VERSION 5.8 ;
BUSBITCHARS "[]" ;
DIVIDERCHAR "/" ;
UNITS
    DATABASE MICRONS 1000 ;
END UNITS

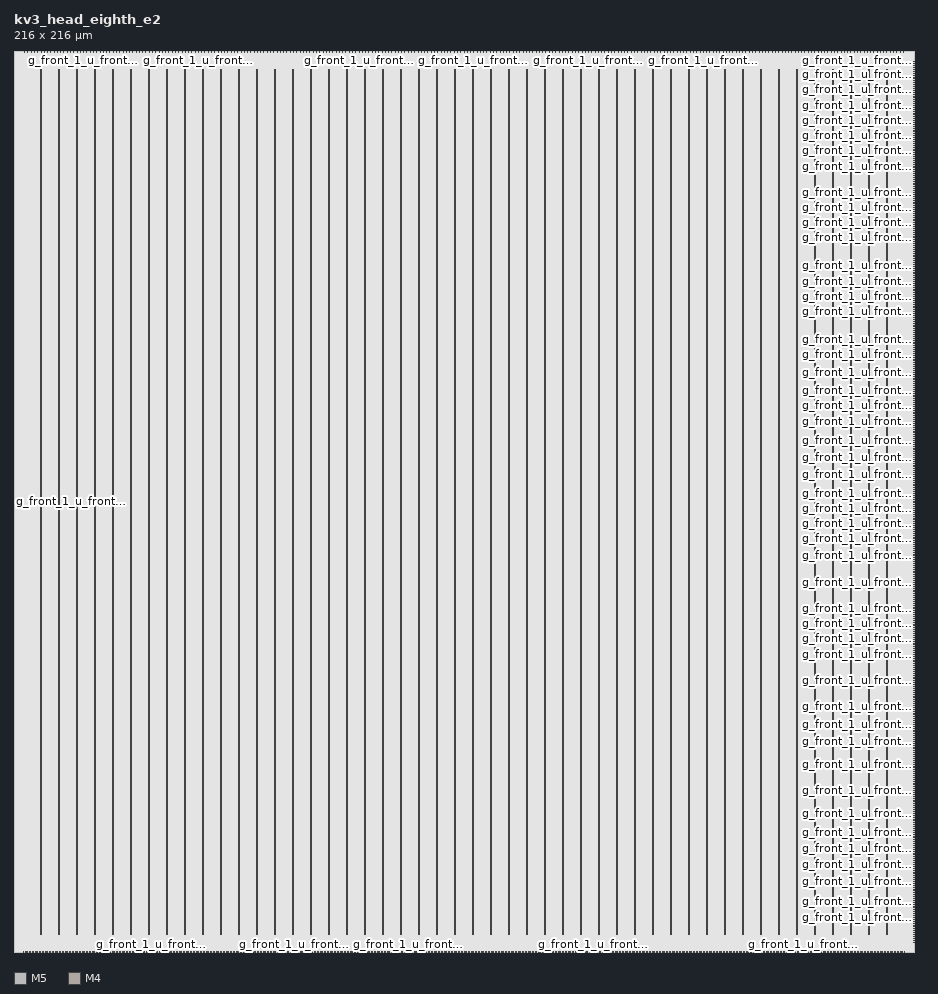
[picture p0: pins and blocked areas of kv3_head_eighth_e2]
MACRO kv3_head_eighth_e2
  FOREIGN kv3_head_eighth_e2 0 0 ;
  CLASS BLOCK ;
  SIZE 216 BY 216 ;
  PIN g_front_1_u_front__c_in[0]
    DIRECTION INPUT ;
    USE SIGNAL ;
    PORT
      LAYER M5 ;
        RECT  2.316 0 2.34 0.192 ;
    END
  END g_front_1_u_front__c_in[0]
  PIN g_front_1_u_front__c_in[1]
    DIRECTION INPUT ;
    USE SIGNAL ;
    PORT
      LAYER M5 ;
        RECT  2.652 0 2.676 0.192 ;
    END
  END g_front_1_u_front__c_in[1]
  PIN g_front_1_u_front__c_in[2]
    DIRECTION INPUT ;
    USE SIGNAL ;
    PORT
      LAYER M5 ;
        RECT  2.988 0 3.012 0.192 ;
    END
  END g_front_1_u_front__c_in[2]
  PIN g_front_1_u_front__c_in[3]
    DIRECTION INPUT ;
    USE SIGNAL ;
    PORT
      LAYER M5 ;
        RECT  3.324 0 3.348 0.192 ;
    END
  END g_front_1_u_front__c_in[3]
  PIN g_front_1_u_front__clk[0]
    DIRECTION INPUT ;
    USE SIGNAL ;
    PORT
      LAYER M5 ;
        RECT  2.556 215.808 2.58 216 ;
    END
  END g_front_1_u_front__clk[0]
  PIN g_front_1_u_front__e_in[0]
    DIRECTION INPUT ;
    USE SIGNAL ;
    PORT
      LAYER M5 ;
        RECT  3.708 0 3.732 0.192 ;
    END
  END g_front_1_u_front__e_in[0]
  PIN g_front_1_u_front__e_in[10]
    DIRECTION INPUT ;
    USE SIGNAL ;
    PORT
      LAYER M5 ;
        RECT  7.116 0 7.14 0.192 ;
    END
  END g_front_1_u_front__e_in[10]
  PIN g_front_1_u_front__e_in[11]
    DIRECTION INPUT ;
    USE SIGNAL ;
    PORT
      LAYER M5 ;
        RECT  7.452 0 7.476 0.192 ;
    END
  END g_front_1_u_front__e_in[11]
  PIN g_front_1_u_front__e_in[12]
    DIRECTION INPUT ;
    USE SIGNAL ;
    PORT
      LAYER M5 ;
        RECT  7.788 0 7.812 0.192 ;
    END
  END g_front_1_u_front__e_in[12]
  PIN g_front_1_u_front__e_in[13]
    DIRECTION INPUT ;
    USE SIGNAL ;
    PORT
      LAYER M5 ;
        RECT  8.124 0 8.148 0.192 ;
    END
  END g_front_1_u_front__e_in[13]
  PIN g_front_1_u_front__e_in[14]
    DIRECTION INPUT ;
    USE SIGNAL ;
    PORT
      LAYER M5 ;
        RECT  8.46 0 8.484 0.192 ;
    END
  END g_front_1_u_front__e_in[14]
  PIN g_front_1_u_front__e_in[15]
    DIRECTION INPUT ;
    USE SIGNAL ;
    PORT
      LAYER M5 ;
        RECT  8.796 0 8.82 0.192 ;
    END
  END g_front_1_u_front__e_in[15]
  PIN g_front_1_u_front__e_in[1]
    DIRECTION INPUT ;
    USE SIGNAL ;
    PORT
      LAYER M5 ;
        RECT  4.044 0 4.068 0.192 ;
    END
  END g_front_1_u_front__e_in[1]
  PIN g_front_1_u_front__e_in[2]
    DIRECTION INPUT ;
    USE SIGNAL ;
    PORT
      LAYER M5 ;
        RECT  4.38 0 4.404 0.192 ;
    END
  END g_front_1_u_front__e_in[2]
  PIN g_front_1_u_front__e_in[3]
    DIRECTION INPUT ;
    USE SIGNAL ;
    PORT
      LAYER M5 ;
        RECT  4.716 0 4.74 0.192 ;
    END
  END g_front_1_u_front__e_in[3]
  PIN g_front_1_u_front__e_in[4]
    DIRECTION INPUT ;
    USE SIGNAL ;
    PORT
      LAYER M5 ;
        RECT  5.052 0 5.076 0.192 ;
    END
  END g_front_1_u_front__e_in[4]
  PIN g_front_1_u_front__e_in[5]
    DIRECTION INPUT ;
    USE SIGNAL ;
    PORT
      LAYER M5 ;
        RECT  5.388 0 5.412 0.192 ;
    END
  END g_front_1_u_front__e_in[5]
  PIN g_front_1_u_front__e_in[6]
    DIRECTION INPUT ;
    USE SIGNAL ;
    PORT
      LAYER M5 ;
        RECT  5.724 0 5.748 0.192 ;
    END
  END g_front_1_u_front__e_in[6]
  PIN g_front_1_u_front__e_in[7]
    DIRECTION INPUT ;
    USE SIGNAL ;
    PORT
      LAYER M5 ;
        RECT  6.06 0 6.084 0.192 ;
    END
  END g_front_1_u_front__e_in[7]
  PIN g_front_1_u_front__e_in[8]
    DIRECTION INPUT ;
    USE SIGNAL ;
    PORT
      LAYER M5 ;
        RECT  6.444 0 6.468 0.192 ;
    END
  END g_front_1_u_front__e_in[8]
  PIN g_front_1_u_front__e_in[9]
    DIRECTION INPUT ;
    USE SIGNAL ;
    PORT
      LAYER M5 ;
        RECT  6.78 0 6.804 0.192 ;
    END
  END g_front_1_u_front__e_in[9]
  PIN g_front_1_u_front__f_t2[0]
    DIRECTION OUTPUT ;
    USE SIGNAL ;
    PORT
      LAYER M4 ;
        RECT  215.808 2.364 216 2.388 ;
    END
  END g_front_1_u_front__f_t2[0]
  PIN g_front_1_u_front__f_t2[100]
    DIRECTION OUTPUT ;
    USE SIGNAL ;
    PORT
      LAYER M4 ;
        RECT  215.808 47.82 216 47.844 ;
    END
  END g_front_1_u_front__f_t2[100]
  PIN g_front_1_u_front__f_t2[101]
    DIRECTION OUTPUT ;
    USE SIGNAL ;
    PORT
      LAYER M4 ;
        RECT  215.808 48.252 216 48.276 ;
    END
  END g_front_1_u_front__f_t2[101]
  PIN g_front_1_u_front__f_t2[102]
    DIRECTION OUTPUT ;
    USE SIGNAL ;
    PORT
      LAYER M4 ;
        RECT  215.808 48.732 216 48.756 ;
    END
  END g_front_1_u_front__f_t2[102]
  PIN g_front_1_u_front__f_t2[103]
    DIRECTION OUTPUT ;
    USE SIGNAL ;
    PORT
      LAYER M4 ;
        RECT  215.808 49.164 216 49.188 ;
    END
  END g_front_1_u_front__f_t2[103]
  PIN g_front_1_u_front__f_t2[104]
    DIRECTION OUTPUT ;
    USE SIGNAL ;
    PORT
      LAYER M4 ;
        RECT  215.808 49.596 216 49.62 ;
    END
  END g_front_1_u_front__f_t2[104]
  PIN g_front_1_u_front__f_t2[105]
    DIRECTION OUTPUT ;
    USE SIGNAL ;
    PORT
      LAYER M4 ;
        RECT  215.808 50.076 216 50.1 ;
    END
  END g_front_1_u_front__f_t2[105]
  PIN g_front_1_u_front__f_t2[106]
    DIRECTION OUTPUT ;
    USE SIGNAL ;
    PORT
      LAYER M4 ;
        RECT  215.808 50.508 216 50.532 ;
    END
  END g_front_1_u_front__f_t2[106]
  PIN g_front_1_u_front__f_t2[107]
    DIRECTION OUTPUT ;
    USE SIGNAL ;
    PORT
      LAYER M4 ;
        RECT  215.808 50.988 216 51.012 ;
    END
  END g_front_1_u_front__f_t2[107]
  PIN g_front_1_u_front__f_t2[108]
    DIRECTION OUTPUT ;
    USE SIGNAL ;
    PORT
      LAYER M4 ;
        RECT  215.808 51.42 216 51.444 ;
    END
  END g_front_1_u_front__f_t2[108]
  PIN g_front_1_u_front__f_t2[109]
    DIRECTION OUTPUT ;
    USE SIGNAL ;
    PORT
      LAYER M4 ;
        RECT  215.808 51.9 216 51.924 ;
    END
  END g_front_1_u_front__f_t2[109]
  PIN g_front_1_u_front__f_t2[10]
    DIRECTION OUTPUT ;
    USE SIGNAL ;
    PORT
      LAYER M4 ;
        RECT  215.808 6.924 216 6.948 ;
    END
  END g_front_1_u_front__f_t2[10]
  PIN g_front_1_u_front__f_t2[110]
    DIRECTION OUTPUT ;
    USE SIGNAL ;
    PORT
      LAYER M4 ;
        RECT  215.808 52.332 216 52.356 ;
    END
  END g_front_1_u_front__f_t2[110]
  PIN g_front_1_u_front__f_t2[111]
    DIRECTION OUTPUT ;
    USE SIGNAL ;
    PORT
      LAYER M4 ;
        RECT  215.808 52.812 216 52.836 ;
    END
  END g_front_1_u_front__f_t2[111]
  PIN g_front_1_u_front__f_t2[112]
    DIRECTION OUTPUT ;
    USE SIGNAL ;
    PORT
      LAYER M4 ;
        RECT  215.808 53.244 216 53.268 ;
    END
  END g_front_1_u_front__f_t2[112]
  PIN g_front_1_u_front__f_t2[113]
    DIRECTION OUTPUT ;
    USE SIGNAL ;
    PORT
      LAYER M4 ;
        RECT  215.808 53.724 216 53.748 ;
    END
  END g_front_1_u_front__f_t2[113]
  PIN g_front_1_u_front__f_t2[114]
    DIRECTION OUTPUT ;
    USE SIGNAL ;
    PORT
      LAYER M4 ;
        RECT  215.808 54.156 216 54.18 ;
    END
  END g_front_1_u_front__f_t2[114]
  PIN g_front_1_u_front__f_t2[115]
    DIRECTION OUTPUT ;
    USE SIGNAL ;
    PORT
      LAYER M4 ;
        RECT  215.808 54.636 216 54.66 ;
    END
  END g_front_1_u_front__f_t2[115]
  PIN g_front_1_u_front__f_t2[116]
    DIRECTION OUTPUT ;
    USE SIGNAL ;
    PORT
      LAYER M4 ;
        RECT  215.808 55.068 216 55.092 ;
    END
  END g_front_1_u_front__f_t2[116]
  PIN g_front_1_u_front__f_t2[117]
    DIRECTION OUTPUT ;
    USE SIGNAL ;
    PORT
      LAYER M4 ;
        RECT  215.808 55.5 216 55.524 ;
    END
  END g_front_1_u_front__f_t2[117]
  PIN g_front_1_u_front__f_t2[118]
    DIRECTION OUTPUT ;
    USE SIGNAL ;
    PORT
      LAYER M4 ;
        RECT  215.808 55.98 216 56.004 ;
    END
  END g_front_1_u_front__f_t2[118]
  PIN g_front_1_u_front__f_t2[119]
    DIRECTION OUTPUT ;
    USE SIGNAL ;
    PORT
      LAYER M4 ;
        RECT  215.808 56.412 216 56.436 ;
    END
  END g_front_1_u_front__f_t2[119]
  PIN g_front_1_u_front__f_t2[11]
    DIRECTION OUTPUT ;
    USE SIGNAL ;
    PORT
      LAYER M4 ;
        RECT  215.808 7.356 216 7.38 ;
    END
  END g_front_1_u_front__f_t2[11]
  PIN g_front_1_u_front__f_t2[120]
    DIRECTION OUTPUT ;
    USE SIGNAL ;
    PORT
      LAYER M4 ;
        RECT  215.808 56.892 216 56.916 ;
    END
  END g_front_1_u_front__f_t2[120]
  PIN g_front_1_u_front__f_t2[121]
    DIRECTION OUTPUT ;
    USE SIGNAL ;
    PORT
      LAYER M4 ;
        RECT  215.808 57.324 216 57.348 ;
    END
  END g_front_1_u_front__f_t2[121]
  PIN g_front_1_u_front__f_t2[122]
    DIRECTION OUTPUT ;
    USE SIGNAL ;
    PORT
      LAYER M4 ;
        RECT  215.808 57.804 216 57.828 ;
    END
  END g_front_1_u_front__f_t2[122]
  PIN g_front_1_u_front__f_t2[123]
    DIRECTION OUTPUT ;
    USE SIGNAL ;
    PORT
      LAYER M4 ;
        RECT  215.808 58.236 216 58.26 ;
    END
  END g_front_1_u_front__f_t2[123]
  PIN g_front_1_u_front__f_t2[124]
    DIRECTION OUTPUT ;
    USE SIGNAL ;
    PORT
      LAYER M4 ;
        RECT  215.808 58.716 216 58.74 ;
    END
  END g_front_1_u_front__f_t2[124]
  PIN g_front_1_u_front__f_t2[125]
    DIRECTION OUTPUT ;
    USE SIGNAL ;
    PORT
      LAYER M4 ;
        RECT  215.808 59.148 216 59.172 ;
    END
  END g_front_1_u_front__f_t2[125]
  PIN g_front_1_u_front__f_t2[126]
    DIRECTION OUTPUT ;
    USE SIGNAL ;
    PORT
      LAYER M4 ;
        RECT  215.808 59.628 216 59.652 ;
    END
  END g_front_1_u_front__f_t2[126]
  PIN g_front_1_u_front__f_t2[127]
    DIRECTION OUTPUT ;
    USE SIGNAL ;
    PORT
      LAYER M4 ;
        RECT  215.808 60.06 216 60.084 ;
    END
  END g_front_1_u_front__f_t2[127]
  PIN g_front_1_u_front__f_t2[128]
    DIRECTION OUTPUT ;
    USE SIGNAL ;
    PORT
      LAYER M4 ;
        RECT  215.808 60.54 216 60.564 ;
    END
  END g_front_1_u_front__f_t2[128]
  PIN g_front_1_u_front__f_t2[129]
    DIRECTION OUTPUT ;
    USE SIGNAL ;
    PORT
      LAYER M4 ;
        RECT  215.808 60.972 216 60.996 ;
    END
  END g_front_1_u_front__f_t2[129]
  PIN g_front_1_u_front__f_t2[12]
    DIRECTION OUTPUT ;
    USE SIGNAL ;
    PORT
      LAYER M4 ;
        RECT  215.808 7.836 216 7.86 ;
    END
  END g_front_1_u_front__f_t2[12]
  PIN g_front_1_u_front__f_t2[130]
    DIRECTION OUTPUT ;
    USE SIGNAL ;
    PORT
      LAYER M4 ;
        RECT  215.808 61.404 216 61.428 ;
    END
  END g_front_1_u_front__f_t2[130]
  PIN g_front_1_u_front__f_t2[131]
    DIRECTION OUTPUT ;
    USE SIGNAL ;
    PORT
      LAYER M4 ;
        RECT  215.808 61.884 216 61.908 ;
    END
  END g_front_1_u_front__f_t2[131]
  PIN g_front_1_u_front__f_t2[132]
    DIRECTION OUTPUT ;
    USE SIGNAL ;
    PORT
      LAYER M4 ;
        RECT  215.808 62.316 216 62.34 ;
    END
  END g_front_1_u_front__f_t2[132]
  PIN g_front_1_u_front__f_t2[133]
    DIRECTION OUTPUT ;
    USE SIGNAL ;
    PORT
      LAYER M4 ;
        RECT  215.808 62.796 216 62.82 ;
    END
  END g_front_1_u_front__f_t2[133]
  PIN g_front_1_u_front__f_t2[134]
    DIRECTION OUTPUT ;
    USE SIGNAL ;
    PORT
      LAYER M4 ;
        RECT  215.808 63.228 216 63.252 ;
    END
  END g_front_1_u_front__f_t2[134]
  PIN g_front_1_u_front__f_t2[135]
    DIRECTION OUTPUT ;
    USE SIGNAL ;
    PORT
      LAYER M4 ;
        RECT  215.808 63.708 216 63.732 ;
    END
  END g_front_1_u_front__f_t2[135]
  PIN g_front_1_u_front__f_t2[136]
    DIRECTION OUTPUT ;
    USE SIGNAL ;
    PORT
      LAYER M4 ;
        RECT  215.808 64.14 216 64.164 ;
    END
  END g_front_1_u_front__f_t2[136]
  PIN g_front_1_u_front__f_t2[137]
    DIRECTION OUTPUT ;
    USE SIGNAL ;
    PORT
      LAYER M4 ;
        RECT  215.808 64.62 216 64.644 ;
    END
  END g_front_1_u_front__f_t2[137]
  PIN g_front_1_u_front__f_t2[138]
    DIRECTION OUTPUT ;
    USE SIGNAL ;
    PORT
      LAYER M4 ;
        RECT  215.808 65.052 216 65.076 ;
    END
  END g_front_1_u_front__f_t2[138]
  PIN g_front_1_u_front__f_t2[139]
    DIRECTION OUTPUT ;
    USE SIGNAL ;
    PORT
      LAYER M4 ;
        RECT  215.808 65.532 216 65.556 ;
    END
  END g_front_1_u_front__f_t2[139]
  PIN g_front_1_u_front__f_t2[13]
    DIRECTION OUTPUT ;
    USE SIGNAL ;
    PORT
      LAYER M4 ;
        RECT  215.808 8.268 216 8.292 ;
    END
  END g_front_1_u_front__f_t2[13]
  PIN g_front_1_u_front__f_t2[140]
    DIRECTION OUTPUT ;
    USE SIGNAL ;
    PORT
      LAYER M4 ;
        RECT  215.808 65.964 216 65.988 ;
    END
  END g_front_1_u_front__f_t2[140]
  PIN g_front_1_u_front__f_t2[141]
    DIRECTION OUTPUT ;
    USE SIGNAL ;
    PORT
      LAYER M4 ;
        RECT  215.808 66.444 216 66.468 ;
    END
  END g_front_1_u_front__f_t2[141]
  PIN g_front_1_u_front__f_t2[142]
    DIRECTION OUTPUT ;
    USE SIGNAL ;
    PORT
      LAYER M4 ;
        RECT  215.808 66.876 216 66.9 ;
    END
  END g_front_1_u_front__f_t2[142]
  PIN g_front_1_u_front__f_t2[143]
    DIRECTION OUTPUT ;
    USE SIGNAL ;
    PORT
      LAYER M4 ;
        RECT  215.808 67.356 216 67.38 ;
    END
  END g_front_1_u_front__f_t2[143]
  PIN g_front_1_u_front__f_t2[144]
    DIRECTION OUTPUT ;
    USE SIGNAL ;
    PORT
      LAYER M4 ;
        RECT  215.808 67.788 216 67.812 ;
    END
  END g_front_1_u_front__f_t2[144]
  PIN g_front_1_u_front__f_t2[145]
    DIRECTION OUTPUT ;
    USE SIGNAL ;
    PORT
      LAYER M4 ;
        RECT  215.808 68.22 216 68.244 ;
    END
  END g_front_1_u_front__f_t2[145]
  PIN g_front_1_u_front__f_t2[146]
    DIRECTION OUTPUT ;
    USE SIGNAL ;
    PORT
      LAYER M4 ;
        RECT  215.808 68.7 216 68.724 ;
    END
  END g_front_1_u_front__f_t2[146]
  PIN g_front_1_u_front__f_t2[147]
    DIRECTION OUTPUT ;
    USE SIGNAL ;
    PORT
      LAYER M4 ;
        RECT  215.808 69.132 216 69.156 ;
    END
  END g_front_1_u_front__f_t2[147]
  PIN g_front_1_u_front__f_t2[148]
    DIRECTION OUTPUT ;
    USE SIGNAL ;
    PORT
      LAYER M4 ;
        RECT  215.808 69.612 216 69.636 ;
    END
  END g_front_1_u_front__f_t2[148]
  PIN g_front_1_u_front__f_t2[149]
    DIRECTION OUTPUT ;
    USE SIGNAL ;
    PORT
      LAYER M4 ;
        RECT  215.808 70.044 216 70.068 ;
    END
  END g_front_1_u_front__f_t2[149]
  PIN g_front_1_u_front__f_t2[14]
    DIRECTION OUTPUT ;
    USE SIGNAL ;
    PORT
      LAYER M4 ;
        RECT  215.808 8.748 216 8.772 ;
    END
  END g_front_1_u_front__f_t2[14]
  PIN g_front_1_u_front__f_t2[150]
    DIRECTION OUTPUT ;
    USE SIGNAL ;
    PORT
      LAYER M4 ;
        RECT  215.808 70.524 216 70.548 ;
    END
  END g_front_1_u_front__f_t2[150]
  PIN g_front_1_u_front__f_t2[151]
    DIRECTION OUTPUT ;
    USE SIGNAL ;
    PORT
      LAYER M4 ;
        RECT  215.808 70.956 216 70.98 ;
    END
  END g_front_1_u_front__f_t2[151]
  PIN g_front_1_u_front__f_t2[152]
    DIRECTION OUTPUT ;
    USE SIGNAL ;
    PORT
      LAYER M4 ;
        RECT  215.808 71.436 216 71.46 ;
    END
  END g_front_1_u_front__f_t2[152]
  PIN g_front_1_u_front__f_t2[153]
    DIRECTION OUTPUT ;
    USE SIGNAL ;
    PORT
      LAYER M4 ;
        RECT  215.808 71.868 216 71.892 ;
    END
  END g_front_1_u_front__f_t2[153]
  PIN g_front_1_u_front__f_t2[154]
    DIRECTION OUTPUT ;
    USE SIGNAL ;
    PORT
      LAYER M4 ;
        RECT  215.808 72.348 216 72.372 ;
    END
  END g_front_1_u_front__f_t2[154]
  PIN g_front_1_u_front__f_t2[155]
    DIRECTION OUTPUT ;
    USE SIGNAL ;
    PORT
      LAYER M4 ;
        RECT  215.808 72.78 216 72.804 ;
    END
  END g_front_1_u_front__f_t2[155]
  PIN g_front_1_u_front__f_t2[156]
    DIRECTION OUTPUT ;
    USE SIGNAL ;
    PORT
      LAYER M4 ;
        RECT  215.808 73.26 216 73.284 ;
    END
  END g_front_1_u_front__f_t2[156]
  PIN g_front_1_u_front__f_t2[157]
    DIRECTION OUTPUT ;
    USE SIGNAL ;
    PORT
      LAYER M4 ;
        RECT  215.808 73.692 216 73.716 ;
    END
  END g_front_1_u_front__f_t2[157]
  PIN g_front_1_u_front__f_t2[158]
    DIRECTION OUTPUT ;
    USE SIGNAL ;
    PORT
      LAYER M4 ;
        RECT  215.808 74.124 216 74.148 ;
    END
  END g_front_1_u_front__f_t2[158]
  PIN g_front_1_u_front__f_t2[159]
    DIRECTION OUTPUT ;
    USE SIGNAL ;
    PORT
      LAYER M4 ;
        RECT  215.808 74.604 216 74.628 ;
    END
  END g_front_1_u_front__f_t2[159]
  PIN g_front_1_u_front__f_t2[15]
    DIRECTION OUTPUT ;
    USE SIGNAL ;
    PORT
      LAYER M4 ;
        RECT  215.808 9.18 216 9.204 ;
    END
  END g_front_1_u_front__f_t2[15]
  PIN g_front_1_u_front__f_t2[160]
    DIRECTION OUTPUT ;
    USE SIGNAL ;
    PORT
      LAYER M4 ;
        RECT  215.808 75.036 216 75.06 ;
    END
  END g_front_1_u_front__f_t2[160]
  PIN g_front_1_u_front__f_t2[161]
    DIRECTION OUTPUT ;
    USE SIGNAL ;
    PORT
      LAYER M4 ;
        RECT  215.808 75.516 216 75.54 ;
    END
  END g_front_1_u_front__f_t2[161]
  PIN g_front_1_u_front__f_t2[162]
    DIRECTION OUTPUT ;
    USE SIGNAL ;
    PORT
      LAYER M4 ;
        RECT  215.808 75.948 216 75.972 ;
    END
  END g_front_1_u_front__f_t2[162]
  PIN g_front_1_u_front__f_t2[163]
    DIRECTION OUTPUT ;
    USE SIGNAL ;
    PORT
      LAYER M4 ;
        RECT  215.808 76.428 216 76.452 ;
    END
  END g_front_1_u_front__f_t2[163]
  PIN g_front_1_u_front__f_t2[164]
    DIRECTION OUTPUT ;
    USE SIGNAL ;
    PORT
      LAYER M4 ;
        RECT  215.808 76.86 216 76.884 ;
    END
  END g_front_1_u_front__f_t2[164]
  PIN g_front_1_u_front__f_t2[165]
    DIRECTION OUTPUT ;
    USE SIGNAL ;
    PORT
      LAYER M4 ;
        RECT  215.808 77.34 216 77.364 ;
    END
  END g_front_1_u_front__f_t2[165]
  PIN g_front_1_u_front__f_t2[166]
    DIRECTION OUTPUT ;
    USE SIGNAL ;
    PORT
      LAYER M4 ;
        RECT  215.808 77.772 216 77.796 ;
    END
  END g_front_1_u_front__f_t2[166]
  PIN g_front_1_u_front__f_t2[167]
    DIRECTION OUTPUT ;
    USE SIGNAL ;
    PORT
      LAYER M4 ;
        RECT  215.808 78.252 216 78.276 ;
    END
  END g_front_1_u_front__f_t2[167]
  PIN g_front_1_u_front__f_t2[168]
    DIRECTION OUTPUT ;
    USE SIGNAL ;
    PORT
      LAYER M4 ;
        RECT  215.808 78.684 216 78.708 ;
    END
  END g_front_1_u_front__f_t2[168]
  PIN g_front_1_u_front__f_t2[169]
    DIRECTION OUTPUT ;
    USE SIGNAL ;
    PORT
      LAYER M4 ;
        RECT  215.808 79.164 216 79.188 ;
    END
  END g_front_1_u_front__f_t2[169]
  PIN g_front_1_u_front__f_t2[16]
    DIRECTION OUTPUT ;
    USE SIGNAL ;
    PORT
      LAYER M4 ;
        RECT  215.808 9.66 216 9.684 ;
    END
  END g_front_1_u_front__f_t2[16]
  PIN g_front_1_u_front__f_t2[170]
    DIRECTION OUTPUT ;
    USE SIGNAL ;
    PORT
      LAYER M4 ;
        RECT  215.808 79.596 216 79.62 ;
    END
  END g_front_1_u_front__f_t2[170]
  PIN g_front_1_u_front__f_t2[171]
    DIRECTION OUTPUT ;
    USE SIGNAL ;
    PORT
      LAYER M4 ;
        RECT  215.808 80.028 216 80.052 ;
    END
  END g_front_1_u_front__f_t2[171]
  PIN g_front_1_u_front__f_t2[172]
    DIRECTION OUTPUT ;
    USE SIGNAL ;
    PORT
      LAYER M4 ;
        RECT  215.808 80.508 216 80.532 ;
    END
  END g_front_1_u_front__f_t2[172]
  PIN g_front_1_u_front__f_t2[173]
    DIRECTION OUTPUT ;
    USE SIGNAL ;
    PORT
      LAYER M4 ;
        RECT  215.808 80.94 216 80.964 ;
    END
  END g_front_1_u_front__f_t2[173]
  PIN g_front_1_u_front__f_t2[174]
    DIRECTION OUTPUT ;
    USE SIGNAL ;
    PORT
      LAYER M4 ;
        RECT  215.808 81.42 216 81.444 ;
    END
  END g_front_1_u_front__f_t2[174]
  PIN g_front_1_u_front__f_t2[175]
    DIRECTION OUTPUT ;
    USE SIGNAL ;
    PORT
      LAYER M4 ;
        RECT  215.808 81.852 216 81.876 ;
    END
  END g_front_1_u_front__f_t2[175]
  PIN g_front_1_u_front__f_t2[176]
    DIRECTION OUTPUT ;
    USE SIGNAL ;
    PORT
      LAYER M4 ;
        RECT  215.808 82.332 216 82.356 ;
    END
  END g_front_1_u_front__f_t2[176]
  PIN g_front_1_u_front__f_t2[177]
    DIRECTION OUTPUT ;
    USE SIGNAL ;
    PORT
      LAYER M4 ;
        RECT  215.808 82.764 216 82.788 ;
    END
  END g_front_1_u_front__f_t2[177]
  PIN g_front_1_u_front__f_t2[178]
    DIRECTION OUTPUT ;
    USE SIGNAL ;
    PORT
      LAYER M4 ;
        RECT  215.808 83.244 216 83.268 ;
    END
  END g_front_1_u_front__f_t2[178]
  PIN g_front_1_u_front__f_t2[179]
    DIRECTION OUTPUT ;
    USE SIGNAL ;
    PORT
      LAYER M4 ;
        RECT  215.808 83.676 216 83.7 ;
    END
  END g_front_1_u_front__f_t2[179]
  PIN g_front_1_u_front__f_t2[17]
    DIRECTION OUTPUT ;
    USE SIGNAL ;
    PORT
      LAYER M4 ;
        RECT  215.808 10.092 216 10.116 ;
    END
  END g_front_1_u_front__f_t2[17]
  PIN g_front_1_u_front__f_t2[180]
    DIRECTION OUTPUT ;
    USE SIGNAL ;
    PORT
      LAYER M4 ;
        RECT  215.808 84.156 216 84.18 ;
    END
  END g_front_1_u_front__f_t2[180]
  PIN g_front_1_u_front__f_t2[181]
    DIRECTION OUTPUT ;
    USE SIGNAL ;
    PORT
      LAYER M4 ;
        RECT  215.808 84.588 216 84.612 ;
    END
  END g_front_1_u_front__f_t2[181]
  PIN g_front_1_u_front__f_t2[182]
    DIRECTION OUTPUT ;
    USE SIGNAL ;
    PORT
      LAYER M4 ;
        RECT  215.808 85.068 216 85.092 ;
    END
  END g_front_1_u_front__f_t2[182]
  PIN g_front_1_u_front__f_t2[183]
    DIRECTION OUTPUT ;
    USE SIGNAL ;
    PORT
      LAYER M4 ;
        RECT  215.808 85.5 216 85.524 ;
    END
  END g_front_1_u_front__f_t2[183]
  PIN g_front_1_u_front__f_t2[184]
    DIRECTION OUTPUT ;
    USE SIGNAL ;
    PORT
      LAYER M4 ;
        RECT  215.808 85.98 216 86.004 ;
    END
  END g_front_1_u_front__f_t2[184]
  PIN g_front_1_u_front__f_t2[185]
    DIRECTION OUTPUT ;
    USE SIGNAL ;
    PORT
      LAYER M4 ;
        RECT  215.808 86.412 216 86.436 ;
    END
  END g_front_1_u_front__f_t2[185]
  PIN g_front_1_u_front__f_t2[186]
    DIRECTION OUTPUT ;
    USE SIGNAL ;
    PORT
      LAYER M4 ;
        RECT  215.808 86.844 216 86.868 ;
    END
  END g_front_1_u_front__f_t2[186]
  PIN g_front_1_u_front__f_t2[187]
    DIRECTION OUTPUT ;
    USE SIGNAL ;
    PORT
      LAYER M4 ;
        RECT  215.808 87.324 216 87.348 ;
    END
  END g_front_1_u_front__f_t2[187]
  PIN g_front_1_u_front__f_t2[188]
    DIRECTION OUTPUT ;
    USE SIGNAL ;
    PORT
      LAYER M4 ;
        RECT  215.808 87.756 216 87.78 ;
    END
  END g_front_1_u_front__f_t2[188]
  PIN g_front_1_u_front__f_t2[189]
    DIRECTION OUTPUT ;
    USE SIGNAL ;
    PORT
      LAYER M4 ;
        RECT  215.808 88.236 216 88.26 ;
    END
  END g_front_1_u_front__f_t2[189]
  PIN g_front_1_u_front__f_t2[18]
    DIRECTION OUTPUT ;
    USE SIGNAL ;
    PORT
      LAYER M4 ;
        RECT  215.808 10.572 216 10.596 ;
    END
  END g_front_1_u_front__f_t2[18]
  PIN g_front_1_u_front__f_t2[190]
    DIRECTION OUTPUT ;
    USE SIGNAL ;
    PORT
      LAYER M4 ;
        RECT  215.808 88.668 216 88.692 ;
    END
  END g_front_1_u_front__f_t2[190]
  PIN g_front_1_u_front__f_t2[191]
    DIRECTION OUTPUT ;
    USE SIGNAL ;
    PORT
      LAYER M4 ;
        RECT  215.808 89.148 216 89.172 ;
    END
  END g_front_1_u_front__f_t2[191]
  PIN g_front_1_u_front__f_t2[192]
    DIRECTION OUTPUT ;
    USE SIGNAL ;
    PORT
      LAYER M4 ;
        RECT  215.808 89.58 216 89.604 ;
    END
  END g_front_1_u_front__f_t2[192]
  PIN g_front_1_u_front__f_t2[193]
    DIRECTION OUTPUT ;
    USE SIGNAL ;
    PORT
      LAYER M4 ;
        RECT  215.808 90.06 216 90.084 ;
    END
  END g_front_1_u_front__f_t2[193]
  PIN g_front_1_u_front__f_t2[194]
    DIRECTION OUTPUT ;
    USE SIGNAL ;
    PORT
      LAYER M4 ;
        RECT  215.808 90.492 216 90.516 ;
    END
  END g_front_1_u_front__f_t2[194]
  PIN g_front_1_u_front__f_t2[195]
    DIRECTION OUTPUT ;
    USE SIGNAL ;
    PORT
      LAYER M4 ;
        RECT  215.808 90.972 216 90.996 ;
    END
  END g_front_1_u_front__f_t2[195]
  PIN g_front_1_u_front__f_t2[196]
    DIRECTION OUTPUT ;
    USE SIGNAL ;
    PORT
      LAYER M4 ;
        RECT  215.808 91.404 216 91.428 ;
    END
  END g_front_1_u_front__f_t2[196]
  PIN g_front_1_u_front__f_t2[197]
    DIRECTION OUTPUT ;
    USE SIGNAL ;
    PORT
      LAYER M4 ;
        RECT  215.808 91.884 216 91.908 ;
    END
  END g_front_1_u_front__f_t2[197]
  PIN g_front_1_u_front__f_t2[198]
    DIRECTION OUTPUT ;
    USE SIGNAL ;
    PORT
      LAYER M4 ;
        RECT  215.808 92.316 216 92.34 ;
    END
  END g_front_1_u_front__f_t2[198]
  PIN g_front_1_u_front__f_t2[199]
    DIRECTION OUTPUT ;
    USE SIGNAL ;
    PORT
      LAYER M4 ;
        RECT  215.808 92.748 216 92.772 ;
    END
  END g_front_1_u_front__f_t2[199]
  PIN g_front_1_u_front__f_t2[19]
    DIRECTION OUTPUT ;
    USE SIGNAL ;
    PORT
      LAYER M4 ;
        RECT  215.808 11.004 216 11.028 ;
    END
  END g_front_1_u_front__f_t2[19]
  PIN g_front_1_u_front__f_t2[1]
    DIRECTION OUTPUT ;
    USE SIGNAL ;
    PORT
      LAYER M4 ;
        RECT  215.808 2.844 216 2.868 ;
    END
  END g_front_1_u_front__f_t2[1]
  PIN g_front_1_u_front__f_t2[200]
    DIRECTION OUTPUT ;
    USE SIGNAL ;
    PORT
      LAYER M4 ;
        RECT  215.808 93.228 216 93.252 ;
    END
  END g_front_1_u_front__f_t2[200]
  PIN g_front_1_u_front__f_t2[201]
    DIRECTION OUTPUT ;
    USE SIGNAL ;
    PORT
      LAYER M4 ;
        RECT  215.808 93.66 216 93.684 ;
    END
  END g_front_1_u_front__f_t2[201]
  PIN g_front_1_u_front__f_t2[202]
    DIRECTION OUTPUT ;
    USE SIGNAL ;
    PORT
      LAYER M4 ;
        RECT  215.808 94.14 216 94.164 ;
    END
  END g_front_1_u_front__f_t2[202]
  PIN g_front_1_u_front__f_t2[203]
    DIRECTION OUTPUT ;
    USE SIGNAL ;
    PORT
      LAYER M4 ;
        RECT  215.808 94.572 216 94.596 ;
    END
  END g_front_1_u_front__f_t2[203]
  PIN g_front_1_u_front__f_t2[204]
    DIRECTION OUTPUT ;
    USE SIGNAL ;
    PORT
      LAYER M4 ;
        RECT  215.808 95.052 216 95.076 ;
    END
  END g_front_1_u_front__f_t2[204]
  PIN g_front_1_u_front__f_t2[205]
    DIRECTION OUTPUT ;
    USE SIGNAL ;
    PORT
      LAYER M4 ;
        RECT  215.808 95.484 216 95.508 ;
    END
  END g_front_1_u_front__f_t2[205]
  PIN g_front_1_u_front__f_t2[206]
    DIRECTION OUTPUT ;
    USE SIGNAL ;
    PORT
      LAYER M4 ;
        RECT  215.808 95.964 216 95.988 ;
    END
  END g_front_1_u_front__f_t2[206]
  PIN g_front_1_u_front__f_t2[207]
    DIRECTION OUTPUT ;
    USE SIGNAL ;
    PORT
      LAYER M4 ;
        RECT  215.808 96.396 216 96.42 ;
    END
  END g_front_1_u_front__f_t2[207]
  PIN g_front_1_u_front__f_t2[208]
    DIRECTION OUTPUT ;
    USE SIGNAL ;
    PORT
      LAYER M4 ;
        RECT  215.808 96.876 216 96.9 ;
    END
  END g_front_1_u_front__f_t2[208]
  PIN g_front_1_u_front__f_t2[209]
    DIRECTION OUTPUT ;
    USE SIGNAL ;
    PORT
      LAYER M4 ;
        RECT  215.808 97.308 216 97.332 ;
    END
  END g_front_1_u_front__f_t2[209]
  PIN g_front_1_u_front__f_t2[20]
    DIRECTION OUTPUT ;
    USE SIGNAL ;
    PORT
      LAYER M4 ;
        RECT  215.808 11.484 216 11.508 ;
    END
  END g_front_1_u_front__f_t2[20]
  PIN g_front_1_u_front__f_t2[210]
    DIRECTION OUTPUT ;
    USE SIGNAL ;
    PORT
      LAYER M4 ;
        RECT  215.808 97.788 216 97.812 ;
    END
  END g_front_1_u_front__f_t2[210]
  PIN g_front_1_u_front__f_t2[211]
    DIRECTION OUTPUT ;
    USE SIGNAL ;
    PORT
      LAYER M4 ;
        RECT  215.808 98.22 216 98.244 ;
    END
  END g_front_1_u_front__f_t2[211]
  PIN g_front_1_u_front__f_t2[212]
    DIRECTION OUTPUT ;
    USE SIGNAL ;
    PORT
      LAYER M4 ;
        RECT  215.808 98.652 216 98.676 ;
    END
  END g_front_1_u_front__f_t2[212]
  PIN g_front_1_u_front__f_t2[213]
    DIRECTION OUTPUT ;
    USE SIGNAL ;
    PORT
      LAYER M4 ;
        RECT  215.808 99.132 216 99.156 ;
    END
  END g_front_1_u_front__f_t2[213]
  PIN g_front_1_u_front__f_t2[214]
    DIRECTION OUTPUT ;
    USE SIGNAL ;
    PORT
      LAYER M4 ;
        RECT  215.808 99.564 216 99.588 ;
    END
  END g_front_1_u_front__f_t2[214]
  PIN g_front_1_u_front__f_t2[215]
    DIRECTION OUTPUT ;
    USE SIGNAL ;
    PORT
      LAYER M4 ;
        RECT  215.808 100.044 216 100.068 ;
    END
  END g_front_1_u_front__f_t2[215]
  PIN g_front_1_u_front__f_t2[216]
    DIRECTION OUTPUT ;
    USE SIGNAL ;
    PORT
      LAYER M4 ;
        RECT  215.808 100.476 216 100.5 ;
    END
  END g_front_1_u_front__f_t2[216]
  PIN g_front_1_u_front__f_t2[217]
    DIRECTION OUTPUT ;
    USE SIGNAL ;
    PORT
      LAYER M4 ;
        RECT  215.808 100.956 216 100.98 ;
    END
  END g_front_1_u_front__f_t2[217]
  PIN g_front_1_u_front__f_t2[218]
    DIRECTION OUTPUT ;
    USE SIGNAL ;
    PORT
      LAYER M4 ;
        RECT  215.808 101.388 216 101.412 ;
    END
  END g_front_1_u_front__f_t2[218]
  PIN g_front_1_u_front__f_t2[219]
    DIRECTION OUTPUT ;
    USE SIGNAL ;
    PORT
      LAYER M4 ;
        RECT  215.808 101.868 216 101.892 ;
    END
  END g_front_1_u_front__f_t2[219]
  PIN g_front_1_u_front__f_t2[21]
    DIRECTION OUTPUT ;
    USE SIGNAL ;
    PORT
      LAYER M4 ;
        RECT  215.808 11.916 216 11.94 ;
    END
  END g_front_1_u_front__f_t2[21]
  PIN g_front_1_u_front__f_t2[220]
    DIRECTION OUTPUT ;
    USE SIGNAL ;
    PORT
      LAYER M4 ;
        RECT  215.808 102.3 216 102.324 ;
    END
  END g_front_1_u_front__f_t2[220]
  PIN g_front_1_u_front__f_t2[221]
    DIRECTION OUTPUT ;
    USE SIGNAL ;
    PORT
      LAYER M4 ;
        RECT  215.808 102.78 216 102.804 ;
    END
  END g_front_1_u_front__f_t2[221]
  PIN g_front_1_u_front__f_t2[222]
    DIRECTION OUTPUT ;
    USE SIGNAL ;
    PORT
      LAYER M4 ;
        RECT  215.808 103.212 216 103.236 ;
    END
  END g_front_1_u_front__f_t2[222]
  PIN g_front_1_u_front__f_t2[223]
    DIRECTION OUTPUT ;
    USE SIGNAL ;
    PORT
      LAYER M4 ;
        RECT  215.808 103.692 216 103.716 ;
    END
  END g_front_1_u_front__f_t2[223]
  PIN g_front_1_u_front__f_t2[224]
    DIRECTION OUTPUT ;
    USE SIGNAL ;
    PORT
      LAYER M4 ;
        RECT  215.808 104.124 216 104.148 ;
    END
  END g_front_1_u_front__f_t2[224]
  PIN g_front_1_u_front__f_t2[225]
    DIRECTION OUTPUT ;
    USE SIGNAL ;
    PORT
      LAYER M4 ;
        RECT  215.808 104.604 216 104.628 ;
    END
  END g_front_1_u_front__f_t2[225]
  PIN g_front_1_u_front__f_t2[226]
    DIRECTION OUTPUT ;
    USE SIGNAL ;
    PORT
      LAYER M4 ;
        RECT  215.808 105.036 216 105.06 ;
    END
  END g_front_1_u_front__f_t2[226]
  PIN g_front_1_u_front__f_t2[227]
    DIRECTION OUTPUT ;
    USE SIGNAL ;
    PORT
      LAYER M4 ;
        RECT  215.808 105.468 216 105.492 ;
    END
  END g_front_1_u_front__f_t2[227]
  PIN g_front_1_u_front__f_t2[228]
    DIRECTION OUTPUT ;
    USE SIGNAL ;
    PORT
      LAYER M4 ;
        RECT  215.808 105.948 216 105.972 ;
    END
  END g_front_1_u_front__f_t2[228]
  PIN g_front_1_u_front__f_t2[229]
    DIRECTION OUTPUT ;
    USE SIGNAL ;
    PORT
      LAYER M4 ;
        RECT  215.808 106.38 216 106.404 ;
    END
  END g_front_1_u_front__f_t2[229]
  PIN g_front_1_u_front__f_t2[22]
    DIRECTION OUTPUT ;
    USE SIGNAL ;
    PORT
      LAYER M4 ;
        RECT  215.808 12.348 216 12.372 ;
    END
  END g_front_1_u_front__f_t2[22]
  PIN g_front_1_u_front__f_t2[230]
    DIRECTION OUTPUT ;
    USE SIGNAL ;
    PORT
      LAYER M4 ;
        RECT  215.808 106.86 216 106.884 ;
    END
  END g_front_1_u_front__f_t2[230]
  PIN g_front_1_u_front__f_t2[231]
    DIRECTION OUTPUT ;
    USE SIGNAL ;
    PORT
      LAYER M4 ;
        RECT  215.808 107.292 216 107.316 ;
    END
  END g_front_1_u_front__f_t2[231]
  PIN g_front_1_u_front__f_t2[232]
    DIRECTION OUTPUT ;
    USE SIGNAL ;
    PORT
      LAYER M4 ;
        RECT  215.808 107.772 216 107.796 ;
    END
  END g_front_1_u_front__f_t2[232]
  PIN g_front_1_u_front__f_t2[23]
    DIRECTION OUTPUT ;
    USE SIGNAL ;
    PORT
      LAYER M4 ;
        RECT  215.808 12.828 216 12.852 ;
    END
  END g_front_1_u_front__f_t2[23]
  PIN g_front_1_u_front__f_t2[24]
    DIRECTION OUTPUT ;
    USE SIGNAL ;
    PORT
      LAYER M4 ;
        RECT  215.808 13.26 216 13.284 ;
    END
  END g_front_1_u_front__f_t2[24]
  PIN g_front_1_u_front__f_t2[25]
    DIRECTION OUTPUT ;
    USE SIGNAL ;
    PORT
      LAYER M4 ;
        RECT  215.808 13.74 216 13.764 ;
    END
  END g_front_1_u_front__f_t2[25]
  PIN g_front_1_u_front__f_t2[26]
    DIRECTION OUTPUT ;
    USE SIGNAL ;
    PORT
      LAYER M4 ;
        RECT  215.808 14.172 216 14.196 ;
    END
  END g_front_1_u_front__f_t2[26]
  PIN g_front_1_u_front__f_t2[27]
    DIRECTION OUTPUT ;
    USE SIGNAL ;
    PORT
      LAYER M4 ;
        RECT  215.808 14.652 216 14.676 ;
    END
  END g_front_1_u_front__f_t2[27]
  PIN g_front_1_u_front__f_t2[28]
    DIRECTION OUTPUT ;
    USE SIGNAL ;
    PORT
      LAYER M4 ;
        RECT  215.808 15.084 216 15.108 ;
    END
  END g_front_1_u_front__f_t2[28]
  PIN g_front_1_u_front__f_t2[29]
    DIRECTION OUTPUT ;
    USE SIGNAL ;
    PORT
      LAYER M4 ;
        RECT  215.808 15.564 216 15.588 ;
    END
  END g_front_1_u_front__f_t2[29]
  PIN g_front_1_u_front__f_t2[2]
    DIRECTION OUTPUT ;
    USE SIGNAL ;
    PORT
      LAYER M4 ;
        RECT  215.808 3.276 216 3.3 ;
    END
  END g_front_1_u_front__f_t2[2]
  PIN g_front_1_u_front__f_t2[30]
    DIRECTION OUTPUT ;
    USE SIGNAL ;
    PORT
      LAYER M4 ;
        RECT  215.808 15.996 216 16.02 ;
    END
  END g_front_1_u_front__f_t2[30]
  PIN g_front_1_u_front__f_t2[31]
    DIRECTION OUTPUT ;
    USE SIGNAL ;
    PORT
      LAYER M4 ;
        RECT  215.808 16.476 216 16.5 ;
    END
  END g_front_1_u_front__f_t2[31]
  PIN g_front_1_u_front__f_t2[32]
    DIRECTION OUTPUT ;
    USE SIGNAL ;
    PORT
      LAYER M4 ;
        RECT  215.808 16.908 216 16.932 ;
    END
  END g_front_1_u_front__f_t2[32]
  PIN g_front_1_u_front__f_t2[33]
    DIRECTION OUTPUT ;
    USE SIGNAL ;
    PORT
      LAYER M4 ;
        RECT  215.808 17.388 216 17.412 ;
    END
  END g_front_1_u_front__f_t2[33]
  PIN g_front_1_u_front__f_t2[34]
    DIRECTION OUTPUT ;
    USE SIGNAL ;
    PORT
      LAYER M4 ;
        RECT  215.808 17.82 216 17.844 ;
    END
  END g_front_1_u_front__f_t2[34]
  PIN g_front_1_u_front__f_t2[35]
    DIRECTION OUTPUT ;
    USE SIGNAL ;
    PORT
      LAYER M4 ;
        RECT  215.808 18.252 216 18.276 ;
    END
  END g_front_1_u_front__f_t2[35]
  PIN g_front_1_u_front__f_t2[36]
    DIRECTION OUTPUT ;
    USE SIGNAL ;
    PORT
      LAYER M4 ;
        RECT  215.808 18.732 216 18.756 ;
    END
  END g_front_1_u_front__f_t2[36]
  PIN g_front_1_u_front__f_t2[37]
    DIRECTION OUTPUT ;
    USE SIGNAL ;
    PORT
      LAYER M4 ;
        RECT  215.808 19.164 216 19.188 ;
    END
  END g_front_1_u_front__f_t2[37]
  PIN g_front_1_u_front__f_t2[38]
    DIRECTION OUTPUT ;
    USE SIGNAL ;
    PORT
      LAYER M4 ;
        RECT  215.808 19.644 216 19.668 ;
    END
  END g_front_1_u_front__f_t2[38]
  PIN g_front_1_u_front__f_t2[39]
    DIRECTION OUTPUT ;
    USE SIGNAL ;
    PORT
      LAYER M4 ;
        RECT  215.808 20.076 216 20.1 ;
    END
  END g_front_1_u_front__f_t2[39]
  PIN g_front_1_u_front__f_t2[3]
    DIRECTION OUTPUT ;
    USE SIGNAL ;
    PORT
      LAYER M4 ;
        RECT  215.808 3.756 216 3.78 ;
    END
  END g_front_1_u_front__f_t2[3]
  PIN g_front_1_u_front__f_t2[40]
    DIRECTION OUTPUT ;
    USE SIGNAL ;
    PORT
      LAYER M4 ;
        RECT  215.808 20.556 216 20.58 ;
    END
  END g_front_1_u_front__f_t2[40]
  PIN g_front_1_u_front__f_t2[41]
    DIRECTION OUTPUT ;
    USE SIGNAL ;
    PORT
      LAYER M4 ;
        RECT  215.808 20.988 216 21.012 ;
    END
  END g_front_1_u_front__f_t2[41]
  PIN g_front_1_u_front__f_t2[42]
    DIRECTION OUTPUT ;
    USE SIGNAL ;
    PORT
      LAYER M4 ;
        RECT  215.808 21.468 216 21.492 ;
    END
  END g_front_1_u_front__f_t2[42]
  PIN g_front_1_u_front__f_t2[43]
    DIRECTION OUTPUT ;
    USE SIGNAL ;
    PORT
      LAYER M4 ;
        RECT  215.808 21.9 216 21.924 ;
    END
  END g_front_1_u_front__f_t2[43]
  PIN g_front_1_u_front__f_t2[44]
    DIRECTION OUTPUT ;
    USE SIGNAL ;
    PORT
      LAYER M4 ;
        RECT  215.808 22.38 216 22.404 ;
    END
  END g_front_1_u_front__f_t2[44]
  PIN g_front_1_u_front__f_t2[45]
    DIRECTION OUTPUT ;
    USE SIGNAL ;
    PORT
      LAYER M4 ;
        RECT  215.808 22.812 216 22.836 ;
    END
  END g_front_1_u_front__f_t2[45]
  PIN g_front_1_u_front__f_t2[46]
    DIRECTION OUTPUT ;
    USE SIGNAL ;
    PORT
      LAYER M4 ;
        RECT  215.808 23.292 216 23.316 ;
    END
  END g_front_1_u_front__f_t2[46]
  PIN g_front_1_u_front__f_t2[47]
    DIRECTION OUTPUT ;
    USE SIGNAL ;
    PORT
      LAYER M4 ;
        RECT  215.808 23.724 216 23.748 ;
    END
  END g_front_1_u_front__f_t2[47]
  PIN g_front_1_u_front__f_t2[48]
    DIRECTION OUTPUT ;
    USE SIGNAL ;
    PORT
      LAYER M4 ;
        RECT  215.808 24.156 216 24.18 ;
    END
  END g_front_1_u_front__f_t2[48]
  PIN g_front_1_u_front__f_t2[49]
    DIRECTION OUTPUT ;
    USE SIGNAL ;
    PORT
      LAYER M4 ;
        RECT  215.808 24.636 216 24.66 ;
    END
  END g_front_1_u_front__f_t2[49]
  PIN g_front_1_u_front__f_t2[4]
    DIRECTION OUTPUT ;
    USE SIGNAL ;
    PORT
      LAYER M4 ;
        RECT  215.808 4.188 216 4.212 ;
    END
  END g_front_1_u_front__f_t2[4]
  PIN g_front_1_u_front__f_t2[50]
    DIRECTION OUTPUT ;
    USE SIGNAL ;
    PORT
      LAYER M4 ;
        RECT  215.808 25.068 216 25.092 ;
    END
  END g_front_1_u_front__f_t2[50]
  PIN g_front_1_u_front__f_t2[51]
    DIRECTION OUTPUT ;
    USE SIGNAL ;
    PORT
      LAYER M4 ;
        RECT  215.808 25.548 216 25.572 ;
    END
  END g_front_1_u_front__f_t2[51]
  PIN g_front_1_u_front__f_t2[52]
    DIRECTION OUTPUT ;
    USE SIGNAL ;
    PORT
      LAYER M4 ;
        RECT  215.808 25.98 216 26.004 ;
    END
  END g_front_1_u_front__f_t2[52]
  PIN g_front_1_u_front__f_t2[53]
    DIRECTION OUTPUT ;
    USE SIGNAL ;
    PORT
      LAYER M4 ;
        RECT  215.808 26.46 216 26.484 ;
    END
  END g_front_1_u_front__f_t2[53]
  PIN g_front_1_u_front__f_t2[54]
    DIRECTION OUTPUT ;
    USE SIGNAL ;
    PORT
      LAYER M4 ;
        RECT  215.808 26.892 216 26.916 ;
    END
  END g_front_1_u_front__f_t2[54]
  PIN g_front_1_u_front__f_t2[55]
    DIRECTION OUTPUT ;
    USE SIGNAL ;
    PORT
      LAYER M4 ;
        RECT  215.808 27.372 216 27.396 ;
    END
  END g_front_1_u_front__f_t2[55]
  PIN g_front_1_u_front__f_t2[56]
    DIRECTION OUTPUT ;
    USE SIGNAL ;
    PORT
      LAYER M4 ;
        RECT  215.808 27.804 216 27.828 ;
    END
  END g_front_1_u_front__f_t2[56]
  PIN g_front_1_u_front__f_t2[57]
    DIRECTION OUTPUT ;
    USE SIGNAL ;
    PORT
      LAYER M4 ;
        RECT  215.808 28.284 216 28.308 ;
    END
  END g_front_1_u_front__f_t2[57]
  PIN g_front_1_u_front__f_t2[58]
    DIRECTION OUTPUT ;
    USE SIGNAL ;
    PORT
      LAYER M4 ;
        RECT  215.808 28.716 216 28.74 ;
    END
  END g_front_1_u_front__f_t2[58]
  PIN g_front_1_u_front__f_t2[59]
    DIRECTION OUTPUT ;
    USE SIGNAL ;
    PORT
      LAYER M4 ;
        RECT  215.808 29.196 216 29.22 ;
    END
  END g_front_1_u_front__f_t2[59]
  PIN g_front_1_u_front__f_t2[5]
    DIRECTION OUTPUT ;
    USE SIGNAL ;
    PORT
      LAYER M4 ;
        RECT  215.808 4.668 216 4.692 ;
    END
  END g_front_1_u_front__f_t2[5]
  PIN g_front_1_u_front__f_t2[60]
    DIRECTION OUTPUT ;
    USE SIGNAL ;
    PORT
      LAYER M4 ;
        RECT  215.808 29.628 216 29.652 ;
    END
  END g_front_1_u_front__f_t2[60]
  PIN g_front_1_u_front__f_t2[61]
    DIRECTION OUTPUT ;
    USE SIGNAL ;
    PORT
      LAYER M4 ;
        RECT  215.808 30.108 216 30.132 ;
    END
  END g_front_1_u_front__f_t2[61]
  PIN g_front_1_u_front__f_t2[62]
    DIRECTION OUTPUT ;
    USE SIGNAL ;
    PORT
      LAYER M4 ;
        RECT  215.808 30.54 216 30.564 ;
    END
  END g_front_1_u_front__f_t2[62]
  PIN g_front_1_u_front__f_t2[63]
    DIRECTION OUTPUT ;
    USE SIGNAL ;
    PORT
      LAYER M4 ;
        RECT  215.808 30.972 216 30.996 ;
    END
  END g_front_1_u_front__f_t2[63]
  PIN g_front_1_u_front__f_t2[64]
    DIRECTION OUTPUT ;
    USE SIGNAL ;
    PORT
      LAYER M4 ;
        RECT  215.808 31.452 216 31.476 ;
    END
  END g_front_1_u_front__f_t2[64]
  PIN g_front_1_u_front__f_t2[65]
    DIRECTION OUTPUT ;
    USE SIGNAL ;
    PORT
      LAYER M4 ;
        RECT  215.808 31.884 216 31.908 ;
    END
  END g_front_1_u_front__f_t2[65]
  PIN g_front_1_u_front__f_t2[66]
    DIRECTION OUTPUT ;
    USE SIGNAL ;
    PORT
      LAYER M4 ;
        RECT  215.808 32.364 216 32.388 ;
    END
  END g_front_1_u_front__f_t2[66]
  PIN g_front_1_u_front__f_t2[67]
    DIRECTION OUTPUT ;
    USE SIGNAL ;
    PORT
      LAYER M4 ;
        RECT  215.808 32.796 216 32.82 ;
    END
  END g_front_1_u_front__f_t2[67]
  PIN g_front_1_u_front__f_t2[68]
    DIRECTION OUTPUT ;
    USE SIGNAL ;
    PORT
      LAYER M4 ;
        RECT  215.808 33.276 216 33.3 ;
    END
  END g_front_1_u_front__f_t2[68]
  PIN g_front_1_u_front__f_t2[69]
    DIRECTION OUTPUT ;
    USE SIGNAL ;
    PORT
      LAYER M4 ;
        RECT  215.808 33.708 216 33.732 ;
    END
  END g_front_1_u_front__f_t2[69]
  PIN g_front_1_u_front__f_t2[6]
    DIRECTION OUTPUT ;
    USE SIGNAL ;
    PORT
      LAYER M4 ;
        RECT  215.808 5.1 216 5.124 ;
    END
  END g_front_1_u_front__f_t2[6]
  PIN g_front_1_u_front__f_t2[70]
    DIRECTION OUTPUT ;
    USE SIGNAL ;
    PORT
      LAYER M4 ;
        RECT  215.808 34.188 216 34.212 ;
    END
  END g_front_1_u_front__f_t2[70]
  PIN g_front_1_u_front__f_t2[71]
    DIRECTION OUTPUT ;
    USE SIGNAL ;
    PORT
      LAYER M4 ;
        RECT  215.808 34.62 216 34.644 ;
    END
  END g_front_1_u_front__f_t2[71]
  PIN g_front_1_u_front__f_t2[72]
    DIRECTION OUTPUT ;
    USE SIGNAL ;
    PORT
      LAYER M4 ;
        RECT  215.808 35.1 216 35.124 ;
    END
  END g_front_1_u_front__f_t2[72]
  PIN g_front_1_u_front__f_t2[73]
    DIRECTION OUTPUT ;
    USE SIGNAL ;
    PORT
      LAYER M4 ;
        RECT  215.808 35.532 216 35.556 ;
    END
  END g_front_1_u_front__f_t2[73]
  PIN g_front_1_u_front__f_t2[74]
    DIRECTION OUTPUT ;
    USE SIGNAL ;
    PORT
      LAYER M4 ;
        RECT  215.808 36.012 216 36.036 ;
    END
  END g_front_1_u_front__f_t2[74]
  PIN g_front_1_u_front__f_t2[75]
    DIRECTION OUTPUT ;
    USE SIGNAL ;
    PORT
      LAYER M4 ;
        RECT  215.808 36.444 216 36.468 ;
    END
  END g_front_1_u_front__f_t2[75]
  PIN g_front_1_u_front__f_t2[76]
    DIRECTION OUTPUT ;
    USE SIGNAL ;
    PORT
      LAYER M4 ;
        RECT  215.808 36.876 216 36.9 ;
    END
  END g_front_1_u_front__f_t2[76]
  PIN g_front_1_u_front__f_t2[77]
    DIRECTION OUTPUT ;
    USE SIGNAL ;
    PORT
      LAYER M4 ;
        RECT  215.808 37.356 216 37.38 ;
    END
  END g_front_1_u_front__f_t2[77]
  PIN g_front_1_u_front__f_t2[78]
    DIRECTION OUTPUT ;
    USE SIGNAL ;
    PORT
      LAYER M4 ;
        RECT  215.808 37.788 216 37.812 ;
    END
  END g_front_1_u_front__f_t2[78]
  PIN g_front_1_u_front__f_t2[79]
    DIRECTION OUTPUT ;
    USE SIGNAL ;
    PORT
      LAYER M4 ;
        RECT  215.808 38.268 216 38.292 ;
    END
  END g_front_1_u_front__f_t2[79]
  PIN g_front_1_u_front__f_t2[7]
    DIRECTION OUTPUT ;
    USE SIGNAL ;
    PORT
      LAYER M4 ;
        RECT  215.808 5.532 216 5.556 ;
    END
  END g_front_1_u_front__f_t2[7]
  PIN g_front_1_u_front__f_t2[80]
    DIRECTION OUTPUT ;
    USE SIGNAL ;
    PORT
      LAYER M4 ;
        RECT  215.808 38.7 216 38.724 ;
    END
  END g_front_1_u_front__f_t2[80]
  PIN g_front_1_u_front__f_t2[81]
    DIRECTION OUTPUT ;
    USE SIGNAL ;
    PORT
      LAYER M4 ;
        RECT  215.808 39.18 216 39.204 ;
    END
  END g_front_1_u_front__f_t2[81]
  PIN g_front_1_u_front__f_t2[82]
    DIRECTION OUTPUT ;
    USE SIGNAL ;
    PORT
      LAYER M4 ;
        RECT  215.808 39.612 216 39.636 ;
    END
  END g_front_1_u_front__f_t2[82]
  PIN g_front_1_u_front__f_t2[83]
    DIRECTION OUTPUT ;
    USE SIGNAL ;
    PORT
      LAYER M4 ;
        RECT  215.808 40.092 216 40.116 ;
    END
  END g_front_1_u_front__f_t2[83]
  PIN g_front_1_u_front__f_t2[84]
    DIRECTION OUTPUT ;
    USE SIGNAL ;
    PORT
      LAYER M4 ;
        RECT  215.808 40.524 216 40.548 ;
    END
  END g_front_1_u_front__f_t2[84]
  PIN g_front_1_u_front__f_t2[85]
    DIRECTION OUTPUT ;
    USE SIGNAL ;
    PORT
      LAYER M4 ;
        RECT  215.808 41.004 216 41.028 ;
    END
  END g_front_1_u_front__f_t2[85]
  PIN g_front_1_u_front__f_t2[86]
    DIRECTION OUTPUT ;
    USE SIGNAL ;
    PORT
      LAYER M4 ;
        RECT  215.808 41.436 216 41.46 ;
    END
  END g_front_1_u_front__f_t2[86]
  PIN g_front_1_u_front__f_t2[87]
    DIRECTION OUTPUT ;
    USE SIGNAL ;
    PORT
      LAYER M4 ;
        RECT  215.808 41.916 216 41.94 ;
    END
  END g_front_1_u_front__f_t2[87]
  PIN g_front_1_u_front__f_t2[88]
    DIRECTION OUTPUT ;
    USE SIGNAL ;
    PORT
      LAYER M4 ;
        RECT  215.808 42.348 216 42.372 ;
    END
  END g_front_1_u_front__f_t2[88]
  PIN g_front_1_u_front__f_t2[89]
    DIRECTION OUTPUT ;
    USE SIGNAL ;
    PORT
      LAYER M4 ;
        RECT  215.808 42.78 216 42.804 ;
    END
  END g_front_1_u_front__f_t2[89]
  PIN g_front_1_u_front__f_t2[8]
    DIRECTION OUTPUT ;
    USE SIGNAL ;
    PORT
      LAYER M4 ;
        RECT  215.808 6.012 216 6.036 ;
    END
  END g_front_1_u_front__f_t2[8]
  PIN g_front_1_u_front__f_t2[90]
    DIRECTION OUTPUT ;
    USE SIGNAL ;
    PORT
      LAYER M4 ;
        RECT  215.808 43.26 216 43.284 ;
    END
  END g_front_1_u_front__f_t2[90]
  PIN g_front_1_u_front__f_t2[91]
    DIRECTION OUTPUT ;
    USE SIGNAL ;
    PORT
      LAYER M4 ;
        RECT  215.808 43.692 216 43.716 ;
    END
  END g_front_1_u_front__f_t2[91]
  PIN g_front_1_u_front__f_t2[92]
    DIRECTION OUTPUT ;
    USE SIGNAL ;
    PORT
      LAYER M4 ;
        RECT  215.808 44.172 216 44.196 ;
    END
  END g_front_1_u_front__f_t2[92]
  PIN g_front_1_u_front__f_t2[93]
    DIRECTION OUTPUT ;
    USE SIGNAL ;
    PORT
      LAYER M4 ;
        RECT  215.808 44.604 216 44.628 ;
    END
  END g_front_1_u_front__f_t2[93]
  PIN g_front_1_u_front__f_t2[94]
    DIRECTION OUTPUT ;
    USE SIGNAL ;
    PORT
      LAYER M4 ;
        RECT  215.808 45.084 216 45.108 ;
    END
  END g_front_1_u_front__f_t2[94]
  PIN g_front_1_u_front__f_t2[95]
    DIRECTION OUTPUT ;
    USE SIGNAL ;
    PORT
      LAYER M4 ;
        RECT  215.808 45.516 216 45.54 ;
    END
  END g_front_1_u_front__f_t2[95]
  PIN g_front_1_u_front__f_t2[96]
    DIRECTION OUTPUT ;
    USE SIGNAL ;
    PORT
      LAYER M4 ;
        RECT  215.808 45.996 216 46.02 ;
    END
  END g_front_1_u_front__f_t2[96]
  PIN g_front_1_u_front__f_t2[97]
    DIRECTION OUTPUT ;
    USE SIGNAL ;
    PORT
      LAYER M4 ;
        RECT  215.808 46.428 216 46.452 ;
    END
  END g_front_1_u_front__f_t2[97]
  PIN g_front_1_u_front__f_t2[98]
    DIRECTION OUTPUT ;
    USE SIGNAL ;
    PORT
      LAYER M4 ;
        RECT  215.808 46.908 216 46.932 ;
    END
  END g_front_1_u_front__f_t2[98]
  PIN g_front_1_u_front__f_t2[99]
    DIRECTION OUTPUT ;
    USE SIGNAL ;
    PORT
      LAYER M4 ;
        RECT  215.808 47.34 216 47.364 ;
    END
  END g_front_1_u_front__f_t2[99]
  PIN g_front_1_u_front__f_t2[9]
    DIRECTION OUTPUT ;
    USE SIGNAL ;
    PORT
      LAYER M4 ;
        RECT  215.808 6.444 216 6.468 ;
    END
  END g_front_1_u_front__f_t2[9]
  PIN g_front_1_u_front__f_t3[0]
    DIRECTION OUTPUT ;
    USE SIGNAL ;
    PORT
      LAYER M4 ;
        RECT  215.808 108.204 216 108.228 ;
    END
  END g_front_1_u_front__f_t3[0]
  PIN g_front_1_u_front__f_t3[100]
    DIRECTION OUTPUT ;
    USE SIGNAL ;
    PORT
      LAYER M4 ;
        RECT  215.808 153.66 216 153.684 ;
    END
  END g_front_1_u_front__f_t3[100]
  PIN g_front_1_u_front__f_t3[101]
    DIRECTION OUTPUT ;
    USE SIGNAL ;
    PORT
      LAYER M4 ;
        RECT  215.808 154.092 216 154.116 ;
    END
  END g_front_1_u_front__f_t3[101]
  PIN g_front_1_u_front__f_t3[102]
    DIRECTION OUTPUT ;
    USE SIGNAL ;
    PORT
      LAYER M4 ;
        RECT  215.808 154.572 216 154.596 ;
    END
  END g_front_1_u_front__f_t3[102]
  PIN g_front_1_u_front__f_t3[103]
    DIRECTION OUTPUT ;
    USE SIGNAL ;
    PORT
      LAYER M4 ;
        RECT  215.808 155.004 216 155.028 ;
    END
  END g_front_1_u_front__f_t3[103]
  PIN g_front_1_u_front__f_t3[104]
    DIRECTION OUTPUT ;
    USE SIGNAL ;
    PORT
      LAYER M4 ;
        RECT  215.808 155.436 216 155.46 ;
    END
  END g_front_1_u_front__f_t3[104]
  PIN g_front_1_u_front__f_t3[105]
    DIRECTION OUTPUT ;
    USE SIGNAL ;
    PORT
      LAYER M4 ;
        RECT  215.808 155.916 216 155.94 ;
    END
  END g_front_1_u_front__f_t3[105]
  PIN g_front_1_u_front__f_t3[106]
    DIRECTION OUTPUT ;
    USE SIGNAL ;
    PORT
      LAYER M4 ;
        RECT  215.808 156.348 216 156.372 ;
    END
  END g_front_1_u_front__f_t3[106]
  PIN g_front_1_u_front__f_t3[107]
    DIRECTION OUTPUT ;
    USE SIGNAL ;
    PORT
      LAYER M4 ;
        RECT  215.808 156.828 216 156.852 ;
    END
  END g_front_1_u_front__f_t3[107]
  PIN g_front_1_u_front__f_t3[108]
    DIRECTION OUTPUT ;
    USE SIGNAL ;
    PORT
      LAYER M4 ;
        RECT  215.808 157.26 216 157.284 ;
    END
  END g_front_1_u_front__f_t3[108]
  PIN g_front_1_u_front__f_t3[109]
    DIRECTION OUTPUT ;
    USE SIGNAL ;
    PORT
      LAYER M4 ;
        RECT  215.808 157.74 216 157.764 ;
    END
  END g_front_1_u_front__f_t3[109]
  PIN g_front_1_u_front__f_t3[10]
    DIRECTION OUTPUT ;
    USE SIGNAL ;
    PORT
      LAYER M4 ;
        RECT  215.808 112.764 216 112.788 ;
    END
  END g_front_1_u_front__f_t3[10]
  PIN g_front_1_u_front__f_t3[110]
    DIRECTION OUTPUT ;
    USE SIGNAL ;
    PORT
      LAYER M4 ;
        RECT  215.808 158.172 216 158.196 ;
    END
  END g_front_1_u_front__f_t3[110]
  PIN g_front_1_u_front__f_t3[111]
    DIRECTION OUTPUT ;
    USE SIGNAL ;
    PORT
      LAYER M4 ;
        RECT  215.808 158.652 216 158.676 ;
    END
  END g_front_1_u_front__f_t3[111]
  PIN g_front_1_u_front__f_t3[112]
    DIRECTION OUTPUT ;
    USE SIGNAL ;
    PORT
      LAYER M4 ;
        RECT  215.808 159.084 216 159.108 ;
    END
  END g_front_1_u_front__f_t3[112]
  PIN g_front_1_u_front__f_t3[113]
    DIRECTION OUTPUT ;
    USE SIGNAL ;
    PORT
      LAYER M4 ;
        RECT  215.808 159.564 216 159.588 ;
    END
  END g_front_1_u_front__f_t3[113]
  PIN g_front_1_u_front__f_t3[114]
    DIRECTION OUTPUT ;
    USE SIGNAL ;
    PORT
      LAYER M4 ;
        RECT  215.808 159.996 216 160.02 ;
    END
  END g_front_1_u_front__f_t3[114]
  PIN g_front_1_u_front__f_t3[115]
    DIRECTION OUTPUT ;
    USE SIGNAL ;
    PORT
      LAYER M4 ;
        RECT  215.808 160.476 216 160.5 ;
    END
  END g_front_1_u_front__f_t3[115]
  PIN g_front_1_u_front__f_t3[116]
    DIRECTION OUTPUT ;
    USE SIGNAL ;
    PORT
      LAYER M4 ;
        RECT  215.808 160.908 216 160.932 ;
    END
  END g_front_1_u_front__f_t3[116]
  PIN g_front_1_u_front__f_t3[117]
    DIRECTION OUTPUT ;
    USE SIGNAL ;
    PORT
      LAYER M4 ;
        RECT  215.808 161.34 216 161.364 ;
    END
  END g_front_1_u_front__f_t3[117]
  PIN g_front_1_u_front__f_t3[118]
    DIRECTION OUTPUT ;
    USE SIGNAL ;
    PORT
      LAYER M4 ;
        RECT  215.808 161.82 216 161.844 ;
    END
  END g_front_1_u_front__f_t3[118]
  PIN g_front_1_u_front__f_t3[119]
    DIRECTION OUTPUT ;
    USE SIGNAL ;
    PORT
      LAYER M4 ;
        RECT  215.808 162.252 216 162.276 ;
    END
  END g_front_1_u_front__f_t3[119]
  PIN g_front_1_u_front__f_t3[11]
    DIRECTION OUTPUT ;
    USE SIGNAL ;
    PORT
      LAYER M4 ;
        RECT  215.808 113.196 216 113.22 ;
    END
  END g_front_1_u_front__f_t3[11]
  PIN g_front_1_u_front__f_t3[120]
    DIRECTION OUTPUT ;
    USE SIGNAL ;
    PORT
      LAYER M4 ;
        RECT  215.808 162.732 216 162.756 ;
    END
  END g_front_1_u_front__f_t3[120]
  PIN g_front_1_u_front__f_t3[121]
    DIRECTION OUTPUT ;
    USE SIGNAL ;
    PORT
      LAYER M4 ;
        RECT  215.808 163.164 216 163.188 ;
    END
  END g_front_1_u_front__f_t3[121]
  PIN g_front_1_u_front__f_t3[122]
    DIRECTION OUTPUT ;
    USE SIGNAL ;
    PORT
      LAYER M4 ;
        RECT  215.808 163.644 216 163.668 ;
    END
  END g_front_1_u_front__f_t3[122]
  PIN g_front_1_u_front__f_t3[123]
    DIRECTION OUTPUT ;
    USE SIGNAL ;
    PORT
      LAYER M4 ;
        RECT  215.808 164.076 216 164.1 ;
    END
  END g_front_1_u_front__f_t3[123]
  PIN g_front_1_u_front__f_t3[124]
    DIRECTION OUTPUT ;
    USE SIGNAL ;
    PORT
      LAYER M4 ;
        RECT  215.808 164.556 216 164.58 ;
    END
  END g_front_1_u_front__f_t3[124]
  PIN g_front_1_u_front__f_t3[125]
    DIRECTION OUTPUT ;
    USE SIGNAL ;
    PORT
      LAYER M4 ;
        RECT  215.808 164.988 216 165.012 ;
    END
  END g_front_1_u_front__f_t3[125]
  PIN g_front_1_u_front__f_t3[126]
    DIRECTION OUTPUT ;
    USE SIGNAL ;
    PORT
      LAYER M4 ;
        RECT  215.808 165.468 216 165.492 ;
    END
  END g_front_1_u_front__f_t3[126]
  PIN g_front_1_u_front__f_t3[127]
    DIRECTION OUTPUT ;
    USE SIGNAL ;
    PORT
      LAYER M4 ;
        RECT  215.808 165.9 216 165.924 ;
    END
  END g_front_1_u_front__f_t3[127]
  PIN g_front_1_u_front__f_t3[128]
    DIRECTION OUTPUT ;
    USE SIGNAL ;
    PORT
      LAYER M4 ;
        RECT  215.808 166.38 216 166.404 ;
    END
  END g_front_1_u_front__f_t3[128]
  PIN g_front_1_u_front__f_t3[129]
    DIRECTION OUTPUT ;
    USE SIGNAL ;
    PORT
      LAYER M4 ;
        RECT  215.808 166.812 216 166.836 ;
    END
  END g_front_1_u_front__f_t3[129]
  PIN g_front_1_u_front__f_t3[12]
    DIRECTION OUTPUT ;
    USE SIGNAL ;
    PORT
      LAYER M4 ;
        RECT  215.808 113.676 216 113.7 ;
    END
  END g_front_1_u_front__f_t3[12]
  PIN g_front_1_u_front__f_t3[130]
    DIRECTION OUTPUT ;
    USE SIGNAL ;
    PORT
      LAYER M4 ;
        RECT  215.808 167.244 216 167.268 ;
    END
  END g_front_1_u_front__f_t3[130]
  PIN g_front_1_u_front__f_t3[131]
    DIRECTION OUTPUT ;
    USE SIGNAL ;
    PORT
      LAYER M4 ;
        RECT  215.808 167.724 216 167.748 ;
    END
  END g_front_1_u_front__f_t3[131]
  PIN g_front_1_u_front__f_t3[132]
    DIRECTION OUTPUT ;
    USE SIGNAL ;
    PORT
      LAYER M4 ;
        RECT  215.808 168.156 216 168.18 ;
    END
  END g_front_1_u_front__f_t3[132]
  PIN g_front_1_u_front__f_t3[133]
    DIRECTION OUTPUT ;
    USE SIGNAL ;
    PORT
      LAYER M4 ;
        RECT  215.808 168.636 216 168.66 ;
    END
  END g_front_1_u_front__f_t3[133]
  PIN g_front_1_u_front__f_t3[134]
    DIRECTION OUTPUT ;
    USE SIGNAL ;
    PORT
      LAYER M4 ;
        RECT  215.808 169.068 216 169.092 ;
    END
  END g_front_1_u_front__f_t3[134]
  PIN g_front_1_u_front__f_t3[135]
    DIRECTION OUTPUT ;
    USE SIGNAL ;
    PORT
      LAYER M4 ;
        RECT  215.808 169.548 216 169.572 ;
    END
  END g_front_1_u_front__f_t3[135]
  PIN g_front_1_u_front__f_t3[136]
    DIRECTION OUTPUT ;
    USE SIGNAL ;
    PORT
      LAYER M4 ;
        RECT  215.808 169.98 216 170.004 ;
    END
  END g_front_1_u_front__f_t3[136]
  PIN g_front_1_u_front__f_t3[137]
    DIRECTION OUTPUT ;
    USE SIGNAL ;
    PORT
      LAYER M4 ;
        RECT  215.808 170.46 216 170.484 ;
    END
  END g_front_1_u_front__f_t3[137]
  PIN g_front_1_u_front__f_t3[138]
    DIRECTION OUTPUT ;
    USE SIGNAL ;
    PORT
      LAYER M4 ;
        RECT  215.808 170.892 216 170.916 ;
    END
  END g_front_1_u_front__f_t3[138]
  PIN g_front_1_u_front__f_t3[139]
    DIRECTION OUTPUT ;
    USE SIGNAL ;
    PORT
      LAYER M4 ;
        RECT  215.808 171.372 216 171.396 ;
    END
  END g_front_1_u_front__f_t3[139]
  PIN g_front_1_u_front__f_t3[13]
    DIRECTION OUTPUT ;
    USE SIGNAL ;
    PORT
      LAYER M4 ;
        RECT  215.808 114.108 216 114.132 ;
    END
  END g_front_1_u_front__f_t3[13]
  PIN g_front_1_u_front__f_t3[140]
    DIRECTION OUTPUT ;
    USE SIGNAL ;
    PORT
      LAYER M4 ;
        RECT  215.808 171.804 216 171.828 ;
    END
  END g_front_1_u_front__f_t3[140]
  PIN g_front_1_u_front__f_t3[141]
    DIRECTION OUTPUT ;
    USE SIGNAL ;
    PORT
      LAYER M4 ;
        RECT  215.808 172.284 216 172.308 ;
    END
  END g_front_1_u_front__f_t3[141]
  PIN g_front_1_u_front__f_t3[142]
    DIRECTION OUTPUT ;
    USE SIGNAL ;
    PORT
      LAYER M4 ;
        RECT  215.808 172.716 216 172.74 ;
    END
  END g_front_1_u_front__f_t3[142]
  PIN g_front_1_u_front__f_t3[143]
    DIRECTION OUTPUT ;
    USE SIGNAL ;
    PORT
      LAYER M4 ;
        RECT  215.808 173.196 216 173.22 ;
    END
  END g_front_1_u_front__f_t3[143]
  PIN g_front_1_u_front__f_t3[144]
    DIRECTION OUTPUT ;
    USE SIGNAL ;
    PORT
      LAYER M4 ;
        RECT  215.808 173.628 216 173.652 ;
    END
  END g_front_1_u_front__f_t3[144]
  PIN g_front_1_u_front__f_t3[145]
    DIRECTION OUTPUT ;
    USE SIGNAL ;
    PORT
      LAYER M4 ;
        RECT  215.808 174.06 216 174.084 ;
    END
  END g_front_1_u_front__f_t3[145]
  PIN g_front_1_u_front__f_t3[146]
    DIRECTION OUTPUT ;
    USE SIGNAL ;
    PORT
      LAYER M4 ;
        RECT  215.808 174.54 216 174.564 ;
    END
  END g_front_1_u_front__f_t3[146]
  PIN g_front_1_u_front__f_t3[147]
    DIRECTION OUTPUT ;
    USE SIGNAL ;
    PORT
      LAYER M4 ;
        RECT  215.808 174.972 216 174.996 ;
    END
  END g_front_1_u_front__f_t3[147]
  PIN g_front_1_u_front__f_t3[148]
    DIRECTION OUTPUT ;
    USE SIGNAL ;
    PORT
      LAYER M4 ;
        RECT  215.808 175.452 216 175.476 ;
    END
  END g_front_1_u_front__f_t3[148]
  PIN g_front_1_u_front__f_t3[149]
    DIRECTION OUTPUT ;
    USE SIGNAL ;
    PORT
      LAYER M4 ;
        RECT  215.808 175.884 216 175.908 ;
    END
  END g_front_1_u_front__f_t3[149]
  PIN g_front_1_u_front__f_t3[14]
    DIRECTION OUTPUT ;
    USE SIGNAL ;
    PORT
      LAYER M4 ;
        RECT  215.808 114.588 216 114.612 ;
    END
  END g_front_1_u_front__f_t3[14]
  PIN g_front_1_u_front__f_t3[150]
    DIRECTION OUTPUT ;
    USE SIGNAL ;
    PORT
      LAYER M4 ;
        RECT  215.808 176.364 216 176.388 ;
    END
  END g_front_1_u_front__f_t3[150]
  PIN g_front_1_u_front__f_t3[151]
    DIRECTION OUTPUT ;
    USE SIGNAL ;
    PORT
      LAYER M4 ;
        RECT  215.808 176.796 216 176.82 ;
    END
  END g_front_1_u_front__f_t3[151]
  PIN g_front_1_u_front__f_t3[152]
    DIRECTION OUTPUT ;
    USE SIGNAL ;
    PORT
      LAYER M4 ;
        RECT  215.808 177.276 216 177.3 ;
    END
  END g_front_1_u_front__f_t3[152]
  PIN g_front_1_u_front__f_t3[153]
    DIRECTION OUTPUT ;
    USE SIGNAL ;
    PORT
      LAYER M4 ;
        RECT  215.808 177.708 216 177.732 ;
    END
  END g_front_1_u_front__f_t3[153]
  PIN g_front_1_u_front__f_t3[154]
    DIRECTION OUTPUT ;
    USE SIGNAL ;
    PORT
      LAYER M4 ;
        RECT  215.808 178.188 216 178.212 ;
    END
  END g_front_1_u_front__f_t3[154]
  PIN g_front_1_u_front__f_t3[155]
    DIRECTION OUTPUT ;
    USE SIGNAL ;
    PORT
      LAYER M4 ;
        RECT  215.808 178.62 216 178.644 ;
    END
  END g_front_1_u_front__f_t3[155]
  PIN g_front_1_u_front__f_t3[156]
    DIRECTION OUTPUT ;
    USE SIGNAL ;
    PORT
      LAYER M4 ;
        RECT  215.808 179.1 216 179.124 ;
    END
  END g_front_1_u_front__f_t3[156]
  PIN g_front_1_u_front__f_t3[157]
    DIRECTION OUTPUT ;
    USE SIGNAL ;
    PORT
      LAYER M4 ;
        RECT  215.808 179.532 216 179.556 ;
    END
  END g_front_1_u_front__f_t3[157]
  PIN g_front_1_u_front__f_t3[158]
    DIRECTION OUTPUT ;
    USE SIGNAL ;
    PORT
      LAYER M4 ;
        RECT  215.808 179.964 216 179.988 ;
    END
  END g_front_1_u_front__f_t3[158]
  PIN g_front_1_u_front__f_t3[159]
    DIRECTION OUTPUT ;
    USE SIGNAL ;
    PORT
      LAYER M4 ;
        RECT  215.808 180.444 216 180.468 ;
    END
  END g_front_1_u_front__f_t3[159]
  PIN g_front_1_u_front__f_t3[15]
    DIRECTION OUTPUT ;
    USE SIGNAL ;
    PORT
      LAYER M4 ;
        RECT  215.808 115.02 216 115.044 ;
    END
  END g_front_1_u_front__f_t3[15]
  PIN g_front_1_u_front__f_t3[160]
    DIRECTION OUTPUT ;
    USE SIGNAL ;
    PORT
      LAYER M4 ;
        RECT  215.808 180.876 216 180.9 ;
    END
  END g_front_1_u_front__f_t3[160]
  PIN g_front_1_u_front__f_t3[161]
    DIRECTION OUTPUT ;
    USE SIGNAL ;
    PORT
      LAYER M4 ;
        RECT  215.808 181.356 216 181.38 ;
    END
  END g_front_1_u_front__f_t3[161]
  PIN g_front_1_u_front__f_t3[162]
    DIRECTION OUTPUT ;
    USE SIGNAL ;
    PORT
      LAYER M4 ;
        RECT  215.808 181.788 216 181.812 ;
    END
  END g_front_1_u_front__f_t3[162]
  PIN g_front_1_u_front__f_t3[163]
    DIRECTION OUTPUT ;
    USE SIGNAL ;
    PORT
      LAYER M4 ;
        RECT  215.808 182.268 216 182.292 ;
    END
  END g_front_1_u_front__f_t3[163]
  PIN g_front_1_u_front__f_t3[164]
    DIRECTION OUTPUT ;
    USE SIGNAL ;
    PORT
      LAYER M4 ;
        RECT  215.808 182.7 216 182.724 ;
    END
  END g_front_1_u_front__f_t3[164]
  PIN g_front_1_u_front__f_t3[165]
    DIRECTION OUTPUT ;
    USE SIGNAL ;
    PORT
      LAYER M4 ;
        RECT  215.808 183.18 216 183.204 ;
    END
  END g_front_1_u_front__f_t3[165]
  PIN g_front_1_u_front__f_t3[166]
    DIRECTION OUTPUT ;
    USE SIGNAL ;
    PORT
      LAYER M4 ;
        RECT  215.808 183.612 216 183.636 ;
    END
  END g_front_1_u_front__f_t3[166]
  PIN g_front_1_u_front__f_t3[167]
    DIRECTION OUTPUT ;
    USE SIGNAL ;
    PORT
      LAYER M4 ;
        RECT  215.808 184.092 216 184.116 ;
    END
  END g_front_1_u_front__f_t3[167]
  PIN g_front_1_u_front__f_t3[168]
    DIRECTION OUTPUT ;
    USE SIGNAL ;
    PORT
      LAYER M4 ;
        RECT  215.808 184.524 216 184.548 ;
    END
  END g_front_1_u_front__f_t3[168]
  PIN g_front_1_u_front__f_t3[169]
    DIRECTION OUTPUT ;
    USE SIGNAL ;
    PORT
      LAYER M4 ;
        RECT  215.808 185.004 216 185.028 ;
    END
  END g_front_1_u_front__f_t3[169]
  PIN g_front_1_u_front__f_t3[16]
    DIRECTION OUTPUT ;
    USE SIGNAL ;
    PORT
      LAYER M4 ;
        RECT  215.808 115.5 216 115.524 ;
    END
  END g_front_1_u_front__f_t3[16]
  PIN g_front_1_u_front__f_t3[170]
    DIRECTION OUTPUT ;
    USE SIGNAL ;
    PORT
      LAYER M4 ;
        RECT  215.808 185.436 216 185.46 ;
    END
  END g_front_1_u_front__f_t3[170]
  PIN g_front_1_u_front__f_t3[171]
    DIRECTION OUTPUT ;
    USE SIGNAL ;
    PORT
      LAYER M4 ;
        RECT  215.808 185.868 216 185.892 ;
    END
  END g_front_1_u_front__f_t3[171]
  PIN g_front_1_u_front__f_t3[172]
    DIRECTION OUTPUT ;
    USE SIGNAL ;
    PORT
      LAYER M4 ;
        RECT  215.808 186.348 216 186.372 ;
    END
  END g_front_1_u_front__f_t3[172]
  PIN g_front_1_u_front__f_t3[173]
    DIRECTION OUTPUT ;
    USE SIGNAL ;
    PORT
      LAYER M4 ;
        RECT  215.808 186.78 216 186.804 ;
    END
  END g_front_1_u_front__f_t3[173]
  PIN g_front_1_u_front__f_t3[174]
    DIRECTION OUTPUT ;
    USE SIGNAL ;
    PORT
      LAYER M4 ;
        RECT  215.808 187.26 216 187.284 ;
    END
  END g_front_1_u_front__f_t3[174]
  PIN g_front_1_u_front__f_t3[175]
    DIRECTION OUTPUT ;
    USE SIGNAL ;
    PORT
      LAYER M4 ;
        RECT  215.808 187.692 216 187.716 ;
    END
  END g_front_1_u_front__f_t3[175]
  PIN g_front_1_u_front__f_t3[176]
    DIRECTION OUTPUT ;
    USE SIGNAL ;
    PORT
      LAYER M4 ;
        RECT  215.808 188.172 216 188.196 ;
    END
  END g_front_1_u_front__f_t3[176]
  PIN g_front_1_u_front__f_t3[177]
    DIRECTION OUTPUT ;
    USE SIGNAL ;
    PORT
      LAYER M4 ;
        RECT  215.808 188.604 216 188.628 ;
    END
  END g_front_1_u_front__f_t3[177]
  PIN g_front_1_u_front__f_t3[178]
    DIRECTION OUTPUT ;
    USE SIGNAL ;
    PORT
      LAYER M4 ;
        RECT  215.808 189.084 216 189.108 ;
    END
  END g_front_1_u_front__f_t3[178]
  PIN g_front_1_u_front__f_t3[179]
    DIRECTION OUTPUT ;
    USE SIGNAL ;
    PORT
      LAYER M4 ;
        RECT  215.808 189.516 216 189.54 ;
    END
  END g_front_1_u_front__f_t3[179]
  PIN g_front_1_u_front__f_t3[17]
    DIRECTION OUTPUT ;
    USE SIGNAL ;
    PORT
      LAYER M4 ;
        RECT  215.808 115.932 216 115.956 ;
    END
  END g_front_1_u_front__f_t3[17]
  PIN g_front_1_u_front__f_t3[180]
    DIRECTION OUTPUT ;
    USE SIGNAL ;
    PORT
      LAYER M4 ;
        RECT  215.808 189.996 216 190.02 ;
    END
  END g_front_1_u_front__f_t3[180]
  PIN g_front_1_u_front__f_t3[181]
    DIRECTION OUTPUT ;
    USE SIGNAL ;
    PORT
      LAYER M4 ;
        RECT  215.808 190.428 216 190.452 ;
    END
  END g_front_1_u_front__f_t3[181]
  PIN g_front_1_u_front__f_t3[182]
    DIRECTION OUTPUT ;
    USE SIGNAL ;
    PORT
      LAYER M4 ;
        RECT  215.808 190.908 216 190.932 ;
    END
  END g_front_1_u_front__f_t3[182]
  PIN g_front_1_u_front__f_t3[183]
    DIRECTION OUTPUT ;
    USE SIGNAL ;
    PORT
      LAYER M4 ;
        RECT  215.808 191.34 216 191.364 ;
    END
  END g_front_1_u_front__f_t3[183]
  PIN g_front_1_u_front__f_t3[184]
    DIRECTION OUTPUT ;
    USE SIGNAL ;
    PORT
      LAYER M4 ;
        RECT  215.808 191.82 216 191.844 ;
    END
  END g_front_1_u_front__f_t3[184]
  PIN g_front_1_u_front__f_t3[185]
    DIRECTION OUTPUT ;
    USE SIGNAL ;
    PORT
      LAYER M4 ;
        RECT  215.808 192.252 216 192.276 ;
    END
  END g_front_1_u_front__f_t3[185]
  PIN g_front_1_u_front__f_t3[186]
    DIRECTION OUTPUT ;
    USE SIGNAL ;
    PORT
      LAYER M4 ;
        RECT  215.808 192.684 216 192.708 ;
    END
  END g_front_1_u_front__f_t3[186]
  PIN g_front_1_u_front__f_t3[187]
    DIRECTION OUTPUT ;
    USE SIGNAL ;
    PORT
      LAYER M4 ;
        RECT  215.808 193.164 216 193.188 ;
    END
  END g_front_1_u_front__f_t3[187]
  PIN g_front_1_u_front__f_t3[188]
    DIRECTION OUTPUT ;
    USE SIGNAL ;
    PORT
      LAYER M4 ;
        RECT  215.808 193.596 216 193.62 ;
    END
  END g_front_1_u_front__f_t3[188]
  PIN g_front_1_u_front__f_t3[189]
    DIRECTION OUTPUT ;
    USE SIGNAL ;
    PORT
      LAYER M4 ;
        RECT  215.808 194.076 216 194.1 ;
    END
  END g_front_1_u_front__f_t3[189]
  PIN g_front_1_u_front__f_t3[18]
    DIRECTION OUTPUT ;
    USE SIGNAL ;
    PORT
      LAYER M4 ;
        RECT  215.808 116.412 216 116.436 ;
    END
  END g_front_1_u_front__f_t3[18]
  PIN g_front_1_u_front__f_t3[190]
    DIRECTION OUTPUT ;
    USE SIGNAL ;
    PORT
      LAYER M4 ;
        RECT  215.808 194.508 216 194.532 ;
    END
  END g_front_1_u_front__f_t3[190]
  PIN g_front_1_u_front__f_t3[191]
    DIRECTION OUTPUT ;
    USE SIGNAL ;
    PORT
      LAYER M4 ;
        RECT  215.808 194.988 216 195.012 ;
    END
  END g_front_1_u_front__f_t3[191]
  PIN g_front_1_u_front__f_t3[192]
    DIRECTION OUTPUT ;
    USE SIGNAL ;
    PORT
      LAYER M4 ;
        RECT  215.808 195.42 216 195.444 ;
    END
  END g_front_1_u_front__f_t3[192]
  PIN g_front_1_u_front__f_t3[193]
    DIRECTION OUTPUT ;
    USE SIGNAL ;
    PORT
      LAYER M4 ;
        RECT  215.808 195.9 216 195.924 ;
    END
  END g_front_1_u_front__f_t3[193]
  PIN g_front_1_u_front__f_t3[194]
    DIRECTION OUTPUT ;
    USE SIGNAL ;
    PORT
      LAYER M4 ;
        RECT  215.808 196.332 216 196.356 ;
    END
  END g_front_1_u_front__f_t3[194]
  PIN g_front_1_u_front__f_t3[195]
    DIRECTION OUTPUT ;
    USE SIGNAL ;
    PORT
      LAYER M4 ;
        RECT  215.808 196.812 216 196.836 ;
    END
  END g_front_1_u_front__f_t3[195]
  PIN g_front_1_u_front__f_t3[196]
    DIRECTION OUTPUT ;
    USE SIGNAL ;
    PORT
      LAYER M4 ;
        RECT  215.808 197.244 216 197.268 ;
    END
  END g_front_1_u_front__f_t3[196]
  PIN g_front_1_u_front__f_t3[197]
    DIRECTION OUTPUT ;
    USE SIGNAL ;
    PORT
      LAYER M4 ;
        RECT  215.808 197.724 216 197.748 ;
    END
  END g_front_1_u_front__f_t3[197]
  PIN g_front_1_u_front__f_t3[198]
    DIRECTION OUTPUT ;
    USE SIGNAL ;
    PORT
      LAYER M4 ;
        RECT  215.808 198.156 216 198.18 ;
    END
  END g_front_1_u_front__f_t3[198]
  PIN g_front_1_u_front__f_t3[199]
    DIRECTION OUTPUT ;
    USE SIGNAL ;
    PORT
      LAYER M4 ;
        RECT  215.808 198.588 216 198.612 ;
    END
  END g_front_1_u_front__f_t3[199]
  PIN g_front_1_u_front__f_t3[19]
    DIRECTION OUTPUT ;
    USE SIGNAL ;
    PORT
      LAYER M4 ;
        RECT  215.808 116.844 216 116.868 ;
    END
  END g_front_1_u_front__f_t3[19]
  PIN g_front_1_u_front__f_t3[1]
    DIRECTION OUTPUT ;
    USE SIGNAL ;
    PORT
      LAYER M4 ;
        RECT  215.808 108.684 216 108.708 ;
    END
  END g_front_1_u_front__f_t3[1]
  PIN g_front_1_u_front__f_t3[200]
    DIRECTION OUTPUT ;
    USE SIGNAL ;
    PORT
      LAYER M4 ;
        RECT  215.808 199.068 216 199.092 ;
    END
  END g_front_1_u_front__f_t3[200]
  PIN g_front_1_u_front__f_t3[201]
    DIRECTION OUTPUT ;
    USE SIGNAL ;
    PORT
      LAYER M4 ;
        RECT  215.808 199.5 216 199.524 ;
    END
  END g_front_1_u_front__f_t3[201]
  PIN g_front_1_u_front__f_t3[202]
    DIRECTION OUTPUT ;
    USE SIGNAL ;
    PORT
      LAYER M4 ;
        RECT  215.808 199.98 216 200.004 ;
    END
  END g_front_1_u_front__f_t3[202]
  PIN g_front_1_u_front__f_t3[203]
    DIRECTION OUTPUT ;
    USE SIGNAL ;
    PORT
      LAYER M4 ;
        RECT  215.808 200.412 216 200.436 ;
    END
  END g_front_1_u_front__f_t3[203]
  PIN g_front_1_u_front__f_t3[204]
    DIRECTION OUTPUT ;
    USE SIGNAL ;
    PORT
      LAYER M4 ;
        RECT  215.808 200.892 216 200.916 ;
    END
  END g_front_1_u_front__f_t3[204]
  PIN g_front_1_u_front__f_t3[205]
    DIRECTION OUTPUT ;
    USE SIGNAL ;
    PORT
      LAYER M4 ;
        RECT  215.808 201.324 216 201.348 ;
    END
  END g_front_1_u_front__f_t3[205]
  PIN g_front_1_u_front__f_t3[206]
    DIRECTION OUTPUT ;
    USE SIGNAL ;
    PORT
      LAYER M4 ;
        RECT  215.808 201.804 216 201.828 ;
    END
  END g_front_1_u_front__f_t3[206]
  PIN g_front_1_u_front__f_t3[207]
    DIRECTION OUTPUT ;
    USE SIGNAL ;
    PORT
      LAYER M4 ;
        RECT  215.808 202.236 216 202.26 ;
    END
  END g_front_1_u_front__f_t3[207]
  PIN g_front_1_u_front__f_t3[208]
    DIRECTION OUTPUT ;
    USE SIGNAL ;
    PORT
      LAYER M4 ;
        RECT  215.808 202.716 216 202.74 ;
    END
  END g_front_1_u_front__f_t3[208]
  PIN g_front_1_u_front__f_t3[209]
    DIRECTION OUTPUT ;
    USE SIGNAL ;
    PORT
      LAYER M4 ;
        RECT  215.808 203.148 216 203.172 ;
    END
  END g_front_1_u_front__f_t3[209]
  PIN g_front_1_u_front__f_t3[20]
    DIRECTION OUTPUT ;
    USE SIGNAL ;
    PORT
      LAYER M4 ;
        RECT  215.808 117.324 216 117.348 ;
    END
  END g_front_1_u_front__f_t3[20]
  PIN g_front_1_u_front__f_t3[210]
    DIRECTION OUTPUT ;
    USE SIGNAL ;
    PORT
      LAYER M4 ;
        RECT  215.808 203.628 216 203.652 ;
    END
  END g_front_1_u_front__f_t3[210]
  PIN g_front_1_u_front__f_t3[211]
    DIRECTION OUTPUT ;
    USE SIGNAL ;
    PORT
      LAYER M4 ;
        RECT  215.808 204.06 216 204.084 ;
    END
  END g_front_1_u_front__f_t3[211]
  PIN g_front_1_u_front__f_t3[212]
    DIRECTION OUTPUT ;
    USE SIGNAL ;
    PORT
      LAYER M4 ;
        RECT  215.808 204.492 216 204.516 ;
    END
  END g_front_1_u_front__f_t3[212]
  PIN g_front_1_u_front__f_t3[213]
    DIRECTION OUTPUT ;
    USE SIGNAL ;
    PORT
      LAYER M4 ;
        RECT  215.808 204.972 216 204.996 ;
    END
  END g_front_1_u_front__f_t3[213]
  PIN g_front_1_u_front__f_t3[214]
    DIRECTION OUTPUT ;
    USE SIGNAL ;
    PORT
      LAYER M4 ;
        RECT  215.808 205.404 216 205.428 ;
    END
  END g_front_1_u_front__f_t3[214]
  PIN g_front_1_u_front__f_t3[215]
    DIRECTION OUTPUT ;
    USE SIGNAL ;
    PORT
      LAYER M4 ;
        RECT  215.808 205.884 216 205.908 ;
    END
  END g_front_1_u_front__f_t3[215]
  PIN g_front_1_u_front__f_t3[216]
    DIRECTION OUTPUT ;
    USE SIGNAL ;
    PORT
      LAYER M4 ;
        RECT  215.808 206.316 216 206.34 ;
    END
  END g_front_1_u_front__f_t3[216]
  PIN g_front_1_u_front__f_t3[217]
    DIRECTION OUTPUT ;
    USE SIGNAL ;
    PORT
      LAYER M4 ;
        RECT  215.808 206.796 216 206.82 ;
    END
  END g_front_1_u_front__f_t3[217]
  PIN g_front_1_u_front__f_t3[218]
    DIRECTION OUTPUT ;
    USE SIGNAL ;
    PORT
      LAYER M4 ;
        RECT  215.808 207.228 216 207.252 ;
    END
  END g_front_1_u_front__f_t3[218]
  PIN g_front_1_u_front__f_t3[219]
    DIRECTION OUTPUT ;
    USE SIGNAL ;
    PORT
      LAYER M4 ;
        RECT  215.808 207.708 216 207.732 ;
    END
  END g_front_1_u_front__f_t3[219]
  PIN g_front_1_u_front__f_t3[21]
    DIRECTION OUTPUT ;
    USE SIGNAL ;
    PORT
      LAYER M4 ;
        RECT  215.808 117.756 216 117.78 ;
    END
  END g_front_1_u_front__f_t3[21]
  PIN g_front_1_u_front__f_t3[220]
    DIRECTION OUTPUT ;
    USE SIGNAL ;
    PORT
      LAYER M4 ;
        RECT  215.808 208.14 216 208.164 ;
    END
  END g_front_1_u_front__f_t3[220]
  PIN g_front_1_u_front__f_t3[221]
    DIRECTION OUTPUT ;
    USE SIGNAL ;
    PORT
      LAYER M4 ;
        RECT  215.808 208.62 216 208.644 ;
    END
  END g_front_1_u_front__f_t3[221]
  PIN g_front_1_u_front__f_t3[222]
    DIRECTION OUTPUT ;
    USE SIGNAL ;
    PORT
      LAYER M4 ;
        RECT  215.808 209.052 216 209.076 ;
    END
  END g_front_1_u_front__f_t3[222]
  PIN g_front_1_u_front__f_t3[223]
    DIRECTION OUTPUT ;
    USE SIGNAL ;
    PORT
      LAYER M4 ;
        RECT  215.808 209.532 216 209.556 ;
    END
  END g_front_1_u_front__f_t3[223]
  PIN g_front_1_u_front__f_t3[224]
    DIRECTION OUTPUT ;
    USE SIGNAL ;
    PORT
      LAYER M4 ;
        RECT  215.808 209.964 216 209.988 ;
    END
  END g_front_1_u_front__f_t3[224]
  PIN g_front_1_u_front__f_t3[225]
    DIRECTION OUTPUT ;
    USE SIGNAL ;
    PORT
      LAYER M4 ;
        RECT  215.808 210.444 216 210.468 ;
    END
  END g_front_1_u_front__f_t3[225]
  PIN g_front_1_u_front__f_t3[226]
    DIRECTION OUTPUT ;
    USE SIGNAL ;
    PORT
      LAYER M4 ;
        RECT  215.808 210.876 216 210.9 ;
    END
  END g_front_1_u_front__f_t3[226]
  PIN g_front_1_u_front__f_t3[227]
    DIRECTION OUTPUT ;
    USE SIGNAL ;
    PORT
      LAYER M4 ;
        RECT  215.808 211.308 216 211.332 ;
    END
  END g_front_1_u_front__f_t3[227]
  PIN g_front_1_u_front__f_t3[228]
    DIRECTION OUTPUT ;
    USE SIGNAL ;
    PORT
      LAYER M4 ;
        RECT  215.808 211.788 216 211.812 ;
    END
  END g_front_1_u_front__f_t3[228]
  PIN g_front_1_u_front__f_t3[229]
    DIRECTION OUTPUT ;
    USE SIGNAL ;
    PORT
      LAYER M4 ;
        RECT  215.808 212.22 216 212.244 ;
    END
  END g_front_1_u_front__f_t3[229]
  PIN g_front_1_u_front__f_t3[22]
    DIRECTION OUTPUT ;
    USE SIGNAL ;
    PORT
      LAYER M4 ;
        RECT  215.808 118.188 216 118.212 ;
    END
  END g_front_1_u_front__f_t3[22]
  PIN g_front_1_u_front__f_t3[230]
    DIRECTION OUTPUT ;
    USE SIGNAL ;
    PORT
      LAYER M4 ;
        RECT  215.808 212.7 216 212.724 ;
    END
  END g_front_1_u_front__f_t3[230]
  PIN g_front_1_u_front__f_t3[231]
    DIRECTION OUTPUT ;
    USE SIGNAL ;
    PORT
      LAYER M4 ;
        RECT  215.808 213.132 216 213.156 ;
    END
  END g_front_1_u_front__f_t3[231]
  PIN g_front_1_u_front__f_t3[232]
    DIRECTION OUTPUT ;
    USE SIGNAL ;
    PORT
      LAYER M4 ;
        RECT  215.808 213.612 216 213.636 ;
    END
  END g_front_1_u_front__f_t3[232]
  PIN g_front_1_u_front__f_t3[23]
    DIRECTION OUTPUT ;
    USE SIGNAL ;
    PORT
      LAYER M4 ;
        RECT  215.808 118.668 216 118.692 ;
    END
  END g_front_1_u_front__f_t3[23]
  PIN g_front_1_u_front__f_t3[24]
    DIRECTION OUTPUT ;
    USE SIGNAL ;
    PORT
      LAYER M4 ;
        RECT  215.808 119.1 216 119.124 ;
    END
  END g_front_1_u_front__f_t3[24]
  PIN g_front_1_u_front__f_t3[25]
    DIRECTION OUTPUT ;
    USE SIGNAL ;
    PORT
      LAYER M4 ;
        RECT  215.808 119.58 216 119.604 ;
    END
  END g_front_1_u_front__f_t3[25]
  PIN g_front_1_u_front__f_t3[26]
    DIRECTION OUTPUT ;
    USE SIGNAL ;
    PORT
      LAYER M4 ;
        RECT  215.808 120.012 216 120.036 ;
    END
  END g_front_1_u_front__f_t3[26]
  PIN g_front_1_u_front__f_t3[27]
    DIRECTION OUTPUT ;
    USE SIGNAL ;
    PORT
      LAYER M4 ;
        RECT  215.808 120.492 216 120.516 ;
    END
  END g_front_1_u_front__f_t3[27]
  PIN g_front_1_u_front__f_t3[28]
    DIRECTION OUTPUT ;
    USE SIGNAL ;
    PORT
      LAYER M4 ;
        RECT  215.808 120.924 216 120.948 ;
    END
  END g_front_1_u_front__f_t3[28]
  PIN g_front_1_u_front__f_t3[29]
    DIRECTION OUTPUT ;
    USE SIGNAL ;
    PORT
      LAYER M4 ;
        RECT  215.808 121.404 216 121.428 ;
    END
  END g_front_1_u_front__f_t3[29]
  PIN g_front_1_u_front__f_t3[2]
    DIRECTION OUTPUT ;
    USE SIGNAL ;
    PORT
      LAYER M4 ;
        RECT  215.808 109.116 216 109.14 ;
    END
  END g_front_1_u_front__f_t3[2]
  PIN g_front_1_u_front__f_t3[30]
    DIRECTION OUTPUT ;
    USE SIGNAL ;
    PORT
      LAYER M4 ;
        RECT  215.808 121.836 216 121.86 ;
    END
  END g_front_1_u_front__f_t3[30]
  PIN g_front_1_u_front__f_t3[31]
    DIRECTION OUTPUT ;
    USE SIGNAL ;
    PORT
      LAYER M4 ;
        RECT  215.808 122.316 216 122.34 ;
    END
  END g_front_1_u_front__f_t3[31]
  PIN g_front_1_u_front__f_t3[32]
    DIRECTION OUTPUT ;
    USE SIGNAL ;
    PORT
      LAYER M4 ;
        RECT  215.808 122.748 216 122.772 ;
    END
  END g_front_1_u_front__f_t3[32]
  PIN g_front_1_u_front__f_t3[33]
    DIRECTION OUTPUT ;
    USE SIGNAL ;
    PORT
      LAYER M4 ;
        RECT  215.808 123.228 216 123.252 ;
    END
  END g_front_1_u_front__f_t3[33]
  PIN g_front_1_u_front__f_t3[34]
    DIRECTION OUTPUT ;
    USE SIGNAL ;
    PORT
      LAYER M4 ;
        RECT  215.808 123.66 216 123.684 ;
    END
  END g_front_1_u_front__f_t3[34]
  PIN g_front_1_u_front__f_t3[35]
    DIRECTION OUTPUT ;
    USE SIGNAL ;
    PORT
      LAYER M4 ;
        RECT  215.808 124.092 216 124.116 ;
    END
  END g_front_1_u_front__f_t3[35]
  PIN g_front_1_u_front__f_t3[36]
    DIRECTION OUTPUT ;
    USE SIGNAL ;
    PORT
      LAYER M4 ;
        RECT  215.808 124.572 216 124.596 ;
    END
  END g_front_1_u_front__f_t3[36]
  PIN g_front_1_u_front__f_t3[37]
    DIRECTION OUTPUT ;
    USE SIGNAL ;
    PORT
      LAYER M4 ;
        RECT  215.808 125.004 216 125.028 ;
    END
  END g_front_1_u_front__f_t3[37]
  PIN g_front_1_u_front__f_t3[38]
    DIRECTION OUTPUT ;
    USE SIGNAL ;
    PORT
      LAYER M4 ;
        RECT  215.808 125.484 216 125.508 ;
    END
  END g_front_1_u_front__f_t3[38]
  PIN g_front_1_u_front__f_t3[39]
    DIRECTION OUTPUT ;
    USE SIGNAL ;
    PORT
      LAYER M4 ;
        RECT  215.808 125.916 216 125.94 ;
    END
  END g_front_1_u_front__f_t3[39]
  PIN g_front_1_u_front__f_t3[3]
    DIRECTION OUTPUT ;
    USE SIGNAL ;
    PORT
      LAYER M4 ;
        RECT  215.808 109.596 216 109.62 ;
    END
  END g_front_1_u_front__f_t3[3]
  PIN g_front_1_u_front__f_t3[40]
    DIRECTION OUTPUT ;
    USE SIGNAL ;
    PORT
      LAYER M4 ;
        RECT  215.808 126.396 216 126.42 ;
    END
  END g_front_1_u_front__f_t3[40]
  PIN g_front_1_u_front__f_t3[41]
    DIRECTION OUTPUT ;
    USE SIGNAL ;
    PORT
      LAYER M4 ;
        RECT  215.808 126.828 216 126.852 ;
    END
  END g_front_1_u_front__f_t3[41]
  PIN g_front_1_u_front__f_t3[42]
    DIRECTION OUTPUT ;
    USE SIGNAL ;
    PORT
      LAYER M4 ;
        RECT  215.808 127.308 216 127.332 ;
    END
  END g_front_1_u_front__f_t3[42]
  PIN g_front_1_u_front__f_t3[43]
    DIRECTION OUTPUT ;
    USE SIGNAL ;
    PORT
      LAYER M4 ;
        RECT  215.808 127.74 216 127.764 ;
    END
  END g_front_1_u_front__f_t3[43]
  PIN g_front_1_u_front__f_t3[44]
    DIRECTION OUTPUT ;
    USE SIGNAL ;
    PORT
      LAYER M4 ;
        RECT  215.808 128.22 216 128.244 ;
    END
  END g_front_1_u_front__f_t3[44]
  PIN g_front_1_u_front__f_t3[45]
    DIRECTION OUTPUT ;
    USE SIGNAL ;
    PORT
      LAYER M4 ;
        RECT  215.808 128.652 216 128.676 ;
    END
  END g_front_1_u_front__f_t3[45]
  PIN g_front_1_u_front__f_t3[46]
    DIRECTION OUTPUT ;
    USE SIGNAL ;
    PORT
      LAYER M4 ;
        RECT  215.808 129.132 216 129.156 ;
    END
  END g_front_1_u_front__f_t3[46]
  PIN g_front_1_u_front__f_t3[47]
    DIRECTION OUTPUT ;
    USE SIGNAL ;
    PORT
      LAYER M4 ;
        RECT  215.808 129.564 216 129.588 ;
    END
  END g_front_1_u_front__f_t3[47]
  PIN g_front_1_u_front__f_t3[48]
    DIRECTION OUTPUT ;
    USE SIGNAL ;
    PORT
      LAYER M4 ;
        RECT  215.808 129.996 216 130.02 ;
    END
  END g_front_1_u_front__f_t3[48]
  PIN g_front_1_u_front__f_t3[49]
    DIRECTION OUTPUT ;
    USE SIGNAL ;
    PORT
      LAYER M4 ;
        RECT  215.808 130.476 216 130.5 ;
    END
  END g_front_1_u_front__f_t3[49]
  PIN g_front_1_u_front__f_t3[4]
    DIRECTION OUTPUT ;
    USE SIGNAL ;
    PORT
      LAYER M4 ;
        RECT  215.808 110.028 216 110.052 ;
    END
  END g_front_1_u_front__f_t3[4]
  PIN g_front_1_u_front__f_t3[50]
    DIRECTION OUTPUT ;
    USE SIGNAL ;
    PORT
      LAYER M4 ;
        RECT  215.808 130.908 216 130.932 ;
    END
  END g_front_1_u_front__f_t3[50]
  PIN g_front_1_u_front__f_t3[51]
    DIRECTION OUTPUT ;
    USE SIGNAL ;
    PORT
      LAYER M4 ;
        RECT  215.808 131.388 216 131.412 ;
    END
  END g_front_1_u_front__f_t3[51]
  PIN g_front_1_u_front__f_t3[52]
    DIRECTION OUTPUT ;
    USE SIGNAL ;
    PORT
      LAYER M4 ;
        RECT  215.808 131.82 216 131.844 ;
    END
  END g_front_1_u_front__f_t3[52]
  PIN g_front_1_u_front__f_t3[53]
    DIRECTION OUTPUT ;
    USE SIGNAL ;
    PORT
      LAYER M4 ;
        RECT  215.808 132.3 216 132.324 ;
    END
  END g_front_1_u_front__f_t3[53]
  PIN g_front_1_u_front__f_t3[54]
    DIRECTION OUTPUT ;
    USE SIGNAL ;
    PORT
      LAYER M4 ;
        RECT  215.808 132.732 216 132.756 ;
    END
  END g_front_1_u_front__f_t3[54]
  PIN g_front_1_u_front__f_t3[55]
    DIRECTION OUTPUT ;
    USE SIGNAL ;
    PORT
      LAYER M4 ;
        RECT  215.808 133.212 216 133.236 ;
    END
  END g_front_1_u_front__f_t3[55]
  PIN g_front_1_u_front__f_t3[56]
    DIRECTION OUTPUT ;
    USE SIGNAL ;
    PORT
      LAYER M4 ;
        RECT  215.808 133.644 216 133.668 ;
    END
  END g_front_1_u_front__f_t3[56]
  PIN g_front_1_u_front__f_t3[57]
    DIRECTION OUTPUT ;
    USE SIGNAL ;
    PORT
      LAYER M4 ;
        RECT  215.808 134.124 216 134.148 ;
    END
  END g_front_1_u_front__f_t3[57]
  PIN g_front_1_u_front__f_t3[58]
    DIRECTION OUTPUT ;
    USE SIGNAL ;
    PORT
      LAYER M4 ;
        RECT  215.808 134.556 216 134.58 ;
    END
  END g_front_1_u_front__f_t3[58]
  PIN g_front_1_u_front__f_t3[59]
    DIRECTION OUTPUT ;
    USE SIGNAL ;
    PORT
      LAYER M4 ;
        RECT  215.808 135.036 216 135.06 ;
    END
  END g_front_1_u_front__f_t3[59]
  PIN g_front_1_u_front__f_t3[5]
    DIRECTION OUTPUT ;
    USE SIGNAL ;
    PORT
      LAYER M4 ;
        RECT  215.808 110.508 216 110.532 ;
    END
  END g_front_1_u_front__f_t3[5]
  PIN g_front_1_u_front__f_t3[60]
    DIRECTION OUTPUT ;
    USE SIGNAL ;
    PORT
      LAYER M4 ;
        RECT  215.808 135.468 216 135.492 ;
    END
  END g_front_1_u_front__f_t3[60]
  PIN g_front_1_u_front__f_t3[61]
    DIRECTION OUTPUT ;
    USE SIGNAL ;
    PORT
      LAYER M4 ;
        RECT  215.808 135.948 216 135.972 ;
    END
  END g_front_1_u_front__f_t3[61]
  PIN g_front_1_u_front__f_t3[62]
    DIRECTION OUTPUT ;
    USE SIGNAL ;
    PORT
      LAYER M4 ;
        RECT  215.808 136.38 216 136.404 ;
    END
  END g_front_1_u_front__f_t3[62]
  PIN g_front_1_u_front__f_t3[63]
    DIRECTION OUTPUT ;
    USE SIGNAL ;
    PORT
      LAYER M4 ;
        RECT  215.808 136.812 216 136.836 ;
    END
  END g_front_1_u_front__f_t3[63]
  PIN g_front_1_u_front__f_t3[64]
    DIRECTION OUTPUT ;
    USE SIGNAL ;
    PORT
      LAYER M4 ;
        RECT  215.808 137.292 216 137.316 ;
    END
  END g_front_1_u_front__f_t3[64]
  PIN g_front_1_u_front__f_t3[65]
    DIRECTION OUTPUT ;
    USE SIGNAL ;
    PORT
      LAYER M4 ;
        RECT  215.808 137.724 216 137.748 ;
    END
  END g_front_1_u_front__f_t3[65]
  PIN g_front_1_u_front__f_t3[66]
    DIRECTION OUTPUT ;
    USE SIGNAL ;
    PORT
      LAYER M4 ;
        RECT  215.808 138.204 216 138.228 ;
    END
  END g_front_1_u_front__f_t3[66]
  PIN g_front_1_u_front__f_t3[67]
    DIRECTION OUTPUT ;
    USE SIGNAL ;
    PORT
      LAYER M4 ;
        RECT  215.808 138.636 216 138.66 ;
    END
  END g_front_1_u_front__f_t3[67]
  PIN g_front_1_u_front__f_t3[68]
    DIRECTION OUTPUT ;
    USE SIGNAL ;
    PORT
      LAYER M4 ;
        RECT  215.808 139.116 216 139.14 ;
    END
  END g_front_1_u_front__f_t3[68]
  PIN g_front_1_u_front__f_t3[69]
    DIRECTION OUTPUT ;
    USE SIGNAL ;
    PORT
      LAYER M4 ;
        RECT  215.808 139.548 216 139.572 ;
    END
  END g_front_1_u_front__f_t3[69]
  PIN g_front_1_u_front__f_t3[6]
    DIRECTION OUTPUT ;
    USE SIGNAL ;
    PORT
      LAYER M4 ;
        RECT  215.808 110.94 216 110.964 ;
    END
  END g_front_1_u_front__f_t3[6]
  PIN g_front_1_u_front__f_t3[70]
    DIRECTION OUTPUT ;
    USE SIGNAL ;
    PORT
      LAYER M4 ;
        RECT  215.808 140.028 216 140.052 ;
    END
  END g_front_1_u_front__f_t3[70]
  PIN g_front_1_u_front__f_t3[71]
    DIRECTION OUTPUT ;
    USE SIGNAL ;
    PORT
      LAYER M4 ;
        RECT  215.808 140.46 216 140.484 ;
    END
  END g_front_1_u_front__f_t3[71]
  PIN g_front_1_u_front__f_t3[72]
    DIRECTION OUTPUT ;
    USE SIGNAL ;
    PORT
      LAYER M4 ;
        RECT  215.808 140.94 216 140.964 ;
    END
  END g_front_1_u_front__f_t3[72]
  PIN g_front_1_u_front__f_t3[73]
    DIRECTION OUTPUT ;
    USE SIGNAL ;
    PORT
      LAYER M4 ;
        RECT  215.808 141.372 216 141.396 ;
    END
  END g_front_1_u_front__f_t3[73]
  PIN g_front_1_u_front__f_t3[74]
    DIRECTION OUTPUT ;
    USE SIGNAL ;
    PORT
      LAYER M4 ;
        RECT  215.808 141.852 216 141.876 ;
    END
  END g_front_1_u_front__f_t3[74]
  PIN g_front_1_u_front__f_t3[75]
    DIRECTION OUTPUT ;
    USE SIGNAL ;
    PORT
      LAYER M4 ;
        RECT  215.808 142.284 216 142.308 ;
    END
  END g_front_1_u_front__f_t3[75]
  PIN g_front_1_u_front__f_t3[76]
    DIRECTION OUTPUT ;
    USE SIGNAL ;
    PORT
      LAYER M4 ;
        RECT  215.808 142.716 216 142.74 ;
    END
  END g_front_1_u_front__f_t3[76]
  PIN g_front_1_u_front__f_t3[77]
    DIRECTION OUTPUT ;
    USE SIGNAL ;
    PORT
      LAYER M4 ;
        RECT  215.808 143.196 216 143.22 ;
    END
  END g_front_1_u_front__f_t3[77]
  PIN g_front_1_u_front__f_t3[78]
    DIRECTION OUTPUT ;
    USE SIGNAL ;
    PORT
      LAYER M4 ;
        RECT  215.808 143.628 216 143.652 ;
    END
  END g_front_1_u_front__f_t3[78]
  PIN g_front_1_u_front__f_t3[79]
    DIRECTION OUTPUT ;
    USE SIGNAL ;
    PORT
      LAYER M4 ;
        RECT  215.808 144.108 216 144.132 ;
    END
  END g_front_1_u_front__f_t3[79]
  PIN g_front_1_u_front__f_t3[7]
    DIRECTION OUTPUT ;
    USE SIGNAL ;
    PORT
      LAYER M4 ;
        RECT  215.808 111.372 216 111.396 ;
    END
  END g_front_1_u_front__f_t3[7]
  PIN g_front_1_u_front__f_t3[80]
    DIRECTION OUTPUT ;
    USE SIGNAL ;
    PORT
      LAYER M4 ;
        RECT  215.808 144.54 216 144.564 ;
    END
  END g_front_1_u_front__f_t3[80]
  PIN g_front_1_u_front__f_t3[81]
    DIRECTION OUTPUT ;
    USE SIGNAL ;
    PORT
      LAYER M4 ;
        RECT  215.808 145.02 216 145.044 ;
    END
  END g_front_1_u_front__f_t3[81]
  PIN g_front_1_u_front__f_t3[82]
    DIRECTION OUTPUT ;
    USE SIGNAL ;
    PORT
      LAYER M4 ;
        RECT  215.808 145.452 216 145.476 ;
    END
  END g_front_1_u_front__f_t3[82]
  PIN g_front_1_u_front__f_t3[83]
    DIRECTION OUTPUT ;
    USE SIGNAL ;
    PORT
      LAYER M4 ;
        RECT  215.808 145.932 216 145.956 ;
    END
  END g_front_1_u_front__f_t3[83]
  PIN g_front_1_u_front__f_t3[84]
    DIRECTION OUTPUT ;
    USE SIGNAL ;
    PORT
      LAYER M4 ;
        RECT  215.808 146.364 216 146.388 ;
    END
  END g_front_1_u_front__f_t3[84]
  PIN g_front_1_u_front__f_t3[85]
    DIRECTION OUTPUT ;
    USE SIGNAL ;
    PORT
      LAYER M4 ;
        RECT  215.808 146.844 216 146.868 ;
    END
  END g_front_1_u_front__f_t3[85]
  PIN g_front_1_u_front__f_t3[86]
    DIRECTION OUTPUT ;
    USE SIGNAL ;
    PORT
      LAYER M4 ;
        RECT  215.808 147.276 216 147.3 ;
    END
  END g_front_1_u_front__f_t3[86]
  PIN g_front_1_u_front__f_t3[87]
    DIRECTION OUTPUT ;
    USE SIGNAL ;
    PORT
      LAYER M4 ;
        RECT  215.808 147.756 216 147.78 ;
    END
  END g_front_1_u_front__f_t3[87]
  PIN g_front_1_u_front__f_t3[88]
    DIRECTION OUTPUT ;
    USE SIGNAL ;
    PORT
      LAYER M4 ;
        RECT  215.808 148.188 216 148.212 ;
    END
  END g_front_1_u_front__f_t3[88]
  PIN g_front_1_u_front__f_t3[89]
    DIRECTION OUTPUT ;
    USE SIGNAL ;
    PORT
      LAYER M4 ;
        RECT  215.808 148.62 216 148.644 ;
    END
  END g_front_1_u_front__f_t3[89]
  PIN g_front_1_u_front__f_t3[8]
    DIRECTION OUTPUT ;
    USE SIGNAL ;
    PORT
      LAYER M4 ;
        RECT  215.808 111.852 216 111.876 ;
    END
  END g_front_1_u_front__f_t3[8]
  PIN g_front_1_u_front__f_t3[90]
    DIRECTION OUTPUT ;
    USE SIGNAL ;
    PORT
      LAYER M4 ;
        RECT  215.808 149.1 216 149.124 ;
    END
  END g_front_1_u_front__f_t3[90]
  PIN g_front_1_u_front__f_t3[91]
    DIRECTION OUTPUT ;
    USE SIGNAL ;
    PORT
      LAYER M4 ;
        RECT  215.808 149.532 216 149.556 ;
    END
  END g_front_1_u_front__f_t3[91]
  PIN g_front_1_u_front__f_t3[92]
    DIRECTION OUTPUT ;
    USE SIGNAL ;
    PORT
      LAYER M4 ;
        RECT  215.808 150.012 216 150.036 ;
    END
  END g_front_1_u_front__f_t3[92]
  PIN g_front_1_u_front__f_t3[93]
    DIRECTION OUTPUT ;
    USE SIGNAL ;
    PORT
      LAYER M4 ;
        RECT  215.808 150.444 216 150.468 ;
    END
  END g_front_1_u_front__f_t3[93]
  PIN g_front_1_u_front__f_t3[94]
    DIRECTION OUTPUT ;
    USE SIGNAL ;
    PORT
      LAYER M4 ;
        RECT  215.808 150.924 216 150.948 ;
    END
  END g_front_1_u_front__f_t3[94]
  PIN g_front_1_u_front__f_t3[95]
    DIRECTION OUTPUT ;
    USE SIGNAL ;
    PORT
      LAYER M4 ;
        RECT  215.808 151.356 216 151.38 ;
    END
  END g_front_1_u_front__f_t3[95]
  PIN g_front_1_u_front__f_t3[96]
    DIRECTION OUTPUT ;
    USE SIGNAL ;
    PORT
      LAYER M4 ;
        RECT  215.808 151.836 216 151.86 ;
    END
  END g_front_1_u_front__f_t3[96]
  PIN g_front_1_u_front__f_t3[97]
    DIRECTION OUTPUT ;
    USE SIGNAL ;
    PORT
      LAYER M4 ;
        RECT  215.808 152.268 216 152.292 ;
    END
  END g_front_1_u_front__f_t3[97]
  PIN g_front_1_u_front__f_t3[98]
    DIRECTION OUTPUT ;
    USE SIGNAL ;
    PORT
      LAYER M4 ;
        RECT  215.808 152.748 216 152.772 ;
    END
  END g_front_1_u_front__f_t3[98]
  PIN g_front_1_u_front__f_t3[99]
    DIRECTION OUTPUT ;
    USE SIGNAL ;
    PORT
      LAYER M4 ;
        RECT  215.808 153.18 216 153.204 ;
    END
  END g_front_1_u_front__f_t3[99]
  PIN g_front_1_u_front__f_t3[9]
    DIRECTION OUTPUT ;
    USE SIGNAL ;
    PORT
      LAYER M4 ;
        RECT  215.808 112.284 216 112.308 ;
    END
  END g_front_1_u_front__f_t3[9]
  PIN g_front_1_u_front__hid[0]
    DIRECTION INPUT ;
    USE SIGNAL ;
    PORT
      LAYER M4 ;
        RECT  0 108.06 0.192 108.084 ;
    END
  END g_front_1_u_front__hid[0]
  PIN g_front_1_u_front__hid[1]
    DIRECTION INPUT ;
    USE SIGNAL ;
    PORT
      LAYER M4 ;
        RECT  0 107.964 0.192 107.988 ;
    END
  END g_front_1_u_front__hid[1]
  PIN g_front_1_u_front__lt_in[0]
    DIRECTION INPUT ;
    USE SIGNAL ;
    PORT
      LAYER M5 ;
        RECT  9.18 0 9.204 0.192 ;
    END
  END g_front_1_u_front__lt_in[0]
  PIN g_front_1_u_front__lt_in[10]
    DIRECTION INPUT ;
    USE SIGNAL ;
    PORT
      LAYER M5 ;
        RECT  12.588 0 12.612 0.192 ;
    END
  END g_front_1_u_front__lt_in[10]
  PIN g_front_1_u_front__lt_in[11]
    DIRECTION INPUT ;
    USE SIGNAL ;
    PORT
      LAYER M5 ;
        RECT  12.924 0 12.948 0.192 ;
    END
  END g_front_1_u_front__lt_in[11]
  PIN g_front_1_u_front__lt_in[1]
    DIRECTION INPUT ;
    USE SIGNAL ;
    PORT
      LAYER M5 ;
        RECT  9.516 0 9.54 0.192 ;
    END
  END g_front_1_u_front__lt_in[1]
  PIN g_front_1_u_front__lt_in[2]
    DIRECTION INPUT ;
    USE SIGNAL ;
    PORT
      LAYER M5 ;
        RECT  9.852 0 9.876 0.192 ;
    END
  END g_front_1_u_front__lt_in[2]
  PIN g_front_1_u_front__lt_in[3]
    DIRECTION INPUT ;
    USE SIGNAL ;
    PORT
      LAYER M5 ;
        RECT  10.188 0 10.212 0.192 ;
    END
  END g_front_1_u_front__lt_in[3]
  PIN g_front_1_u_front__lt_in[4]
    DIRECTION INPUT ;
    USE SIGNAL ;
    PORT
      LAYER M5 ;
        RECT  10.524 0 10.548 0.192 ;
    END
  END g_front_1_u_front__lt_in[4]
  PIN g_front_1_u_front__lt_in[5]
    DIRECTION INPUT ;
    USE SIGNAL ;
    PORT
      LAYER M5 ;
        RECT  10.86 0 10.884 0.192 ;
    END
  END g_front_1_u_front__lt_in[5]
  PIN g_front_1_u_front__lt_in[6]
    DIRECTION INPUT ;
    USE SIGNAL ;
    PORT
      LAYER M5 ;
        RECT  11.196 0 11.22 0.192 ;
    END
  END g_front_1_u_front__lt_in[6]
  PIN g_front_1_u_front__lt_in[7]
    DIRECTION INPUT ;
    USE SIGNAL ;
    PORT
      LAYER M5 ;
        RECT  11.532 0 11.556 0.192 ;
    END
  END g_front_1_u_front__lt_in[7]
  PIN g_front_1_u_front__lt_in[8]
    DIRECTION INPUT ;
    USE SIGNAL ;
    PORT
      LAYER M5 ;
        RECT  11.916 0 11.94 0.192 ;
    END
  END g_front_1_u_front__lt_in[8]
  PIN g_front_1_u_front__lt_in[9]
    DIRECTION INPUT ;
    USE SIGNAL ;
    PORT
      LAYER M5 ;
        RECT  12.252 0 12.276 0.192 ;
    END
  END g_front_1_u_front__lt_in[9]
  PIN g_front_1_u_front__pack_fault[0]
    DIRECTION OUTPUT ;
    USE SIGNAL ;
    PORT
      LAYER M5 ;
        RECT  3.324 215.808 3.348 216 ;
    END
  END g_front_1_u_front__pack_fault[0]
  PIN g_front_1_u_front__q_beat_in[0]
    DIRECTION INPUT ;
    USE SIGNAL ;
    PORT
      LAYER M5 ;
        RECT  13.26 0 13.284 0.192 ;
    END
  END g_front_1_u_front__q_beat_in[0]
  PIN g_front_1_u_front__q_beat_in[1]
    DIRECTION INPUT ;
    USE SIGNAL ;
    PORT
      LAYER M5 ;
        RECT  13.596 0 13.62 0.192 ;
    END
  END g_front_1_u_front__q_beat_in[1]
  PIN g_front_1_u_front__q_beat_in[2]
    DIRECTION INPUT ;
    USE SIGNAL ;
    PORT
      LAYER M5 ;
        RECT  13.932 0 13.956 0.192 ;
    END
  END g_front_1_u_front__q_beat_in[2]
  PIN g_front_1_u_front__q_beat_in[3]
    DIRECTION INPUT ;
    USE SIGNAL ;
    PORT
      LAYER M5 ;
        RECT  14.268 0 14.292 0.192 ;
    END
  END g_front_1_u_front__q_beat_in[3]
  PIN g_front_1_u_front__q_beat_in[4]
    DIRECTION INPUT ;
    USE SIGNAL ;
    PORT
      LAYER M5 ;
        RECT  14.652 0 14.676 0.192 ;
    END
  END g_front_1_u_front__q_beat_in[4]
  PIN g_front_1_u_front__q_beat_in[5]
    DIRECTION INPUT ;
    USE SIGNAL ;
    PORT
      LAYER M5 ;
        RECT  14.988 0 15.012 0.192 ;
    END
  END g_front_1_u_front__q_beat_in[5]
  PIN g_front_1_u_front__q_data_in[0]
    DIRECTION INPUT ;
    USE SIGNAL ;
    PORT
      LAYER M5 ;
        RECT  15.324 0 15.348 0.192 ;
    END
  END g_front_1_u_front__q_data_in[0]
  PIN g_front_1_u_front__q_data_in[100]
    DIRECTION INPUT ;
    USE SIGNAL ;
    PORT
      LAYER M5 ;
        RECT  49.5 0 49.524 0.192 ;
    END
  END g_front_1_u_front__q_data_in[100]
  PIN g_front_1_u_front__q_data_in[101]
    DIRECTION INPUT ;
    USE SIGNAL ;
    PORT
      LAYER M5 ;
        RECT  49.836 0 49.86 0.192 ;
    END
  END g_front_1_u_front__q_data_in[101]
  PIN g_front_1_u_front__q_data_in[102]
    DIRECTION INPUT ;
    USE SIGNAL ;
    PORT
      LAYER M5 ;
        RECT  50.172 0 50.196 0.192 ;
    END
  END g_front_1_u_front__q_data_in[102]
  PIN g_front_1_u_front__q_data_in[103]
    DIRECTION INPUT ;
    USE SIGNAL ;
    PORT
      LAYER M5 ;
        RECT  50.556 0 50.58 0.192 ;
    END
  END g_front_1_u_front__q_data_in[103]
  PIN g_front_1_u_front__q_data_in[104]
    DIRECTION INPUT ;
    USE SIGNAL ;
    PORT
      LAYER M5 ;
        RECT  50.892 0 50.916 0.192 ;
    END
  END g_front_1_u_front__q_data_in[104]
  PIN g_front_1_u_front__q_data_in[105]
    DIRECTION INPUT ;
    USE SIGNAL ;
    PORT
      LAYER M5 ;
        RECT  51.228 0 51.252 0.192 ;
    END
  END g_front_1_u_front__q_data_in[105]
  PIN g_front_1_u_front__q_data_in[106]
    DIRECTION INPUT ;
    USE SIGNAL ;
    PORT
      LAYER M5 ;
        RECT  51.564 0 51.588 0.192 ;
    END
  END g_front_1_u_front__q_data_in[106]
  PIN g_front_1_u_front__q_data_in[107]
    DIRECTION INPUT ;
    USE SIGNAL ;
    PORT
      LAYER M5 ;
        RECT  51.9 0 51.924 0.192 ;
    END
  END g_front_1_u_front__q_data_in[107]
  PIN g_front_1_u_front__q_data_in[108]
    DIRECTION INPUT ;
    USE SIGNAL ;
    PORT
      LAYER M5 ;
        RECT  52.236 0 52.26 0.192 ;
    END
  END g_front_1_u_front__q_data_in[108]
  PIN g_front_1_u_front__q_data_in[109]
    DIRECTION INPUT ;
    USE SIGNAL ;
    PORT
      LAYER M5 ;
        RECT  52.572 0 52.596 0.192 ;
    END
  END g_front_1_u_front__q_data_in[109]
  PIN g_front_1_u_front__q_data_in[10]
    DIRECTION INPUT ;
    USE SIGNAL ;
    PORT
      LAYER M5 ;
        RECT  18.732 0 18.756 0.192 ;
    END
  END g_front_1_u_front__q_data_in[10]
  PIN g_front_1_u_front__q_data_in[110]
    DIRECTION INPUT ;
    USE SIGNAL ;
    PORT
      LAYER M5 ;
        RECT  52.908 0 52.932 0.192 ;
    END
  END g_front_1_u_front__q_data_in[110]
  PIN g_front_1_u_front__q_data_in[111]
    DIRECTION INPUT ;
    USE SIGNAL ;
    PORT
      LAYER M5 ;
        RECT  53.292 0 53.316 0.192 ;
    END
  END g_front_1_u_front__q_data_in[111]
  PIN g_front_1_u_front__q_data_in[112]
    DIRECTION INPUT ;
    USE SIGNAL ;
    PORT
      LAYER M5 ;
        RECT  53.628 0 53.652 0.192 ;
    END
  END g_front_1_u_front__q_data_in[112]
  PIN g_front_1_u_front__q_data_in[113]
    DIRECTION INPUT ;
    USE SIGNAL ;
    PORT
      LAYER M5 ;
        RECT  53.964 0 53.988 0.192 ;
    END
  END g_front_1_u_front__q_data_in[113]
  PIN g_front_1_u_front__q_data_in[114]
    DIRECTION INPUT ;
    USE SIGNAL ;
    PORT
      LAYER M5 ;
        RECT  54.3 0 54.324 0.192 ;
    END
  END g_front_1_u_front__q_data_in[114]
  PIN g_front_1_u_front__q_data_in[115]
    DIRECTION INPUT ;
    USE SIGNAL ;
    PORT
      LAYER M5 ;
        RECT  54.636 0 54.66 0.192 ;
    END
  END g_front_1_u_front__q_data_in[115]
  PIN g_front_1_u_front__q_data_in[116]
    DIRECTION INPUT ;
    USE SIGNAL ;
    PORT
      LAYER M5 ;
        RECT  54.972 0 54.996 0.192 ;
    END
  END g_front_1_u_front__q_data_in[116]
  PIN g_front_1_u_front__q_data_in[117]
    DIRECTION INPUT ;
    USE SIGNAL ;
    PORT
      LAYER M5 ;
        RECT  55.308 0 55.332 0.192 ;
    END
  END g_front_1_u_front__q_data_in[117]
  PIN g_front_1_u_front__q_data_in[118]
    DIRECTION INPUT ;
    USE SIGNAL ;
    PORT
      LAYER M5 ;
        RECT  55.644 0 55.668 0.192 ;
    END
  END g_front_1_u_front__q_data_in[118]
  PIN g_front_1_u_front__q_data_in[119]
    DIRECTION INPUT ;
    USE SIGNAL ;
    PORT
      LAYER M5 ;
        RECT  56.028 0 56.052 0.192 ;
    END
  END g_front_1_u_front__q_data_in[119]
  PIN g_front_1_u_front__q_data_in[11]
    DIRECTION INPUT ;
    USE SIGNAL ;
    PORT
      LAYER M5 ;
        RECT  19.068 0 19.092 0.192 ;
    END
  END g_front_1_u_front__q_data_in[11]
  PIN g_front_1_u_front__q_data_in[120]
    DIRECTION INPUT ;
    USE SIGNAL ;
    PORT
      LAYER M5 ;
        RECT  56.364 0 56.388 0.192 ;
    END
  END g_front_1_u_front__q_data_in[120]
  PIN g_front_1_u_front__q_data_in[121]
    DIRECTION INPUT ;
    USE SIGNAL ;
    PORT
      LAYER M5 ;
        RECT  56.7 0 56.724 0.192 ;
    END
  END g_front_1_u_front__q_data_in[121]
  PIN g_front_1_u_front__q_data_in[122]
    DIRECTION INPUT ;
    USE SIGNAL ;
    PORT
      LAYER M5 ;
        RECT  57.036 0 57.06 0.192 ;
    END
  END g_front_1_u_front__q_data_in[122]
  PIN g_front_1_u_front__q_data_in[123]
    DIRECTION INPUT ;
    USE SIGNAL ;
    PORT
      LAYER M5 ;
        RECT  57.372 0 57.396 0.192 ;
    END
  END g_front_1_u_front__q_data_in[123]
  PIN g_front_1_u_front__q_data_in[124]
    DIRECTION INPUT ;
    USE SIGNAL ;
    PORT
      LAYER M5 ;
        RECT  57.708 0 57.732 0.192 ;
    END
  END g_front_1_u_front__q_data_in[124]
  PIN g_front_1_u_front__q_data_in[125]
    DIRECTION INPUT ;
    USE SIGNAL ;
    PORT
      LAYER M5 ;
        RECT  58.044 0 58.068 0.192 ;
    END
  END g_front_1_u_front__q_data_in[125]
  PIN g_front_1_u_front__q_data_in[126]
    DIRECTION INPUT ;
    USE SIGNAL ;
    PORT
      LAYER M5 ;
        RECT  58.38 0 58.404 0.192 ;
    END
  END g_front_1_u_front__q_data_in[126]
  PIN g_front_1_u_front__q_data_in[127]
    DIRECTION INPUT ;
    USE SIGNAL ;
    PORT
      LAYER M5 ;
        RECT  58.764 0 58.788 0.192 ;
    END
  END g_front_1_u_front__q_data_in[127]
  PIN g_front_1_u_front__q_data_in[128]
    DIRECTION INPUT ;
    USE SIGNAL ;
    PORT
      LAYER M5 ;
        RECT  59.1 0 59.124 0.192 ;
    END
  END g_front_1_u_front__q_data_in[128]
  PIN g_front_1_u_front__q_data_in[129]
    DIRECTION INPUT ;
    USE SIGNAL ;
    PORT
      LAYER M5 ;
        RECT  59.436 0 59.46 0.192 ;
    END
  END g_front_1_u_front__q_data_in[129]
  PIN g_front_1_u_front__q_data_in[12]
    DIRECTION INPUT ;
    USE SIGNAL ;
    PORT
      LAYER M5 ;
        RECT  19.404 0 19.428 0.192 ;
    END
  END g_front_1_u_front__q_data_in[12]
  PIN g_front_1_u_front__q_data_in[130]
    DIRECTION INPUT ;
    USE SIGNAL ;
    PORT
      LAYER M5 ;
        RECT  59.772 0 59.796 0.192 ;
    END
  END g_front_1_u_front__q_data_in[130]
  PIN g_front_1_u_front__q_data_in[131]
    DIRECTION INPUT ;
    USE SIGNAL ;
    PORT
      LAYER M5 ;
        RECT  60.108 0 60.132 0.192 ;
    END
  END g_front_1_u_front__q_data_in[131]
  PIN g_front_1_u_front__q_data_in[132]
    DIRECTION INPUT ;
    USE SIGNAL ;
    PORT
      LAYER M5 ;
        RECT  60.444 0 60.468 0.192 ;
    END
  END g_front_1_u_front__q_data_in[132]
  PIN g_front_1_u_front__q_data_in[133]
    DIRECTION INPUT ;
    USE SIGNAL ;
    PORT
      LAYER M5 ;
        RECT  60.78 0 60.804 0.192 ;
    END
  END g_front_1_u_front__q_data_in[133]
  PIN g_front_1_u_front__q_data_in[134]
    DIRECTION INPUT ;
    USE SIGNAL ;
    PORT
      LAYER M5 ;
        RECT  61.116 0 61.14 0.192 ;
    END
  END g_front_1_u_front__q_data_in[134]
  PIN g_front_1_u_front__q_data_in[135]
    DIRECTION INPUT ;
    USE SIGNAL ;
    PORT
      LAYER M5 ;
        RECT  61.5 0 61.524 0.192 ;
    END
  END g_front_1_u_front__q_data_in[135]
  PIN g_front_1_u_front__q_data_in[136]
    DIRECTION INPUT ;
    USE SIGNAL ;
    PORT
      LAYER M5 ;
        RECT  61.836 0 61.86 0.192 ;
    END
  END g_front_1_u_front__q_data_in[136]
  PIN g_front_1_u_front__q_data_in[137]
    DIRECTION INPUT ;
    USE SIGNAL ;
    PORT
      LAYER M5 ;
        RECT  62.172 0 62.196 0.192 ;
    END
  END g_front_1_u_front__q_data_in[137]
  PIN g_front_1_u_front__q_data_in[138]
    DIRECTION INPUT ;
    USE SIGNAL ;
    PORT
      LAYER M5 ;
        RECT  62.508 0 62.532 0.192 ;
    END
  END g_front_1_u_front__q_data_in[138]
  PIN g_front_1_u_front__q_data_in[139]
    DIRECTION INPUT ;
    USE SIGNAL ;
    PORT
      LAYER M5 ;
        RECT  62.844 0 62.868 0.192 ;
    END
  END g_front_1_u_front__q_data_in[139]
  PIN g_front_1_u_front__q_data_in[13]
    DIRECTION INPUT ;
    USE SIGNAL ;
    PORT
      LAYER M5 ;
        RECT  19.74 0 19.764 0.192 ;
    END
  END g_front_1_u_front__q_data_in[13]
  PIN g_front_1_u_front__q_data_in[140]
    DIRECTION INPUT ;
    USE SIGNAL ;
    PORT
      LAYER M5 ;
        RECT  63.18 0 63.204 0.192 ;
    END
  END g_front_1_u_front__q_data_in[140]
  PIN g_front_1_u_front__q_data_in[141]
    DIRECTION INPUT ;
    USE SIGNAL ;
    PORT
      LAYER M5 ;
        RECT  63.516 0 63.54 0.192 ;
    END
  END g_front_1_u_front__q_data_in[141]
  PIN g_front_1_u_front__q_data_in[142]
    DIRECTION INPUT ;
    USE SIGNAL ;
    PORT
      LAYER M5 ;
        RECT  63.852 0 63.876 0.192 ;
    END
  END g_front_1_u_front__q_data_in[142]
  PIN g_front_1_u_front__q_data_in[143]
    DIRECTION INPUT ;
    USE SIGNAL ;
    PORT
      LAYER M5 ;
        RECT  64.236 0 64.26 0.192 ;
    END
  END g_front_1_u_front__q_data_in[143]
  PIN g_front_1_u_front__q_data_in[144]
    DIRECTION INPUT ;
    USE SIGNAL ;
    PORT
      LAYER M5 ;
        RECT  64.572 0 64.596 0.192 ;
    END
  END g_front_1_u_front__q_data_in[144]
  PIN g_front_1_u_front__q_data_in[145]
    DIRECTION INPUT ;
    USE SIGNAL ;
    PORT
      LAYER M5 ;
        RECT  64.908 0 64.932 0.192 ;
    END
  END g_front_1_u_front__q_data_in[145]
  PIN g_front_1_u_front__q_data_in[146]
    DIRECTION INPUT ;
    USE SIGNAL ;
    PORT
      LAYER M5 ;
        RECT  65.244 0 65.268 0.192 ;
    END
  END g_front_1_u_front__q_data_in[146]
  PIN g_front_1_u_front__q_data_in[147]
    DIRECTION INPUT ;
    USE SIGNAL ;
    PORT
      LAYER M5 ;
        RECT  65.58 0 65.604 0.192 ;
    END
  END g_front_1_u_front__q_data_in[147]
  PIN g_front_1_u_front__q_data_in[148]
    DIRECTION INPUT ;
    USE SIGNAL ;
    PORT
      LAYER M5 ;
        RECT  65.916 0 65.94 0.192 ;
    END
  END g_front_1_u_front__q_data_in[148]
  PIN g_front_1_u_front__q_data_in[149]
    DIRECTION INPUT ;
    USE SIGNAL ;
    PORT
      LAYER M5 ;
        RECT  66.252 0 66.276 0.192 ;
    END
  END g_front_1_u_front__q_data_in[149]
  PIN g_front_1_u_front__q_data_in[14]
    DIRECTION INPUT ;
    USE SIGNAL ;
    PORT
      LAYER M5 ;
        RECT  20.124 0 20.148 0.192 ;
    END
  END g_front_1_u_front__q_data_in[14]
  PIN g_front_1_u_front__q_data_in[150]
    DIRECTION INPUT ;
    USE SIGNAL ;
    PORT
      LAYER M5 ;
        RECT  66.588 0 66.612 0.192 ;
    END
  END g_front_1_u_front__q_data_in[150]
  PIN g_front_1_u_front__q_data_in[151]
    DIRECTION INPUT ;
    USE SIGNAL ;
    PORT
      LAYER M5 ;
        RECT  66.972 0 66.996 0.192 ;
    END
  END g_front_1_u_front__q_data_in[151]
  PIN g_front_1_u_front__q_data_in[152]
    DIRECTION INPUT ;
    USE SIGNAL ;
    PORT
      LAYER M5 ;
        RECT  67.308 0 67.332 0.192 ;
    END
  END g_front_1_u_front__q_data_in[152]
  PIN g_front_1_u_front__q_data_in[153]
    DIRECTION INPUT ;
    USE SIGNAL ;
    PORT
      LAYER M5 ;
        RECT  67.644 0 67.668 0.192 ;
    END
  END g_front_1_u_front__q_data_in[153]
  PIN g_front_1_u_front__q_data_in[154]
    DIRECTION INPUT ;
    USE SIGNAL ;
    PORT
      LAYER M5 ;
        RECT  67.98 0 68.004 0.192 ;
    END
  END g_front_1_u_front__q_data_in[154]
  PIN g_front_1_u_front__q_data_in[155]
    DIRECTION INPUT ;
    USE SIGNAL ;
    PORT
      LAYER M5 ;
        RECT  68.316 0 68.34 0.192 ;
    END
  END g_front_1_u_front__q_data_in[155]
  PIN g_front_1_u_front__q_data_in[156]
    DIRECTION INPUT ;
    USE SIGNAL ;
    PORT
      LAYER M5 ;
        RECT  68.652 0 68.676 0.192 ;
    END
  END g_front_1_u_front__q_data_in[156]
  PIN g_front_1_u_front__q_data_in[157]
    DIRECTION INPUT ;
    USE SIGNAL ;
    PORT
      LAYER M5 ;
        RECT  68.988 0 69.012 0.192 ;
    END
  END g_front_1_u_front__q_data_in[157]
  PIN g_front_1_u_front__q_data_in[158]
    DIRECTION INPUT ;
    USE SIGNAL ;
    PORT
      LAYER M5 ;
        RECT  69.324 0 69.348 0.192 ;
    END
  END g_front_1_u_front__q_data_in[158]
  PIN g_front_1_u_front__q_data_in[159]
    DIRECTION INPUT ;
    USE SIGNAL ;
    PORT
      LAYER M5 ;
        RECT  69.708 0 69.732 0.192 ;
    END
  END g_front_1_u_front__q_data_in[159]
  PIN g_front_1_u_front__q_data_in[15]
    DIRECTION INPUT ;
    USE SIGNAL ;
    PORT
      LAYER M5 ;
        RECT  20.46 0 20.484 0.192 ;
    END
  END g_front_1_u_front__q_data_in[15]
  PIN g_front_1_u_front__q_data_in[160]
    DIRECTION INPUT ;
    USE SIGNAL ;
    PORT
      LAYER M5 ;
        RECT  70.044 0 70.068 0.192 ;
    END
  END g_front_1_u_front__q_data_in[160]
  PIN g_front_1_u_front__q_data_in[161]
    DIRECTION INPUT ;
    USE SIGNAL ;
    PORT
      LAYER M5 ;
        RECT  70.38 0 70.404 0.192 ;
    END
  END g_front_1_u_front__q_data_in[161]
  PIN g_front_1_u_front__q_data_in[162]
    DIRECTION INPUT ;
    USE SIGNAL ;
    PORT
      LAYER M5 ;
        RECT  70.716 0 70.74 0.192 ;
    END
  END g_front_1_u_front__q_data_in[162]
  PIN g_front_1_u_front__q_data_in[163]
    DIRECTION INPUT ;
    USE SIGNAL ;
    PORT
      LAYER M5 ;
        RECT  71.052 0 71.076 0.192 ;
    END
  END g_front_1_u_front__q_data_in[163]
  PIN g_front_1_u_front__q_data_in[164]
    DIRECTION INPUT ;
    USE SIGNAL ;
    PORT
      LAYER M5 ;
        RECT  71.388 0 71.412 0.192 ;
    END
  END g_front_1_u_front__q_data_in[164]
  PIN g_front_1_u_front__q_data_in[165]
    DIRECTION INPUT ;
    USE SIGNAL ;
    PORT
      LAYER M5 ;
        RECT  71.724 0 71.748 0.192 ;
    END
  END g_front_1_u_front__q_data_in[165]
  PIN g_front_1_u_front__q_data_in[166]
    DIRECTION INPUT ;
    USE SIGNAL ;
    PORT
      LAYER M5 ;
        RECT  72.06 0 72.084 0.192 ;
    END
  END g_front_1_u_front__q_data_in[166]
  PIN g_front_1_u_front__q_data_in[167]
    DIRECTION INPUT ;
    USE SIGNAL ;
    PORT
      LAYER M5 ;
        RECT  72.444 0 72.468 0.192 ;
    END
  END g_front_1_u_front__q_data_in[167]
  PIN g_front_1_u_front__q_data_in[168]
    DIRECTION INPUT ;
    USE SIGNAL ;
    PORT
      LAYER M5 ;
        RECT  72.78 0 72.804 0.192 ;
    END
  END g_front_1_u_front__q_data_in[168]
  PIN g_front_1_u_front__q_data_in[169]
    DIRECTION INPUT ;
    USE SIGNAL ;
    PORT
      LAYER M5 ;
        RECT  73.116 0 73.14 0.192 ;
    END
  END g_front_1_u_front__q_data_in[169]
  PIN g_front_1_u_front__q_data_in[16]
    DIRECTION INPUT ;
    USE SIGNAL ;
    PORT
      LAYER M5 ;
        RECT  20.796 0 20.82 0.192 ;
    END
  END g_front_1_u_front__q_data_in[16]
  PIN g_front_1_u_front__q_data_in[170]
    DIRECTION INPUT ;
    USE SIGNAL ;
    PORT
      LAYER M5 ;
        RECT  73.452 0 73.476 0.192 ;
    END
  END g_front_1_u_front__q_data_in[170]
  PIN g_front_1_u_front__q_data_in[171]
    DIRECTION INPUT ;
    USE SIGNAL ;
    PORT
      LAYER M5 ;
        RECT  73.788 0 73.812 0.192 ;
    END
  END g_front_1_u_front__q_data_in[171]
  PIN g_front_1_u_front__q_data_in[172]
    DIRECTION INPUT ;
    USE SIGNAL ;
    PORT
      LAYER M5 ;
        RECT  74.124 0 74.148 0.192 ;
    END
  END g_front_1_u_front__q_data_in[172]
  PIN g_front_1_u_front__q_data_in[173]
    DIRECTION INPUT ;
    USE SIGNAL ;
    PORT
      LAYER M5 ;
        RECT  74.46 0 74.484 0.192 ;
    END
  END g_front_1_u_front__q_data_in[173]
  PIN g_front_1_u_front__q_data_in[174]
    DIRECTION INPUT ;
    USE SIGNAL ;
    PORT
      LAYER M5 ;
        RECT  74.796 0 74.82 0.192 ;
    END
  END g_front_1_u_front__q_data_in[174]
  PIN g_front_1_u_front__q_data_in[175]
    DIRECTION INPUT ;
    USE SIGNAL ;
    PORT
      LAYER M5 ;
        RECT  75.18 0 75.204 0.192 ;
    END
  END g_front_1_u_front__q_data_in[175]
  PIN g_front_1_u_front__q_data_in[176]
    DIRECTION INPUT ;
    USE SIGNAL ;
    PORT
      LAYER M5 ;
        RECT  75.516 0 75.54 0.192 ;
    END
  END g_front_1_u_front__q_data_in[176]
  PIN g_front_1_u_front__q_data_in[177]
    DIRECTION INPUT ;
    USE SIGNAL ;
    PORT
      LAYER M5 ;
        RECT  75.852 0 75.876 0.192 ;
    END
  END g_front_1_u_front__q_data_in[177]
  PIN g_front_1_u_front__q_data_in[178]
    DIRECTION INPUT ;
    USE SIGNAL ;
    PORT
      LAYER M5 ;
        RECT  76.188 0 76.212 0.192 ;
    END
  END g_front_1_u_front__q_data_in[178]
  PIN g_front_1_u_front__q_data_in[179]
    DIRECTION INPUT ;
    USE SIGNAL ;
    PORT
      LAYER M5 ;
        RECT  76.524 0 76.548 0.192 ;
    END
  END g_front_1_u_front__q_data_in[179]
  PIN g_front_1_u_front__q_data_in[17]
    DIRECTION INPUT ;
    USE SIGNAL ;
    PORT
      LAYER M5 ;
        RECT  21.132 0 21.156 0.192 ;
    END
  END g_front_1_u_front__q_data_in[17]
  PIN g_front_1_u_front__q_data_in[180]
    DIRECTION INPUT ;
    USE SIGNAL ;
    PORT
      LAYER M5 ;
        RECT  76.86 0 76.884 0.192 ;
    END
  END g_front_1_u_front__q_data_in[180]
  PIN g_front_1_u_front__q_data_in[181]
    DIRECTION INPUT ;
    USE SIGNAL ;
    PORT
      LAYER M5 ;
        RECT  77.196 0 77.22 0.192 ;
    END
  END g_front_1_u_front__q_data_in[181]
  PIN g_front_1_u_front__q_data_in[182]
    DIRECTION INPUT ;
    USE SIGNAL ;
    PORT
      LAYER M5 ;
        RECT  77.532 0 77.556 0.192 ;
    END
  END g_front_1_u_front__q_data_in[182]
  PIN g_front_1_u_front__q_data_in[183]
    DIRECTION INPUT ;
    USE SIGNAL ;
    PORT
      LAYER M5 ;
        RECT  77.916 0 77.94 0.192 ;
    END
  END g_front_1_u_front__q_data_in[183]
  PIN g_front_1_u_front__q_data_in[184]
    DIRECTION INPUT ;
    USE SIGNAL ;
    PORT
      LAYER M5 ;
        RECT  78.252 0 78.276 0.192 ;
    END
  END g_front_1_u_front__q_data_in[184]
  PIN g_front_1_u_front__q_data_in[185]
    DIRECTION INPUT ;
    USE SIGNAL ;
    PORT
      LAYER M5 ;
        RECT  78.588 0 78.612 0.192 ;
    END
  END g_front_1_u_front__q_data_in[185]
  PIN g_front_1_u_front__q_data_in[186]
    DIRECTION INPUT ;
    USE SIGNAL ;
    PORT
      LAYER M5 ;
        RECT  78.924 0 78.948 0.192 ;
    END
  END g_front_1_u_front__q_data_in[186]
  PIN g_front_1_u_front__q_data_in[187]
    DIRECTION INPUT ;
    USE SIGNAL ;
    PORT
      LAYER M5 ;
        RECT  79.26 0 79.284 0.192 ;
    END
  END g_front_1_u_front__q_data_in[187]
  PIN g_front_1_u_front__q_data_in[188]
    DIRECTION INPUT ;
    USE SIGNAL ;
    PORT
      LAYER M5 ;
        RECT  79.596 0 79.62 0.192 ;
    END
  END g_front_1_u_front__q_data_in[188]
  PIN g_front_1_u_front__q_data_in[189]
    DIRECTION INPUT ;
    USE SIGNAL ;
    PORT
      LAYER M5 ;
        RECT  79.932 0 79.956 0.192 ;
    END
  END g_front_1_u_front__q_data_in[189]
  PIN g_front_1_u_front__q_data_in[18]
    DIRECTION INPUT ;
    USE SIGNAL ;
    PORT
      LAYER M5 ;
        RECT  21.468 0 21.492 0.192 ;
    END
  END g_front_1_u_front__q_data_in[18]
  PIN g_front_1_u_front__q_data_in[190]
    DIRECTION INPUT ;
    USE SIGNAL ;
    PORT
      LAYER M5 ;
        RECT  80.268 0 80.292 0.192 ;
    END
  END g_front_1_u_front__q_data_in[190]
  PIN g_front_1_u_front__q_data_in[191]
    DIRECTION INPUT ;
    USE SIGNAL ;
    PORT
      LAYER M5 ;
        RECT  80.652 0 80.676 0.192 ;
    END
  END g_front_1_u_front__q_data_in[191]
  PIN g_front_1_u_front__q_data_in[192]
    DIRECTION INPUT ;
    USE SIGNAL ;
    PORT
      LAYER M5 ;
        RECT  80.988 0 81.012 0.192 ;
    END
  END g_front_1_u_front__q_data_in[192]
  PIN g_front_1_u_front__q_data_in[193]
    DIRECTION INPUT ;
    USE SIGNAL ;
    PORT
      LAYER M5 ;
        RECT  81.324 0 81.348 0.192 ;
    END
  END g_front_1_u_front__q_data_in[193]
  PIN g_front_1_u_front__q_data_in[194]
    DIRECTION INPUT ;
    USE SIGNAL ;
    PORT
      LAYER M5 ;
        RECT  81.66 0 81.684 0.192 ;
    END
  END g_front_1_u_front__q_data_in[194]
  PIN g_front_1_u_front__q_data_in[195]
    DIRECTION INPUT ;
    USE SIGNAL ;
    PORT
      LAYER M5 ;
        RECT  81.996 0 82.02 0.192 ;
    END
  END g_front_1_u_front__q_data_in[195]
  PIN g_front_1_u_front__q_data_in[196]
    DIRECTION INPUT ;
    USE SIGNAL ;
    PORT
      LAYER M5 ;
        RECT  82.332 0 82.356 0.192 ;
    END
  END g_front_1_u_front__q_data_in[196]
  PIN g_front_1_u_front__q_data_in[197]
    DIRECTION INPUT ;
    USE SIGNAL ;
    PORT
      LAYER M5 ;
        RECT  82.668 0 82.692 0.192 ;
    END
  END g_front_1_u_front__q_data_in[197]
  PIN g_front_1_u_front__q_data_in[198]
    DIRECTION INPUT ;
    USE SIGNAL ;
    PORT
      LAYER M5 ;
        RECT  83.004 0 83.028 0.192 ;
    END
  END g_front_1_u_front__q_data_in[198]
  PIN g_front_1_u_front__q_data_in[199]
    DIRECTION INPUT ;
    USE SIGNAL ;
    PORT
      LAYER M5 ;
        RECT  83.388 0 83.412 0.192 ;
    END
  END g_front_1_u_front__q_data_in[199]
  PIN g_front_1_u_front__q_data_in[19]
    DIRECTION INPUT ;
    USE SIGNAL ;
    PORT
      LAYER M5 ;
        RECT  21.804 0 21.828 0.192 ;
    END
  END g_front_1_u_front__q_data_in[19]
  PIN g_front_1_u_front__q_data_in[1]
    DIRECTION INPUT ;
    USE SIGNAL ;
    PORT
      LAYER M5 ;
        RECT  15.66 0 15.684 0.192 ;
    END
  END g_front_1_u_front__q_data_in[1]
  PIN g_front_1_u_front__q_data_in[200]
    DIRECTION INPUT ;
    USE SIGNAL ;
    PORT
      LAYER M5 ;
        RECT  83.724 0 83.748 0.192 ;
    END
  END g_front_1_u_front__q_data_in[200]
  PIN g_front_1_u_front__q_data_in[201]
    DIRECTION INPUT ;
    USE SIGNAL ;
    PORT
      LAYER M5 ;
        RECT  84.06 0 84.084 0.192 ;
    END
  END g_front_1_u_front__q_data_in[201]
  PIN g_front_1_u_front__q_data_in[202]
    DIRECTION INPUT ;
    USE SIGNAL ;
    PORT
      LAYER M5 ;
        RECT  84.396 0 84.42 0.192 ;
    END
  END g_front_1_u_front__q_data_in[202]
  PIN g_front_1_u_front__q_data_in[203]
    DIRECTION INPUT ;
    USE SIGNAL ;
    PORT
      LAYER M5 ;
        RECT  84.732 0 84.756 0.192 ;
    END
  END g_front_1_u_front__q_data_in[203]
  PIN g_front_1_u_front__q_data_in[204]
    DIRECTION INPUT ;
    USE SIGNAL ;
    PORT
      LAYER M5 ;
        RECT  85.068 0 85.092 0.192 ;
    END
  END g_front_1_u_front__q_data_in[204]
  PIN g_front_1_u_front__q_data_in[205]
    DIRECTION INPUT ;
    USE SIGNAL ;
    PORT
      LAYER M5 ;
        RECT  85.404 0 85.428 0.192 ;
    END
  END g_front_1_u_front__q_data_in[205]
  PIN g_front_1_u_front__q_data_in[206]
    DIRECTION INPUT ;
    USE SIGNAL ;
    PORT
      LAYER M5 ;
        RECT  85.74 0 85.764 0.192 ;
    END
  END g_front_1_u_front__q_data_in[206]
  PIN g_front_1_u_front__q_data_in[207]
    DIRECTION INPUT ;
    USE SIGNAL ;
    PORT
      LAYER M5 ;
        RECT  86.124 0 86.148 0.192 ;
    END
  END g_front_1_u_front__q_data_in[207]
  PIN g_front_1_u_front__q_data_in[208]
    DIRECTION INPUT ;
    USE SIGNAL ;
    PORT
      LAYER M5 ;
        RECT  86.46 0 86.484 0.192 ;
    END
  END g_front_1_u_front__q_data_in[208]
  PIN g_front_1_u_front__q_data_in[209]
    DIRECTION INPUT ;
    USE SIGNAL ;
    PORT
      LAYER M5 ;
        RECT  86.796 0 86.82 0.192 ;
    END
  END g_front_1_u_front__q_data_in[209]
  PIN g_front_1_u_front__q_data_in[20]
    DIRECTION INPUT ;
    USE SIGNAL ;
    PORT
      LAYER M5 ;
        RECT  22.14 0 22.164 0.192 ;
    END
  END g_front_1_u_front__q_data_in[20]
  PIN g_front_1_u_front__q_data_in[210]
    DIRECTION INPUT ;
    USE SIGNAL ;
    PORT
      LAYER M5 ;
        RECT  87.132 0 87.156 0.192 ;
    END
  END g_front_1_u_front__q_data_in[210]
  PIN g_front_1_u_front__q_data_in[211]
    DIRECTION INPUT ;
    USE SIGNAL ;
    PORT
      LAYER M5 ;
        RECT  87.468 0 87.492 0.192 ;
    END
  END g_front_1_u_front__q_data_in[211]
  PIN g_front_1_u_front__q_data_in[212]
    DIRECTION INPUT ;
    USE SIGNAL ;
    PORT
      LAYER M5 ;
        RECT  87.804 0 87.828 0.192 ;
    END
  END g_front_1_u_front__q_data_in[212]
  PIN g_front_1_u_front__q_data_in[213]
    DIRECTION INPUT ;
    USE SIGNAL ;
    PORT
      LAYER M5 ;
        RECT  88.14 0 88.164 0.192 ;
    END
  END g_front_1_u_front__q_data_in[213]
  PIN g_front_1_u_front__q_data_in[214]
    DIRECTION INPUT ;
    USE SIGNAL ;
    PORT
      LAYER M5 ;
        RECT  88.476 0 88.5 0.192 ;
    END
  END g_front_1_u_front__q_data_in[214]
  PIN g_front_1_u_front__q_data_in[215]
    DIRECTION INPUT ;
    USE SIGNAL ;
    PORT
      LAYER M5 ;
        RECT  88.86 0 88.884 0.192 ;
    END
  END g_front_1_u_front__q_data_in[215]
  PIN g_front_1_u_front__q_data_in[216]
    DIRECTION INPUT ;
    USE SIGNAL ;
    PORT
      LAYER M5 ;
        RECT  89.196 0 89.22 0.192 ;
    END
  END g_front_1_u_front__q_data_in[216]
  PIN g_front_1_u_front__q_data_in[217]
    DIRECTION INPUT ;
    USE SIGNAL ;
    PORT
      LAYER M5 ;
        RECT  89.532 0 89.556 0.192 ;
    END
  END g_front_1_u_front__q_data_in[217]
  PIN g_front_1_u_front__q_data_in[218]
    DIRECTION INPUT ;
    USE SIGNAL ;
    PORT
      LAYER M5 ;
        RECT  89.868 0 89.892 0.192 ;
    END
  END g_front_1_u_front__q_data_in[218]
  PIN g_front_1_u_front__q_data_in[219]
    DIRECTION INPUT ;
    USE SIGNAL ;
    PORT
      LAYER M5 ;
        RECT  90.204 0 90.228 0.192 ;
    END
  END g_front_1_u_front__q_data_in[219]
  PIN g_front_1_u_front__q_data_in[21]
    DIRECTION INPUT ;
    USE SIGNAL ;
    PORT
      LAYER M5 ;
        RECT  22.476 0 22.5 0.192 ;
    END
  END g_front_1_u_front__q_data_in[21]
  PIN g_front_1_u_front__q_data_in[220]
    DIRECTION INPUT ;
    USE SIGNAL ;
    PORT
      LAYER M5 ;
        RECT  90.54 0 90.564 0.192 ;
    END
  END g_front_1_u_front__q_data_in[220]
  PIN g_front_1_u_front__q_data_in[221]
    DIRECTION INPUT ;
    USE SIGNAL ;
    PORT
      LAYER M5 ;
        RECT  90.876 0 90.9 0.192 ;
    END
  END g_front_1_u_front__q_data_in[221]
  PIN g_front_1_u_front__q_data_in[222]
    DIRECTION INPUT ;
    USE SIGNAL ;
    PORT
      LAYER M5 ;
        RECT  91.212 0 91.236 0.192 ;
    END
  END g_front_1_u_front__q_data_in[222]
  PIN g_front_1_u_front__q_data_in[223]
    DIRECTION INPUT ;
    USE SIGNAL ;
    PORT
      LAYER M5 ;
        RECT  91.596 0 91.62 0.192 ;
    END
  END g_front_1_u_front__q_data_in[223]
  PIN g_front_1_u_front__q_data_in[224]
    DIRECTION INPUT ;
    USE SIGNAL ;
    PORT
      LAYER M5 ;
        RECT  91.932 0 91.956 0.192 ;
    END
  END g_front_1_u_front__q_data_in[224]
  PIN g_front_1_u_front__q_data_in[225]
    DIRECTION INPUT ;
    USE SIGNAL ;
    PORT
      LAYER M5 ;
        RECT  92.268 0 92.292 0.192 ;
    END
  END g_front_1_u_front__q_data_in[225]
  PIN g_front_1_u_front__q_data_in[226]
    DIRECTION INPUT ;
    USE SIGNAL ;
    PORT
      LAYER M5 ;
        RECT  92.604 0 92.628 0.192 ;
    END
  END g_front_1_u_front__q_data_in[226]
  PIN g_front_1_u_front__q_data_in[227]
    DIRECTION INPUT ;
    USE SIGNAL ;
    PORT
      LAYER M5 ;
        RECT  92.94 0 92.964 0.192 ;
    END
  END g_front_1_u_front__q_data_in[227]
  PIN g_front_1_u_front__q_data_in[228]
    DIRECTION INPUT ;
    USE SIGNAL ;
    PORT
      LAYER M5 ;
        RECT  93.276 0 93.3 0.192 ;
    END
  END g_front_1_u_front__q_data_in[228]
  PIN g_front_1_u_front__q_data_in[229]
    DIRECTION INPUT ;
    USE SIGNAL ;
    PORT
      LAYER M5 ;
        RECT  93.612 0 93.636 0.192 ;
    END
  END g_front_1_u_front__q_data_in[229]
  PIN g_front_1_u_front__q_data_in[22]
    DIRECTION INPUT ;
    USE SIGNAL ;
    PORT
      LAYER M5 ;
        RECT  22.86 0 22.884 0.192 ;
    END
  END g_front_1_u_front__q_data_in[22]
  PIN g_front_1_u_front__q_data_in[230]
    DIRECTION INPUT ;
    USE SIGNAL ;
    PORT
      LAYER M5 ;
        RECT  93.948 0 93.972 0.192 ;
    END
  END g_front_1_u_front__q_data_in[230]
  PIN g_front_1_u_front__q_data_in[231]
    DIRECTION INPUT ;
    USE SIGNAL ;
    PORT
      LAYER M5 ;
        RECT  94.332 0 94.356 0.192 ;
    END
  END g_front_1_u_front__q_data_in[231]
  PIN g_front_1_u_front__q_data_in[232]
    DIRECTION INPUT ;
    USE SIGNAL ;
    PORT
      LAYER M5 ;
        RECT  94.668 0 94.692 0.192 ;
    END
  END g_front_1_u_front__q_data_in[232]
  PIN g_front_1_u_front__q_data_in[233]
    DIRECTION INPUT ;
    USE SIGNAL ;
    PORT
      LAYER M5 ;
        RECT  95.004 0 95.028 0.192 ;
    END
  END g_front_1_u_front__q_data_in[233]
  PIN g_front_1_u_front__q_data_in[234]
    DIRECTION INPUT ;
    USE SIGNAL ;
    PORT
      LAYER M5 ;
        RECT  95.34 0 95.364 0.192 ;
    END
  END g_front_1_u_front__q_data_in[234]
  PIN g_front_1_u_front__q_data_in[235]
    DIRECTION INPUT ;
    USE SIGNAL ;
    PORT
      LAYER M5 ;
        RECT  95.676 0 95.7 0.192 ;
    END
  END g_front_1_u_front__q_data_in[235]
  PIN g_front_1_u_front__q_data_in[236]
    DIRECTION INPUT ;
    USE SIGNAL ;
    PORT
      LAYER M5 ;
        RECT  96.012 0 96.036 0.192 ;
    END
  END g_front_1_u_front__q_data_in[236]
  PIN g_front_1_u_front__q_data_in[237]
    DIRECTION INPUT ;
    USE SIGNAL ;
    PORT
      LAYER M5 ;
        RECT  96.348 0 96.372 0.192 ;
    END
  END g_front_1_u_front__q_data_in[237]
  PIN g_front_1_u_front__q_data_in[238]
    DIRECTION INPUT ;
    USE SIGNAL ;
    PORT
      LAYER M5 ;
        RECT  96.684 0 96.708 0.192 ;
    END
  END g_front_1_u_front__q_data_in[238]
  PIN g_front_1_u_front__q_data_in[239]
    DIRECTION INPUT ;
    USE SIGNAL ;
    PORT
      LAYER M5 ;
        RECT  97.068 0 97.092 0.192 ;
    END
  END g_front_1_u_front__q_data_in[239]
  PIN g_front_1_u_front__q_data_in[23]
    DIRECTION INPUT ;
    USE SIGNAL ;
    PORT
      LAYER M5 ;
        RECT  23.196 0 23.22 0.192 ;
    END
  END g_front_1_u_front__q_data_in[23]
  PIN g_front_1_u_front__q_data_in[240]
    DIRECTION INPUT ;
    USE SIGNAL ;
    PORT
      LAYER M5 ;
        RECT  97.404 0 97.428 0.192 ;
    END
  END g_front_1_u_front__q_data_in[240]
  PIN g_front_1_u_front__q_data_in[241]
    DIRECTION INPUT ;
    USE SIGNAL ;
    PORT
      LAYER M5 ;
        RECT  97.74 0 97.764 0.192 ;
    END
  END g_front_1_u_front__q_data_in[241]
  PIN g_front_1_u_front__q_data_in[242]
    DIRECTION INPUT ;
    USE SIGNAL ;
    PORT
      LAYER M5 ;
        RECT  98.076 0 98.1 0.192 ;
    END
  END g_front_1_u_front__q_data_in[242]
  PIN g_front_1_u_front__q_data_in[243]
    DIRECTION INPUT ;
    USE SIGNAL ;
    PORT
      LAYER M5 ;
        RECT  98.412 0 98.436 0.192 ;
    END
  END g_front_1_u_front__q_data_in[243]
  PIN g_front_1_u_front__q_data_in[244]
    DIRECTION INPUT ;
    USE SIGNAL ;
    PORT
      LAYER M5 ;
        RECT  98.748 0 98.772 0.192 ;
    END
  END g_front_1_u_front__q_data_in[244]
  PIN g_front_1_u_front__q_data_in[245]
    DIRECTION INPUT ;
    USE SIGNAL ;
    PORT
      LAYER M5 ;
        RECT  99.084 0 99.108 0.192 ;
    END
  END g_front_1_u_front__q_data_in[245]
  PIN g_front_1_u_front__q_data_in[246]
    DIRECTION INPUT ;
    USE SIGNAL ;
    PORT
      LAYER M5 ;
        RECT  99.42 0 99.444 0.192 ;
    END
  END g_front_1_u_front__q_data_in[246]
  PIN g_front_1_u_front__q_data_in[247]
    DIRECTION INPUT ;
    USE SIGNAL ;
    PORT
      LAYER M5 ;
        RECT  99.804 0 99.828 0.192 ;
    END
  END g_front_1_u_front__q_data_in[247]
  PIN g_front_1_u_front__q_data_in[248]
    DIRECTION INPUT ;
    USE SIGNAL ;
    PORT
      LAYER M5 ;
        RECT  100.14 0 100.164 0.192 ;
    END
  END g_front_1_u_front__q_data_in[248]
  PIN g_front_1_u_front__q_data_in[249]
    DIRECTION INPUT ;
    USE SIGNAL ;
    PORT
      LAYER M5 ;
        RECT  100.476 0 100.5 0.192 ;
    END
  END g_front_1_u_front__q_data_in[249]
  PIN g_front_1_u_front__q_data_in[24]
    DIRECTION INPUT ;
    USE SIGNAL ;
    PORT
      LAYER M5 ;
        RECT  23.532 0 23.556 0.192 ;
    END
  END g_front_1_u_front__q_data_in[24]
  PIN g_front_1_u_front__q_data_in[250]
    DIRECTION INPUT ;
    USE SIGNAL ;
    PORT
      LAYER M5 ;
        RECT  100.812 0 100.836 0.192 ;
    END
  END g_front_1_u_front__q_data_in[250]
  PIN g_front_1_u_front__q_data_in[251]
    DIRECTION INPUT ;
    USE SIGNAL ;
    PORT
      LAYER M5 ;
        RECT  101.148 0 101.172 0.192 ;
    END
  END g_front_1_u_front__q_data_in[251]
  PIN g_front_1_u_front__q_data_in[252]
    DIRECTION INPUT ;
    USE SIGNAL ;
    PORT
      LAYER M5 ;
        RECT  101.484 0 101.508 0.192 ;
    END
  END g_front_1_u_front__q_data_in[252]
  PIN g_front_1_u_front__q_data_in[253]
    DIRECTION INPUT ;
    USE SIGNAL ;
    PORT
      LAYER M5 ;
        RECT  101.82 0 101.844 0.192 ;
    END
  END g_front_1_u_front__q_data_in[253]
  PIN g_front_1_u_front__q_data_in[254]
    DIRECTION INPUT ;
    USE SIGNAL ;
    PORT
      LAYER M5 ;
        RECT  102.156 0 102.18 0.192 ;
    END
  END g_front_1_u_front__q_data_in[254]
  PIN g_front_1_u_front__q_data_in[255]
    DIRECTION INPUT ;
    USE SIGNAL ;
    PORT
      LAYER M5 ;
        RECT  102.54 0 102.564 0.192 ;
    END
  END g_front_1_u_front__q_data_in[255]
  PIN g_front_1_u_front__q_data_in[256]
    DIRECTION INPUT ;
    USE SIGNAL ;
    PORT
      LAYER M5 ;
        RECT  102.876 0 102.9 0.192 ;
    END
  END g_front_1_u_front__q_data_in[256]
  PIN g_front_1_u_front__q_data_in[257]
    DIRECTION INPUT ;
    USE SIGNAL ;
    PORT
      LAYER M5 ;
        RECT  103.212 0 103.236 0.192 ;
    END
  END g_front_1_u_front__q_data_in[257]
  PIN g_front_1_u_front__q_data_in[258]
    DIRECTION INPUT ;
    USE SIGNAL ;
    PORT
      LAYER M5 ;
        RECT  103.548 0 103.572 0.192 ;
    END
  END g_front_1_u_front__q_data_in[258]
  PIN g_front_1_u_front__q_data_in[259]
    DIRECTION INPUT ;
    USE SIGNAL ;
    PORT
      LAYER M5 ;
        RECT  103.884 0 103.908 0.192 ;
    END
  END g_front_1_u_front__q_data_in[259]
  PIN g_front_1_u_front__q_data_in[25]
    DIRECTION INPUT ;
    USE SIGNAL ;
    PORT
      LAYER M5 ;
        RECT  23.868 0 23.892 0.192 ;
    END
  END g_front_1_u_front__q_data_in[25]
  PIN g_front_1_u_front__q_data_in[260]
    DIRECTION INPUT ;
    USE SIGNAL ;
    PORT
      LAYER M5 ;
        RECT  104.22 0 104.244 0.192 ;
    END
  END g_front_1_u_front__q_data_in[260]
  PIN g_front_1_u_front__q_data_in[261]
    DIRECTION INPUT ;
    USE SIGNAL ;
    PORT
      LAYER M5 ;
        RECT  104.556 0 104.58 0.192 ;
    END
  END g_front_1_u_front__q_data_in[261]
  PIN g_front_1_u_front__q_data_in[262]
    DIRECTION INPUT ;
    USE SIGNAL ;
    PORT
      LAYER M5 ;
        RECT  104.892 0 104.916 0.192 ;
    END
  END g_front_1_u_front__q_data_in[262]
  PIN g_front_1_u_front__q_data_in[263]
    DIRECTION INPUT ;
    USE SIGNAL ;
    PORT
      LAYER M5 ;
        RECT  105.276 0 105.3 0.192 ;
    END
  END g_front_1_u_front__q_data_in[263]
  PIN g_front_1_u_front__q_data_in[264]
    DIRECTION INPUT ;
    USE SIGNAL ;
    PORT
      LAYER M5 ;
        RECT  105.612 0 105.636 0.192 ;
    END
  END g_front_1_u_front__q_data_in[264]
  PIN g_front_1_u_front__q_data_in[265]
    DIRECTION INPUT ;
    USE SIGNAL ;
    PORT
      LAYER M5 ;
        RECT  105.948 0 105.972 0.192 ;
    END
  END g_front_1_u_front__q_data_in[265]
  PIN g_front_1_u_front__q_data_in[266]
    DIRECTION INPUT ;
    USE SIGNAL ;
    PORT
      LAYER M5 ;
        RECT  106.284 0 106.308 0.192 ;
    END
  END g_front_1_u_front__q_data_in[266]
  PIN g_front_1_u_front__q_data_in[267]
    DIRECTION INPUT ;
    USE SIGNAL ;
    PORT
      LAYER M5 ;
        RECT  106.62 0 106.644 0.192 ;
    END
  END g_front_1_u_front__q_data_in[267]
  PIN g_front_1_u_front__q_data_in[268]
    DIRECTION INPUT ;
    USE SIGNAL ;
    PORT
      LAYER M5 ;
        RECT  106.956 0 106.98 0.192 ;
    END
  END g_front_1_u_front__q_data_in[268]
  PIN g_front_1_u_front__q_data_in[269]
    DIRECTION INPUT ;
    USE SIGNAL ;
    PORT
      LAYER M5 ;
        RECT  107.292 0 107.316 0.192 ;
    END
  END g_front_1_u_front__q_data_in[269]
  PIN g_front_1_u_front__q_data_in[26]
    DIRECTION INPUT ;
    USE SIGNAL ;
    PORT
      LAYER M5 ;
        RECT  24.204 0 24.228 0.192 ;
    END
  END g_front_1_u_front__q_data_in[26]
  PIN g_front_1_u_front__q_data_in[270]
    DIRECTION INPUT ;
    USE SIGNAL ;
    PORT
      LAYER M5 ;
        RECT  107.628 0 107.652 0.192 ;
    END
  END g_front_1_u_front__q_data_in[270]
  PIN g_front_1_u_front__q_data_in[271]
    DIRECTION INPUT ;
    USE SIGNAL ;
    PORT
      LAYER M5 ;
        RECT  108.012 0 108.036 0.192 ;
    END
  END g_front_1_u_front__q_data_in[271]
  PIN g_front_1_u_front__q_data_in[272]
    DIRECTION INPUT ;
    USE SIGNAL ;
    PORT
      LAYER M5 ;
        RECT  108.348 0 108.372 0.192 ;
    END
  END g_front_1_u_front__q_data_in[272]
  PIN g_front_1_u_front__q_data_in[273]
    DIRECTION INPUT ;
    USE SIGNAL ;
    PORT
      LAYER M5 ;
        RECT  108.684 0 108.708 0.192 ;
    END
  END g_front_1_u_front__q_data_in[273]
  PIN g_front_1_u_front__q_data_in[274]
    DIRECTION INPUT ;
    USE SIGNAL ;
    PORT
      LAYER M5 ;
        RECT  109.02 0 109.044 0.192 ;
    END
  END g_front_1_u_front__q_data_in[274]
  PIN g_front_1_u_front__q_data_in[275]
    DIRECTION INPUT ;
    USE SIGNAL ;
    PORT
      LAYER M5 ;
        RECT  109.356 0 109.38 0.192 ;
    END
  END g_front_1_u_front__q_data_in[275]
  PIN g_front_1_u_front__q_data_in[276]
    DIRECTION INPUT ;
    USE SIGNAL ;
    PORT
      LAYER M5 ;
        RECT  109.692 0 109.716 0.192 ;
    END
  END g_front_1_u_front__q_data_in[276]
  PIN g_front_1_u_front__q_data_in[277]
    DIRECTION INPUT ;
    USE SIGNAL ;
    PORT
      LAYER M5 ;
        RECT  110.028 0 110.052 0.192 ;
    END
  END g_front_1_u_front__q_data_in[277]
  PIN g_front_1_u_front__q_data_in[278]
    DIRECTION INPUT ;
    USE SIGNAL ;
    PORT
      LAYER M5 ;
        RECT  110.364 0 110.388 0.192 ;
    END
  END g_front_1_u_front__q_data_in[278]
  PIN g_front_1_u_front__q_data_in[279]
    DIRECTION INPUT ;
    USE SIGNAL ;
    PORT
      LAYER M5 ;
        RECT  110.7 0 110.724 0.192 ;
    END
  END g_front_1_u_front__q_data_in[279]
  PIN g_front_1_u_front__q_data_in[27]
    DIRECTION INPUT ;
    USE SIGNAL ;
    PORT
      LAYER M5 ;
        RECT  24.54 0 24.564 0.192 ;
    END
  END g_front_1_u_front__q_data_in[27]
  PIN g_front_1_u_front__q_data_in[280]
    DIRECTION INPUT ;
    USE SIGNAL ;
    PORT
      LAYER M5 ;
        RECT  111.084 0 111.108 0.192 ;
    END
  END g_front_1_u_front__q_data_in[280]
  PIN g_front_1_u_front__q_data_in[281]
    DIRECTION INPUT ;
    USE SIGNAL ;
    PORT
      LAYER M5 ;
        RECT  111.42 0 111.444 0.192 ;
    END
  END g_front_1_u_front__q_data_in[281]
  PIN g_front_1_u_front__q_data_in[282]
    DIRECTION INPUT ;
    USE SIGNAL ;
    PORT
      LAYER M5 ;
        RECT  111.756 0 111.78 0.192 ;
    END
  END g_front_1_u_front__q_data_in[282]
  PIN g_front_1_u_front__q_data_in[283]
    DIRECTION INPUT ;
    USE SIGNAL ;
    PORT
      LAYER M5 ;
        RECT  112.092 0 112.116 0.192 ;
    END
  END g_front_1_u_front__q_data_in[283]
  PIN g_front_1_u_front__q_data_in[284]
    DIRECTION INPUT ;
    USE SIGNAL ;
    PORT
      LAYER M5 ;
        RECT  112.428 0 112.452 0.192 ;
    END
  END g_front_1_u_front__q_data_in[284]
  PIN g_front_1_u_front__q_data_in[285]
    DIRECTION INPUT ;
    USE SIGNAL ;
    PORT
      LAYER M5 ;
        RECT  112.764 0 112.788 0.192 ;
    END
  END g_front_1_u_front__q_data_in[285]
  PIN g_front_1_u_front__q_data_in[286]
    DIRECTION INPUT ;
    USE SIGNAL ;
    PORT
      LAYER M5 ;
        RECT  113.1 0 113.124 0.192 ;
    END
  END g_front_1_u_front__q_data_in[286]
  PIN g_front_1_u_front__q_data_in[287]
    DIRECTION INPUT ;
    USE SIGNAL ;
    PORT
      LAYER M5 ;
        RECT  113.436 0 113.46 0.192 ;
    END
  END g_front_1_u_front__q_data_in[287]
  PIN g_front_1_u_front__q_data_in[288]
    DIRECTION INPUT ;
    USE SIGNAL ;
    PORT
      LAYER M5 ;
        RECT  113.82 0 113.844 0.192 ;
    END
  END g_front_1_u_front__q_data_in[288]
  PIN g_front_1_u_front__q_data_in[289]
    DIRECTION INPUT ;
    USE SIGNAL ;
    PORT
      LAYER M5 ;
        RECT  114.156 0 114.18 0.192 ;
    END
  END g_front_1_u_front__q_data_in[289]
  PIN g_front_1_u_front__q_data_in[28]
    DIRECTION INPUT ;
    USE SIGNAL ;
    PORT
      LAYER M5 ;
        RECT  24.876 0 24.9 0.192 ;
    END
  END g_front_1_u_front__q_data_in[28]
  PIN g_front_1_u_front__q_data_in[290]
    DIRECTION INPUT ;
    USE SIGNAL ;
    PORT
      LAYER M5 ;
        RECT  114.492 0 114.516 0.192 ;
    END
  END g_front_1_u_front__q_data_in[290]
  PIN g_front_1_u_front__q_data_in[291]
    DIRECTION INPUT ;
    USE SIGNAL ;
    PORT
      LAYER M5 ;
        RECT  114.828 0 114.852 0.192 ;
    END
  END g_front_1_u_front__q_data_in[291]
  PIN g_front_1_u_front__q_data_in[292]
    DIRECTION INPUT ;
    USE SIGNAL ;
    PORT
      LAYER M5 ;
        RECT  115.164 0 115.188 0.192 ;
    END
  END g_front_1_u_front__q_data_in[292]
  PIN g_front_1_u_front__q_data_in[293]
    DIRECTION INPUT ;
    USE SIGNAL ;
    PORT
      LAYER M5 ;
        RECT  115.5 0 115.524 0.192 ;
    END
  END g_front_1_u_front__q_data_in[293]
  PIN g_front_1_u_front__q_data_in[294]
    DIRECTION INPUT ;
    USE SIGNAL ;
    PORT
      LAYER M5 ;
        RECT  115.836 0 115.86 0.192 ;
    END
  END g_front_1_u_front__q_data_in[294]
  PIN g_front_1_u_front__q_data_in[295]
    DIRECTION INPUT ;
    USE SIGNAL ;
    PORT
      LAYER M5 ;
        RECT  116.172 0 116.196 0.192 ;
    END
  END g_front_1_u_front__q_data_in[295]
  PIN g_front_1_u_front__q_data_in[296]
    DIRECTION INPUT ;
    USE SIGNAL ;
    PORT
      LAYER M5 ;
        RECT  116.556 0 116.58 0.192 ;
    END
  END g_front_1_u_front__q_data_in[296]
  PIN g_front_1_u_front__q_data_in[297]
    DIRECTION INPUT ;
    USE SIGNAL ;
    PORT
      LAYER M5 ;
        RECT  116.892 0 116.916 0.192 ;
    END
  END g_front_1_u_front__q_data_in[297]
  PIN g_front_1_u_front__q_data_in[298]
    DIRECTION INPUT ;
    USE SIGNAL ;
    PORT
      LAYER M5 ;
        RECT  117.228 0 117.252 0.192 ;
    END
  END g_front_1_u_front__q_data_in[298]
  PIN g_front_1_u_front__q_data_in[299]
    DIRECTION INPUT ;
    USE SIGNAL ;
    PORT
      LAYER M5 ;
        RECT  117.564 0 117.588 0.192 ;
    END
  END g_front_1_u_front__q_data_in[299]
  PIN g_front_1_u_front__q_data_in[29]
    DIRECTION INPUT ;
    USE SIGNAL ;
    PORT
      LAYER M5 ;
        RECT  25.212 0 25.236 0.192 ;
    END
  END g_front_1_u_front__q_data_in[29]
  PIN g_front_1_u_front__q_data_in[2]
    DIRECTION INPUT ;
    USE SIGNAL ;
    PORT
      LAYER M5 ;
        RECT  15.996 0 16.02 0.192 ;
    END
  END g_front_1_u_front__q_data_in[2]
  PIN g_front_1_u_front__q_data_in[300]
    DIRECTION INPUT ;
    USE SIGNAL ;
    PORT
      LAYER M5 ;
        RECT  117.9 0 117.924 0.192 ;
    END
  END g_front_1_u_front__q_data_in[300]
  PIN g_front_1_u_front__q_data_in[301]
    DIRECTION INPUT ;
    USE SIGNAL ;
    PORT
      LAYER M5 ;
        RECT  118.236 0 118.26 0.192 ;
    END
  END g_front_1_u_front__q_data_in[301]
  PIN g_front_1_u_front__q_data_in[302]
    DIRECTION INPUT ;
    USE SIGNAL ;
    PORT
      LAYER M5 ;
        RECT  118.572 0 118.596 0.192 ;
    END
  END g_front_1_u_front__q_data_in[302]
  PIN g_front_1_u_front__q_data_in[303]
    DIRECTION INPUT ;
    USE SIGNAL ;
    PORT
      LAYER M5 ;
        RECT  118.908 0 118.932 0.192 ;
    END
  END g_front_1_u_front__q_data_in[303]
  PIN g_front_1_u_front__q_data_in[304]
    DIRECTION INPUT ;
    USE SIGNAL ;
    PORT
      LAYER M5 ;
        RECT  119.292 0 119.316 0.192 ;
    END
  END g_front_1_u_front__q_data_in[304]
  PIN g_front_1_u_front__q_data_in[305]
    DIRECTION INPUT ;
    USE SIGNAL ;
    PORT
      LAYER M5 ;
        RECT  119.628 0 119.652 0.192 ;
    END
  END g_front_1_u_front__q_data_in[305]
  PIN g_front_1_u_front__q_data_in[306]
    DIRECTION INPUT ;
    USE SIGNAL ;
    PORT
      LAYER M5 ;
        RECT  119.964 0 119.988 0.192 ;
    END
  END g_front_1_u_front__q_data_in[306]
  PIN g_front_1_u_front__q_data_in[307]
    DIRECTION INPUT ;
    USE SIGNAL ;
    PORT
      LAYER M5 ;
        RECT  120.3 0 120.324 0.192 ;
    END
  END g_front_1_u_front__q_data_in[307]
  PIN g_front_1_u_front__q_data_in[308]
    DIRECTION INPUT ;
    USE SIGNAL ;
    PORT
      LAYER M5 ;
        RECT  120.636 0 120.66 0.192 ;
    END
  END g_front_1_u_front__q_data_in[308]
  PIN g_front_1_u_front__q_data_in[309]
    DIRECTION INPUT ;
    USE SIGNAL ;
    PORT
      LAYER M5 ;
        RECT  120.972 0 120.996 0.192 ;
    END
  END g_front_1_u_front__q_data_in[309]
  PIN g_front_1_u_front__q_data_in[30]
    DIRECTION INPUT ;
    USE SIGNAL ;
    PORT
      LAYER M5 ;
        RECT  25.596 0 25.62 0.192 ;
    END
  END g_front_1_u_front__q_data_in[30]
  PIN g_front_1_u_front__q_data_in[310]
    DIRECTION INPUT ;
    USE SIGNAL ;
    PORT
      LAYER M5 ;
        RECT  121.308 0 121.332 0.192 ;
    END
  END g_front_1_u_front__q_data_in[310]
  PIN g_front_1_u_front__q_data_in[311]
    DIRECTION INPUT ;
    USE SIGNAL ;
    PORT
      LAYER M5 ;
        RECT  121.644 0 121.668 0.192 ;
    END
  END g_front_1_u_front__q_data_in[311]
  PIN g_front_1_u_front__q_data_in[312]
    DIRECTION INPUT ;
    USE SIGNAL ;
    PORT
      LAYER M5 ;
        RECT  122.028 0 122.052 0.192 ;
    END
  END g_front_1_u_front__q_data_in[312]
  PIN g_front_1_u_front__q_data_in[313]
    DIRECTION INPUT ;
    USE SIGNAL ;
    PORT
      LAYER M5 ;
        RECT  122.364 0 122.388 0.192 ;
    END
  END g_front_1_u_front__q_data_in[313]
  PIN g_front_1_u_front__q_data_in[314]
    DIRECTION INPUT ;
    USE SIGNAL ;
    PORT
      LAYER M5 ;
        RECT  122.7 0 122.724 0.192 ;
    END
  END g_front_1_u_front__q_data_in[314]
  PIN g_front_1_u_front__q_data_in[315]
    DIRECTION INPUT ;
    USE SIGNAL ;
    PORT
      LAYER M5 ;
        RECT  123.036 0 123.06 0.192 ;
    END
  END g_front_1_u_front__q_data_in[315]
  PIN g_front_1_u_front__q_data_in[316]
    DIRECTION INPUT ;
    USE SIGNAL ;
    PORT
      LAYER M5 ;
        RECT  123.372 0 123.396 0.192 ;
    END
  END g_front_1_u_front__q_data_in[316]
  PIN g_front_1_u_front__q_data_in[317]
    DIRECTION INPUT ;
    USE SIGNAL ;
    PORT
      LAYER M5 ;
        RECT  123.708 0 123.732 0.192 ;
    END
  END g_front_1_u_front__q_data_in[317]
  PIN g_front_1_u_front__q_data_in[318]
    DIRECTION INPUT ;
    USE SIGNAL ;
    PORT
      LAYER M5 ;
        RECT  124.044 0 124.068 0.192 ;
    END
  END g_front_1_u_front__q_data_in[318]
  PIN g_front_1_u_front__q_data_in[319]
    DIRECTION INPUT ;
    USE SIGNAL ;
    PORT
      LAYER M5 ;
        RECT  124.38 0 124.404 0.192 ;
    END
  END g_front_1_u_front__q_data_in[319]
  PIN g_front_1_u_front__q_data_in[31]
    DIRECTION INPUT ;
    USE SIGNAL ;
    PORT
      LAYER M5 ;
        RECT  25.932 0 25.956 0.192 ;
    END
  END g_front_1_u_front__q_data_in[31]
  PIN g_front_1_u_front__q_data_in[320]
    DIRECTION INPUT ;
    USE SIGNAL ;
    PORT
      LAYER M5 ;
        RECT  124.764 0 124.788 0.192 ;
    END
  END g_front_1_u_front__q_data_in[320]
  PIN g_front_1_u_front__q_data_in[321]
    DIRECTION INPUT ;
    USE SIGNAL ;
    PORT
      LAYER M5 ;
        RECT  125.1 0 125.124 0.192 ;
    END
  END g_front_1_u_front__q_data_in[321]
  PIN g_front_1_u_front__q_data_in[322]
    DIRECTION INPUT ;
    USE SIGNAL ;
    PORT
      LAYER M5 ;
        RECT  125.436 0 125.46 0.192 ;
    END
  END g_front_1_u_front__q_data_in[322]
  PIN g_front_1_u_front__q_data_in[323]
    DIRECTION INPUT ;
    USE SIGNAL ;
    PORT
      LAYER M5 ;
        RECT  125.772 0 125.796 0.192 ;
    END
  END g_front_1_u_front__q_data_in[323]
  PIN g_front_1_u_front__q_data_in[324]
    DIRECTION INPUT ;
    USE SIGNAL ;
    PORT
      LAYER M5 ;
        RECT  126.108 0 126.132 0.192 ;
    END
  END g_front_1_u_front__q_data_in[324]
  PIN g_front_1_u_front__q_data_in[325]
    DIRECTION INPUT ;
    USE SIGNAL ;
    PORT
      LAYER M5 ;
        RECT  126.444 0 126.468 0.192 ;
    END
  END g_front_1_u_front__q_data_in[325]
  PIN g_front_1_u_front__q_data_in[326]
    DIRECTION INPUT ;
    USE SIGNAL ;
    PORT
      LAYER M5 ;
        RECT  126.78 0 126.804 0.192 ;
    END
  END g_front_1_u_front__q_data_in[326]
  PIN g_front_1_u_front__q_data_in[327]
    DIRECTION INPUT ;
    USE SIGNAL ;
    PORT
      LAYER M5 ;
        RECT  127.116 0 127.14 0.192 ;
    END
  END g_front_1_u_front__q_data_in[327]
  PIN g_front_1_u_front__q_data_in[328]
    DIRECTION INPUT ;
    USE SIGNAL ;
    PORT
      LAYER M5 ;
        RECT  127.5 0 127.524 0.192 ;
    END
  END g_front_1_u_front__q_data_in[328]
  PIN g_front_1_u_front__q_data_in[329]
    DIRECTION INPUT ;
    USE SIGNAL ;
    PORT
      LAYER M5 ;
        RECT  127.836 0 127.86 0.192 ;
    END
  END g_front_1_u_front__q_data_in[329]
  PIN g_front_1_u_front__q_data_in[32]
    DIRECTION INPUT ;
    USE SIGNAL ;
    PORT
      LAYER M5 ;
        RECT  26.268 0 26.292 0.192 ;
    END
  END g_front_1_u_front__q_data_in[32]
  PIN g_front_1_u_front__q_data_in[330]
    DIRECTION INPUT ;
    USE SIGNAL ;
    PORT
      LAYER M5 ;
        RECT  128.172 0 128.196 0.192 ;
    END
  END g_front_1_u_front__q_data_in[330]
  PIN g_front_1_u_front__q_data_in[331]
    DIRECTION INPUT ;
    USE SIGNAL ;
    PORT
      LAYER M5 ;
        RECT  128.508 0 128.532 0.192 ;
    END
  END g_front_1_u_front__q_data_in[331]
  PIN g_front_1_u_front__q_data_in[332]
    DIRECTION INPUT ;
    USE SIGNAL ;
    PORT
      LAYER M5 ;
        RECT  128.844 0 128.868 0.192 ;
    END
  END g_front_1_u_front__q_data_in[332]
  PIN g_front_1_u_front__q_data_in[333]
    DIRECTION INPUT ;
    USE SIGNAL ;
    PORT
      LAYER M5 ;
        RECT  129.18 0 129.204 0.192 ;
    END
  END g_front_1_u_front__q_data_in[333]
  PIN g_front_1_u_front__q_data_in[334]
    DIRECTION INPUT ;
    USE SIGNAL ;
    PORT
      LAYER M5 ;
        RECT  129.516 0 129.54 0.192 ;
    END
  END g_front_1_u_front__q_data_in[334]
  PIN g_front_1_u_front__q_data_in[335]
    DIRECTION INPUT ;
    USE SIGNAL ;
    PORT
      LAYER M5 ;
        RECT  129.852 0 129.876 0.192 ;
    END
  END g_front_1_u_front__q_data_in[335]
  PIN g_front_1_u_front__q_data_in[336]
    DIRECTION INPUT ;
    USE SIGNAL ;
    PORT
      LAYER M5 ;
        RECT  130.236 0 130.26 0.192 ;
    END
  END g_front_1_u_front__q_data_in[336]
  PIN g_front_1_u_front__q_data_in[337]
    DIRECTION INPUT ;
    USE SIGNAL ;
    PORT
      LAYER M5 ;
        RECT  130.572 0 130.596 0.192 ;
    END
  END g_front_1_u_front__q_data_in[337]
  PIN g_front_1_u_front__q_data_in[338]
    DIRECTION INPUT ;
    USE SIGNAL ;
    PORT
      LAYER M5 ;
        RECT  130.908 0 130.932 0.192 ;
    END
  END g_front_1_u_front__q_data_in[338]
  PIN g_front_1_u_front__q_data_in[339]
    DIRECTION INPUT ;
    USE SIGNAL ;
    PORT
      LAYER M5 ;
        RECT  131.244 0 131.268 0.192 ;
    END
  END g_front_1_u_front__q_data_in[339]
  PIN g_front_1_u_front__q_data_in[33]
    DIRECTION INPUT ;
    USE SIGNAL ;
    PORT
      LAYER M5 ;
        RECT  26.604 0 26.628 0.192 ;
    END
  END g_front_1_u_front__q_data_in[33]
  PIN g_front_1_u_front__q_data_in[340]
    DIRECTION INPUT ;
    USE SIGNAL ;
    PORT
      LAYER M5 ;
        RECT  131.58 0 131.604 0.192 ;
    END
  END g_front_1_u_front__q_data_in[340]
  PIN g_front_1_u_front__q_data_in[341]
    DIRECTION INPUT ;
    USE SIGNAL ;
    PORT
      LAYER M5 ;
        RECT  131.916 0 131.94 0.192 ;
    END
  END g_front_1_u_front__q_data_in[341]
  PIN g_front_1_u_front__q_data_in[342]
    DIRECTION INPUT ;
    USE SIGNAL ;
    PORT
      LAYER M5 ;
        RECT  132.252 0 132.276 0.192 ;
    END
  END g_front_1_u_front__q_data_in[342]
  PIN g_front_1_u_front__q_data_in[343]
    DIRECTION INPUT ;
    USE SIGNAL ;
    PORT
      LAYER M5 ;
        RECT  132.588 0 132.612 0.192 ;
    END
  END g_front_1_u_front__q_data_in[343]
  PIN g_front_1_u_front__q_data_in[344]
    DIRECTION INPUT ;
    USE SIGNAL ;
    PORT
      LAYER M5 ;
        RECT  132.972 0 132.996 0.192 ;
    END
  END g_front_1_u_front__q_data_in[344]
  PIN g_front_1_u_front__q_data_in[345]
    DIRECTION INPUT ;
    USE SIGNAL ;
    PORT
      LAYER M5 ;
        RECT  133.308 0 133.332 0.192 ;
    END
  END g_front_1_u_front__q_data_in[345]
  PIN g_front_1_u_front__q_data_in[346]
    DIRECTION INPUT ;
    USE SIGNAL ;
    PORT
      LAYER M5 ;
        RECT  133.644 0 133.668 0.192 ;
    END
  END g_front_1_u_front__q_data_in[346]
  PIN g_front_1_u_front__q_data_in[347]
    DIRECTION INPUT ;
    USE SIGNAL ;
    PORT
      LAYER M5 ;
        RECT  133.98 0 134.004 0.192 ;
    END
  END g_front_1_u_front__q_data_in[347]
  PIN g_front_1_u_front__q_data_in[348]
    DIRECTION INPUT ;
    USE SIGNAL ;
    PORT
      LAYER M5 ;
        RECT  134.316 0 134.34 0.192 ;
    END
  END g_front_1_u_front__q_data_in[348]
  PIN g_front_1_u_front__q_data_in[349]
    DIRECTION INPUT ;
    USE SIGNAL ;
    PORT
      LAYER M5 ;
        RECT  134.652 0 134.676 0.192 ;
    END
  END g_front_1_u_front__q_data_in[349]
  PIN g_front_1_u_front__q_data_in[34]
    DIRECTION INPUT ;
    USE SIGNAL ;
    PORT
      LAYER M5 ;
        RECT  26.94 0 26.964 0.192 ;
    END
  END g_front_1_u_front__q_data_in[34]
  PIN g_front_1_u_front__q_data_in[350]
    DIRECTION INPUT ;
    USE SIGNAL ;
    PORT
      LAYER M5 ;
        RECT  134.988 0 135.012 0.192 ;
    END
  END g_front_1_u_front__q_data_in[350]
  PIN g_front_1_u_front__q_data_in[351]
    DIRECTION INPUT ;
    USE SIGNAL ;
    PORT
      LAYER M5 ;
        RECT  135.324 0 135.348 0.192 ;
    END
  END g_front_1_u_front__q_data_in[351]
  PIN g_front_1_u_front__q_data_in[352]
    DIRECTION INPUT ;
    USE SIGNAL ;
    PORT
      LAYER M5 ;
        RECT  135.708 0 135.732 0.192 ;
    END
  END g_front_1_u_front__q_data_in[352]
  PIN g_front_1_u_front__q_data_in[353]
    DIRECTION INPUT ;
    USE SIGNAL ;
    PORT
      LAYER M5 ;
        RECT  136.044 0 136.068 0.192 ;
    END
  END g_front_1_u_front__q_data_in[353]
  PIN g_front_1_u_front__q_data_in[354]
    DIRECTION INPUT ;
    USE SIGNAL ;
    PORT
      LAYER M5 ;
        RECT  136.38 0 136.404 0.192 ;
    END
  END g_front_1_u_front__q_data_in[354]
  PIN g_front_1_u_front__q_data_in[355]
    DIRECTION INPUT ;
    USE SIGNAL ;
    PORT
      LAYER M5 ;
        RECT  136.716 0 136.74 0.192 ;
    END
  END g_front_1_u_front__q_data_in[355]
  PIN g_front_1_u_front__q_data_in[356]
    DIRECTION INPUT ;
    USE SIGNAL ;
    PORT
      LAYER M5 ;
        RECT  137.052 0 137.076 0.192 ;
    END
  END g_front_1_u_front__q_data_in[356]
  PIN g_front_1_u_front__q_data_in[357]
    DIRECTION INPUT ;
    USE SIGNAL ;
    PORT
      LAYER M5 ;
        RECT  137.388 0 137.412 0.192 ;
    END
  END g_front_1_u_front__q_data_in[357]
  PIN g_front_1_u_front__q_data_in[358]
    DIRECTION INPUT ;
    USE SIGNAL ;
    PORT
      LAYER M5 ;
        RECT  137.724 0 137.748 0.192 ;
    END
  END g_front_1_u_front__q_data_in[358]
  PIN g_front_1_u_front__q_data_in[359]
    DIRECTION INPUT ;
    USE SIGNAL ;
    PORT
      LAYER M5 ;
        RECT  138.06 0 138.084 0.192 ;
    END
  END g_front_1_u_front__q_data_in[359]
  PIN g_front_1_u_front__q_data_in[35]
    DIRECTION INPUT ;
    USE SIGNAL ;
    PORT
      LAYER M5 ;
        RECT  27.276 0 27.3 0.192 ;
    END
  END g_front_1_u_front__q_data_in[35]
  PIN g_front_1_u_front__q_data_in[360]
    DIRECTION INPUT ;
    USE SIGNAL ;
    PORT
      LAYER M5 ;
        RECT  138.444 0 138.468 0.192 ;
    END
  END g_front_1_u_front__q_data_in[360]
  PIN g_front_1_u_front__q_data_in[361]
    DIRECTION INPUT ;
    USE SIGNAL ;
    PORT
      LAYER M5 ;
        RECT  138.78 0 138.804 0.192 ;
    END
  END g_front_1_u_front__q_data_in[361]
  PIN g_front_1_u_front__q_data_in[362]
    DIRECTION INPUT ;
    USE SIGNAL ;
    PORT
      LAYER M5 ;
        RECT  139.116 0 139.14 0.192 ;
    END
  END g_front_1_u_front__q_data_in[362]
  PIN g_front_1_u_front__q_data_in[363]
    DIRECTION INPUT ;
    USE SIGNAL ;
    PORT
      LAYER M5 ;
        RECT  139.452 0 139.476 0.192 ;
    END
  END g_front_1_u_front__q_data_in[363]
  PIN g_front_1_u_front__q_data_in[364]
    DIRECTION INPUT ;
    USE SIGNAL ;
    PORT
      LAYER M5 ;
        RECT  139.788 0 139.812 0.192 ;
    END
  END g_front_1_u_front__q_data_in[364]
  PIN g_front_1_u_front__q_data_in[365]
    DIRECTION INPUT ;
    USE SIGNAL ;
    PORT
      LAYER M5 ;
        RECT  140.124 0 140.148 0.192 ;
    END
  END g_front_1_u_front__q_data_in[365]
  PIN g_front_1_u_front__q_data_in[366]
    DIRECTION INPUT ;
    USE SIGNAL ;
    PORT
      LAYER M5 ;
        RECT  140.46 0 140.484 0.192 ;
    END
  END g_front_1_u_front__q_data_in[366]
  PIN g_front_1_u_front__q_data_in[367]
    DIRECTION INPUT ;
    USE SIGNAL ;
    PORT
      LAYER M5 ;
        RECT  140.796 0 140.82 0.192 ;
    END
  END g_front_1_u_front__q_data_in[367]
  PIN g_front_1_u_front__q_data_in[368]
    DIRECTION INPUT ;
    USE SIGNAL ;
    PORT
      LAYER M5 ;
        RECT  141.18 0 141.204 0.192 ;
    END
  END g_front_1_u_front__q_data_in[368]
  PIN g_front_1_u_front__q_data_in[369]
    DIRECTION INPUT ;
    USE SIGNAL ;
    PORT
      LAYER M5 ;
        RECT  141.516 0 141.54 0.192 ;
    END
  END g_front_1_u_front__q_data_in[369]
  PIN g_front_1_u_front__q_data_in[36]
    DIRECTION INPUT ;
    USE SIGNAL ;
    PORT
      LAYER M5 ;
        RECT  27.612 0 27.636 0.192 ;
    END
  END g_front_1_u_front__q_data_in[36]
  PIN g_front_1_u_front__q_data_in[370]
    DIRECTION INPUT ;
    USE SIGNAL ;
    PORT
      LAYER M5 ;
        RECT  141.852 0 141.876 0.192 ;
    END
  END g_front_1_u_front__q_data_in[370]
  PIN g_front_1_u_front__q_data_in[371]
    DIRECTION INPUT ;
    USE SIGNAL ;
    PORT
      LAYER M5 ;
        RECT  142.188 0 142.212 0.192 ;
    END
  END g_front_1_u_front__q_data_in[371]
  PIN g_front_1_u_front__q_data_in[372]
    DIRECTION INPUT ;
    USE SIGNAL ;
    PORT
      LAYER M5 ;
        RECT  142.524 0 142.548 0.192 ;
    END
  END g_front_1_u_front__q_data_in[372]
  PIN g_front_1_u_front__q_data_in[373]
    DIRECTION INPUT ;
    USE SIGNAL ;
    PORT
      LAYER M5 ;
        RECT  142.86 0 142.884 0.192 ;
    END
  END g_front_1_u_front__q_data_in[373]
  PIN g_front_1_u_front__q_data_in[374]
    DIRECTION INPUT ;
    USE SIGNAL ;
    PORT
      LAYER M5 ;
        RECT  143.196 0 143.22 0.192 ;
    END
  END g_front_1_u_front__q_data_in[374]
  PIN g_front_1_u_front__q_data_in[375]
    DIRECTION INPUT ;
    USE SIGNAL ;
    PORT
      LAYER M5 ;
        RECT  143.532 0 143.556 0.192 ;
    END
  END g_front_1_u_front__q_data_in[375]
  PIN g_front_1_u_front__q_data_in[376]
    DIRECTION INPUT ;
    USE SIGNAL ;
    PORT
      LAYER M5 ;
        RECT  143.916 0 143.94 0.192 ;
    END
  END g_front_1_u_front__q_data_in[376]
  PIN g_front_1_u_front__q_data_in[377]
    DIRECTION INPUT ;
    USE SIGNAL ;
    PORT
      LAYER M5 ;
        RECT  144.252 0 144.276 0.192 ;
    END
  END g_front_1_u_front__q_data_in[377]
  PIN g_front_1_u_front__q_data_in[378]
    DIRECTION INPUT ;
    USE SIGNAL ;
    PORT
      LAYER M5 ;
        RECT  144.588 0 144.612 0.192 ;
    END
  END g_front_1_u_front__q_data_in[378]
  PIN g_front_1_u_front__q_data_in[379]
    DIRECTION INPUT ;
    USE SIGNAL ;
    PORT
      LAYER M5 ;
        RECT  144.924 0 144.948 0.192 ;
    END
  END g_front_1_u_front__q_data_in[379]
  PIN g_front_1_u_front__q_data_in[37]
    DIRECTION INPUT ;
    USE SIGNAL ;
    PORT
      LAYER M5 ;
        RECT  27.948 0 27.972 0.192 ;
    END
  END g_front_1_u_front__q_data_in[37]
  PIN g_front_1_u_front__q_data_in[380]
    DIRECTION INPUT ;
    USE SIGNAL ;
    PORT
      LAYER M5 ;
        RECT  145.26 0 145.284 0.192 ;
    END
  END g_front_1_u_front__q_data_in[380]
  PIN g_front_1_u_front__q_data_in[381]
    DIRECTION INPUT ;
    USE SIGNAL ;
    PORT
      LAYER M5 ;
        RECT  145.596 0 145.62 0.192 ;
    END
  END g_front_1_u_front__q_data_in[381]
  PIN g_front_1_u_front__q_data_in[382]
    DIRECTION INPUT ;
    USE SIGNAL ;
    PORT
      LAYER M5 ;
        RECT  145.932 0 145.956 0.192 ;
    END
  END g_front_1_u_front__q_data_in[382]
  PIN g_front_1_u_front__q_data_in[383]
    DIRECTION INPUT ;
    USE SIGNAL ;
    PORT
      LAYER M5 ;
        RECT  146.268 0 146.292 0.192 ;
    END
  END g_front_1_u_front__q_data_in[383]
  PIN g_front_1_u_front__q_data_in[384]
    DIRECTION INPUT ;
    USE SIGNAL ;
    PORT
      LAYER M5 ;
        RECT  146.652 0 146.676 0.192 ;
    END
  END g_front_1_u_front__q_data_in[384]
  PIN g_front_1_u_front__q_data_in[385]
    DIRECTION INPUT ;
    USE SIGNAL ;
    PORT
      LAYER M5 ;
        RECT  146.988 0 147.012 0.192 ;
    END
  END g_front_1_u_front__q_data_in[385]
  PIN g_front_1_u_front__q_data_in[386]
    DIRECTION INPUT ;
    USE SIGNAL ;
    PORT
      LAYER M5 ;
        RECT  147.324 0 147.348 0.192 ;
    END
  END g_front_1_u_front__q_data_in[386]
  PIN g_front_1_u_front__q_data_in[387]
    DIRECTION INPUT ;
    USE SIGNAL ;
    PORT
      LAYER M5 ;
        RECT  147.66 0 147.684 0.192 ;
    END
  END g_front_1_u_front__q_data_in[387]
  PIN g_front_1_u_front__q_data_in[388]
    DIRECTION INPUT ;
    USE SIGNAL ;
    PORT
      LAYER M5 ;
        RECT  147.996 0 148.02 0.192 ;
    END
  END g_front_1_u_front__q_data_in[388]
  PIN g_front_1_u_front__q_data_in[389]
    DIRECTION INPUT ;
    USE SIGNAL ;
    PORT
      LAYER M5 ;
        RECT  148.332 0 148.356 0.192 ;
    END
  END g_front_1_u_front__q_data_in[389]
  PIN g_front_1_u_front__q_data_in[38]
    DIRECTION INPUT ;
    USE SIGNAL ;
    PORT
      LAYER M5 ;
        RECT  28.332 0 28.356 0.192 ;
    END
  END g_front_1_u_front__q_data_in[38]
  PIN g_front_1_u_front__q_data_in[390]
    DIRECTION INPUT ;
    USE SIGNAL ;
    PORT
      LAYER M5 ;
        RECT  148.668 0 148.692 0.192 ;
    END
  END g_front_1_u_front__q_data_in[390]
  PIN g_front_1_u_front__q_data_in[391]
    DIRECTION INPUT ;
    USE SIGNAL ;
    PORT
      LAYER M5 ;
        RECT  149.004 0 149.028 0.192 ;
    END
  END g_front_1_u_front__q_data_in[391]
  PIN g_front_1_u_front__q_data_in[392]
    DIRECTION INPUT ;
    USE SIGNAL ;
    PORT
      LAYER M5 ;
        RECT  149.388 0 149.412 0.192 ;
    END
  END g_front_1_u_front__q_data_in[392]
  PIN g_front_1_u_front__q_data_in[393]
    DIRECTION INPUT ;
    USE SIGNAL ;
    PORT
      LAYER M5 ;
        RECT  149.724 0 149.748 0.192 ;
    END
  END g_front_1_u_front__q_data_in[393]
  PIN g_front_1_u_front__q_data_in[394]
    DIRECTION INPUT ;
    USE SIGNAL ;
    PORT
      LAYER M5 ;
        RECT  150.06 0 150.084 0.192 ;
    END
  END g_front_1_u_front__q_data_in[394]
  PIN g_front_1_u_front__q_data_in[395]
    DIRECTION INPUT ;
    USE SIGNAL ;
    PORT
      LAYER M5 ;
        RECT  150.396 0 150.42 0.192 ;
    END
  END g_front_1_u_front__q_data_in[395]
  PIN g_front_1_u_front__q_data_in[396]
    DIRECTION INPUT ;
    USE SIGNAL ;
    PORT
      LAYER M5 ;
        RECT  150.732 0 150.756 0.192 ;
    END
  END g_front_1_u_front__q_data_in[396]
  PIN g_front_1_u_front__q_data_in[397]
    DIRECTION INPUT ;
    USE SIGNAL ;
    PORT
      LAYER M5 ;
        RECT  151.068 0 151.092 0.192 ;
    END
  END g_front_1_u_front__q_data_in[397]
  PIN g_front_1_u_front__q_data_in[398]
    DIRECTION INPUT ;
    USE SIGNAL ;
    PORT
      LAYER M5 ;
        RECT  151.404 0 151.428 0.192 ;
    END
  END g_front_1_u_front__q_data_in[398]
  PIN g_front_1_u_front__q_data_in[399]
    DIRECTION INPUT ;
    USE SIGNAL ;
    PORT
      LAYER M5 ;
        RECT  151.74 0 151.764 0.192 ;
    END
  END g_front_1_u_front__q_data_in[399]
  PIN g_front_1_u_front__q_data_in[39]
    DIRECTION INPUT ;
    USE SIGNAL ;
    PORT
      LAYER M5 ;
        RECT  28.668 0 28.692 0.192 ;
    END
  END g_front_1_u_front__q_data_in[39]
  PIN g_front_1_u_front__q_data_in[3]
    DIRECTION INPUT ;
    USE SIGNAL ;
    PORT
      LAYER M5 ;
        RECT  16.332 0 16.356 0.192 ;
    END
  END g_front_1_u_front__q_data_in[3]
  PIN g_front_1_u_front__q_data_in[400]
    DIRECTION INPUT ;
    USE SIGNAL ;
    PORT
      LAYER M5 ;
        RECT  152.124 0 152.148 0.192 ;
    END
  END g_front_1_u_front__q_data_in[400]
  PIN g_front_1_u_front__q_data_in[401]
    DIRECTION INPUT ;
    USE SIGNAL ;
    PORT
      LAYER M5 ;
        RECT  152.46 0 152.484 0.192 ;
    END
  END g_front_1_u_front__q_data_in[401]
  PIN g_front_1_u_front__q_data_in[402]
    DIRECTION INPUT ;
    USE SIGNAL ;
    PORT
      LAYER M5 ;
        RECT  152.796 0 152.82 0.192 ;
    END
  END g_front_1_u_front__q_data_in[402]
  PIN g_front_1_u_front__q_data_in[403]
    DIRECTION INPUT ;
    USE SIGNAL ;
    PORT
      LAYER M5 ;
        RECT  153.132 0 153.156 0.192 ;
    END
  END g_front_1_u_front__q_data_in[403]
  PIN g_front_1_u_front__q_data_in[404]
    DIRECTION INPUT ;
    USE SIGNAL ;
    PORT
      LAYER M5 ;
        RECT  153.468 0 153.492 0.192 ;
    END
  END g_front_1_u_front__q_data_in[404]
  PIN g_front_1_u_front__q_data_in[405]
    DIRECTION INPUT ;
    USE SIGNAL ;
    PORT
      LAYER M5 ;
        RECT  153.804 0 153.828 0.192 ;
    END
  END g_front_1_u_front__q_data_in[405]
  PIN g_front_1_u_front__q_data_in[406]
    DIRECTION INPUT ;
    USE SIGNAL ;
    PORT
      LAYER M5 ;
        RECT  154.14 0 154.164 0.192 ;
    END
  END g_front_1_u_front__q_data_in[406]
  PIN g_front_1_u_front__q_data_in[407]
    DIRECTION INPUT ;
    USE SIGNAL ;
    PORT
      LAYER M5 ;
        RECT  154.476 0 154.5 0.192 ;
    END
  END g_front_1_u_front__q_data_in[407]
  PIN g_front_1_u_front__q_data_in[408]
    DIRECTION INPUT ;
    USE SIGNAL ;
    PORT
      LAYER M5 ;
        RECT  154.86 0 154.884 0.192 ;
    END
  END g_front_1_u_front__q_data_in[408]
  PIN g_front_1_u_front__q_data_in[409]
    DIRECTION INPUT ;
    USE SIGNAL ;
    PORT
      LAYER M5 ;
        RECT  155.196 0 155.22 0.192 ;
    END
  END g_front_1_u_front__q_data_in[409]
  PIN g_front_1_u_front__q_data_in[40]
    DIRECTION INPUT ;
    USE SIGNAL ;
    PORT
      LAYER M5 ;
        RECT  29.004 0 29.028 0.192 ;
    END
  END g_front_1_u_front__q_data_in[40]
  PIN g_front_1_u_front__q_data_in[410]
    DIRECTION INPUT ;
    USE SIGNAL ;
    PORT
      LAYER M5 ;
        RECT  155.532 0 155.556 0.192 ;
    END
  END g_front_1_u_front__q_data_in[410]
  PIN g_front_1_u_front__q_data_in[411]
    DIRECTION INPUT ;
    USE SIGNAL ;
    PORT
      LAYER M5 ;
        RECT  155.868 0 155.892 0.192 ;
    END
  END g_front_1_u_front__q_data_in[411]
  PIN g_front_1_u_front__q_data_in[412]
    DIRECTION INPUT ;
    USE SIGNAL ;
    PORT
      LAYER M5 ;
        RECT  156.204 0 156.228 0.192 ;
    END
  END g_front_1_u_front__q_data_in[412]
  PIN g_front_1_u_front__q_data_in[413]
    DIRECTION INPUT ;
    USE SIGNAL ;
    PORT
      LAYER M5 ;
        RECT  156.54 0 156.564 0.192 ;
    END
  END g_front_1_u_front__q_data_in[413]
  PIN g_front_1_u_front__q_data_in[414]
    DIRECTION INPUT ;
    USE SIGNAL ;
    PORT
      LAYER M5 ;
        RECT  156.876 0 156.9 0.192 ;
    END
  END g_front_1_u_front__q_data_in[414]
  PIN g_front_1_u_front__q_data_in[415]
    DIRECTION INPUT ;
    USE SIGNAL ;
    PORT
      LAYER M5 ;
        RECT  157.212 0 157.236 0.192 ;
    END
  END g_front_1_u_front__q_data_in[415]
  PIN g_front_1_u_front__q_data_in[416]
    DIRECTION INPUT ;
    USE SIGNAL ;
    PORT
      LAYER M5 ;
        RECT  157.596 0 157.62 0.192 ;
    END
  END g_front_1_u_front__q_data_in[416]
  PIN g_front_1_u_front__q_data_in[417]
    DIRECTION INPUT ;
    USE SIGNAL ;
    PORT
      LAYER M5 ;
        RECT  157.932 0 157.956 0.192 ;
    END
  END g_front_1_u_front__q_data_in[417]
  PIN g_front_1_u_front__q_data_in[418]
    DIRECTION INPUT ;
    USE SIGNAL ;
    PORT
      LAYER M5 ;
        RECT  158.268 0 158.292 0.192 ;
    END
  END g_front_1_u_front__q_data_in[418]
  PIN g_front_1_u_front__q_data_in[419]
    DIRECTION INPUT ;
    USE SIGNAL ;
    PORT
      LAYER M5 ;
        RECT  158.604 0 158.628 0.192 ;
    END
  END g_front_1_u_front__q_data_in[419]
  PIN g_front_1_u_front__q_data_in[41]
    DIRECTION INPUT ;
    USE SIGNAL ;
    PORT
      LAYER M5 ;
        RECT  29.34 0 29.364 0.192 ;
    END
  END g_front_1_u_front__q_data_in[41]
  PIN g_front_1_u_front__q_data_in[420]
    DIRECTION INPUT ;
    USE SIGNAL ;
    PORT
      LAYER M5 ;
        RECT  158.94 0 158.964 0.192 ;
    END
  END g_front_1_u_front__q_data_in[420]
  PIN g_front_1_u_front__q_data_in[421]
    DIRECTION INPUT ;
    USE SIGNAL ;
    PORT
      LAYER M5 ;
        RECT  159.276 0 159.3 0.192 ;
    END
  END g_front_1_u_front__q_data_in[421]
  PIN g_front_1_u_front__q_data_in[422]
    DIRECTION INPUT ;
    USE SIGNAL ;
    PORT
      LAYER M5 ;
        RECT  159.612 0 159.636 0.192 ;
    END
  END g_front_1_u_front__q_data_in[422]
  PIN g_front_1_u_front__q_data_in[423]
    DIRECTION INPUT ;
    USE SIGNAL ;
    PORT
      LAYER M5 ;
        RECT  159.948 0 159.972 0.192 ;
    END
  END g_front_1_u_front__q_data_in[423]
  PIN g_front_1_u_front__q_data_in[424]
    DIRECTION INPUT ;
    USE SIGNAL ;
    PORT
      LAYER M5 ;
        RECT  160.332 0 160.356 0.192 ;
    END
  END g_front_1_u_front__q_data_in[424]
  PIN g_front_1_u_front__q_data_in[425]
    DIRECTION INPUT ;
    USE SIGNAL ;
    PORT
      LAYER M5 ;
        RECT  160.668 0 160.692 0.192 ;
    END
  END g_front_1_u_front__q_data_in[425]
  PIN g_front_1_u_front__q_data_in[426]
    DIRECTION INPUT ;
    USE SIGNAL ;
    PORT
      LAYER M5 ;
        RECT  161.004 0 161.028 0.192 ;
    END
  END g_front_1_u_front__q_data_in[426]
  PIN g_front_1_u_front__q_data_in[427]
    DIRECTION INPUT ;
    USE SIGNAL ;
    PORT
      LAYER M5 ;
        RECT  161.34 0 161.364 0.192 ;
    END
  END g_front_1_u_front__q_data_in[427]
  PIN g_front_1_u_front__q_data_in[428]
    DIRECTION INPUT ;
    USE SIGNAL ;
    PORT
      LAYER M5 ;
        RECT  161.676 0 161.7 0.192 ;
    END
  END g_front_1_u_front__q_data_in[428]
  PIN g_front_1_u_front__q_data_in[429]
    DIRECTION INPUT ;
    USE SIGNAL ;
    PORT
      LAYER M5 ;
        RECT  162.012 0 162.036 0.192 ;
    END
  END g_front_1_u_front__q_data_in[429]
  PIN g_front_1_u_front__q_data_in[42]
    DIRECTION INPUT ;
    USE SIGNAL ;
    PORT
      LAYER M5 ;
        RECT  29.676 0 29.7 0.192 ;
    END
  END g_front_1_u_front__q_data_in[42]
  PIN g_front_1_u_front__q_data_in[430]
    DIRECTION INPUT ;
    USE SIGNAL ;
    PORT
      LAYER M5 ;
        RECT  162.348 0 162.372 0.192 ;
    END
  END g_front_1_u_front__q_data_in[430]
  PIN g_front_1_u_front__q_data_in[431]
    DIRECTION INPUT ;
    USE SIGNAL ;
    PORT
      LAYER M5 ;
        RECT  162.684 0 162.708 0.192 ;
    END
  END g_front_1_u_front__q_data_in[431]
  PIN g_front_1_u_front__q_data_in[432]
    DIRECTION INPUT ;
    USE SIGNAL ;
    PORT
      LAYER M5 ;
        RECT  163.068 0 163.092 0.192 ;
    END
  END g_front_1_u_front__q_data_in[432]
  PIN g_front_1_u_front__q_data_in[433]
    DIRECTION INPUT ;
    USE SIGNAL ;
    PORT
      LAYER M5 ;
        RECT  163.404 0 163.428 0.192 ;
    END
  END g_front_1_u_front__q_data_in[433]
  PIN g_front_1_u_front__q_data_in[434]
    DIRECTION INPUT ;
    USE SIGNAL ;
    PORT
      LAYER M5 ;
        RECT  163.74 0 163.764 0.192 ;
    END
  END g_front_1_u_front__q_data_in[434]
  PIN g_front_1_u_front__q_data_in[435]
    DIRECTION INPUT ;
    USE SIGNAL ;
    PORT
      LAYER M5 ;
        RECT  164.076 0 164.1 0.192 ;
    END
  END g_front_1_u_front__q_data_in[435]
  PIN g_front_1_u_front__q_data_in[436]
    DIRECTION INPUT ;
    USE SIGNAL ;
    PORT
      LAYER M5 ;
        RECT  164.412 0 164.436 0.192 ;
    END
  END g_front_1_u_front__q_data_in[436]
  PIN g_front_1_u_front__q_data_in[437]
    DIRECTION INPUT ;
    USE SIGNAL ;
    PORT
      LAYER M5 ;
        RECT  164.748 0 164.772 0.192 ;
    END
  END g_front_1_u_front__q_data_in[437]
  PIN g_front_1_u_front__q_data_in[438]
    DIRECTION INPUT ;
    USE SIGNAL ;
    PORT
      LAYER M5 ;
        RECT  165.084 0 165.108 0.192 ;
    END
  END g_front_1_u_front__q_data_in[438]
  PIN g_front_1_u_front__q_data_in[439]
    DIRECTION INPUT ;
    USE SIGNAL ;
    PORT
      LAYER M5 ;
        RECT  165.42 0 165.444 0.192 ;
    END
  END g_front_1_u_front__q_data_in[439]
  PIN g_front_1_u_front__q_data_in[43]
    DIRECTION INPUT ;
    USE SIGNAL ;
    PORT
      LAYER M5 ;
        RECT  30.012 0 30.036 0.192 ;
    END
  END g_front_1_u_front__q_data_in[43]
  PIN g_front_1_u_front__q_data_in[440]
    DIRECTION INPUT ;
    USE SIGNAL ;
    PORT
      LAYER M5 ;
        RECT  165.804 0 165.828 0.192 ;
    END
  END g_front_1_u_front__q_data_in[440]
  PIN g_front_1_u_front__q_data_in[441]
    DIRECTION INPUT ;
    USE SIGNAL ;
    PORT
      LAYER M5 ;
        RECT  166.14 0 166.164 0.192 ;
    END
  END g_front_1_u_front__q_data_in[441]
  PIN g_front_1_u_front__q_data_in[442]
    DIRECTION INPUT ;
    USE SIGNAL ;
    PORT
      LAYER M5 ;
        RECT  166.476 0 166.5 0.192 ;
    END
  END g_front_1_u_front__q_data_in[442]
  PIN g_front_1_u_front__q_data_in[443]
    DIRECTION INPUT ;
    USE SIGNAL ;
    PORT
      LAYER M5 ;
        RECT  166.812 0 166.836 0.192 ;
    END
  END g_front_1_u_front__q_data_in[443]
  PIN g_front_1_u_front__q_data_in[444]
    DIRECTION INPUT ;
    USE SIGNAL ;
    PORT
      LAYER M5 ;
        RECT  167.148 0 167.172 0.192 ;
    END
  END g_front_1_u_front__q_data_in[444]
  PIN g_front_1_u_front__q_data_in[445]
    DIRECTION INPUT ;
    USE SIGNAL ;
    PORT
      LAYER M5 ;
        RECT  167.484 0 167.508 0.192 ;
    END
  END g_front_1_u_front__q_data_in[445]
  PIN g_front_1_u_front__q_data_in[446]
    DIRECTION INPUT ;
    USE SIGNAL ;
    PORT
      LAYER M5 ;
        RECT  167.82 0 167.844 0.192 ;
    END
  END g_front_1_u_front__q_data_in[446]
  PIN g_front_1_u_front__q_data_in[447]
    DIRECTION INPUT ;
    USE SIGNAL ;
    PORT
      LAYER M5 ;
        RECT  168.156 0 168.18 0.192 ;
    END
  END g_front_1_u_front__q_data_in[447]
  PIN g_front_1_u_front__q_data_in[448]
    DIRECTION INPUT ;
    USE SIGNAL ;
    PORT
      LAYER M5 ;
        RECT  168.54 0 168.564 0.192 ;
    END
  END g_front_1_u_front__q_data_in[448]
  PIN g_front_1_u_front__q_data_in[449]
    DIRECTION INPUT ;
    USE SIGNAL ;
    PORT
      LAYER M5 ;
        RECT  168.876 0 168.9 0.192 ;
    END
  END g_front_1_u_front__q_data_in[449]
  PIN g_front_1_u_front__q_data_in[44]
    DIRECTION INPUT ;
    USE SIGNAL ;
    PORT
      LAYER M5 ;
        RECT  30.348 0 30.372 0.192 ;
    END
  END g_front_1_u_front__q_data_in[44]
  PIN g_front_1_u_front__q_data_in[450]
    DIRECTION INPUT ;
    USE SIGNAL ;
    PORT
      LAYER M5 ;
        RECT  169.212 0 169.236 0.192 ;
    END
  END g_front_1_u_front__q_data_in[450]
  PIN g_front_1_u_front__q_data_in[451]
    DIRECTION INPUT ;
    USE SIGNAL ;
    PORT
      LAYER M5 ;
        RECT  169.548 0 169.572 0.192 ;
    END
  END g_front_1_u_front__q_data_in[451]
  PIN g_front_1_u_front__q_data_in[452]
    DIRECTION INPUT ;
    USE SIGNAL ;
    PORT
      LAYER M5 ;
        RECT  169.884 0 169.908 0.192 ;
    END
  END g_front_1_u_front__q_data_in[452]
  PIN g_front_1_u_front__q_data_in[453]
    DIRECTION INPUT ;
    USE SIGNAL ;
    PORT
      LAYER M5 ;
        RECT  170.22 0 170.244 0.192 ;
    END
  END g_front_1_u_front__q_data_in[453]
  PIN g_front_1_u_front__q_data_in[454]
    DIRECTION INPUT ;
    USE SIGNAL ;
    PORT
      LAYER M5 ;
        RECT  170.556 0 170.58 0.192 ;
    END
  END g_front_1_u_front__q_data_in[454]
  PIN g_front_1_u_front__q_data_in[455]
    DIRECTION INPUT ;
    USE SIGNAL ;
    PORT
      LAYER M5 ;
        RECT  170.892 0 170.916 0.192 ;
    END
  END g_front_1_u_front__q_data_in[455]
  PIN g_front_1_u_front__q_data_in[456]
    DIRECTION INPUT ;
    USE SIGNAL ;
    PORT
      LAYER M5 ;
        RECT  171.276 0 171.3 0.192 ;
    END
  END g_front_1_u_front__q_data_in[456]
  PIN g_front_1_u_front__q_data_in[457]
    DIRECTION INPUT ;
    USE SIGNAL ;
    PORT
      LAYER M5 ;
        RECT  171.612 0 171.636 0.192 ;
    END
  END g_front_1_u_front__q_data_in[457]
  PIN g_front_1_u_front__q_data_in[458]
    DIRECTION INPUT ;
    USE SIGNAL ;
    PORT
      LAYER M5 ;
        RECT  171.948 0 171.972 0.192 ;
    END
  END g_front_1_u_front__q_data_in[458]
  PIN g_front_1_u_front__q_data_in[459]
    DIRECTION INPUT ;
    USE SIGNAL ;
    PORT
      LAYER M5 ;
        RECT  172.284 0 172.308 0.192 ;
    END
  END g_front_1_u_front__q_data_in[459]
  PIN g_front_1_u_front__q_data_in[45]
    DIRECTION INPUT ;
    USE SIGNAL ;
    PORT
      LAYER M5 ;
        RECT  30.684 0 30.708 0.192 ;
    END
  END g_front_1_u_front__q_data_in[45]
  PIN g_front_1_u_front__q_data_in[460]
    DIRECTION INPUT ;
    USE SIGNAL ;
    PORT
      LAYER M5 ;
        RECT  172.62 0 172.644 0.192 ;
    END
  END g_front_1_u_front__q_data_in[460]
  PIN g_front_1_u_front__q_data_in[461]
    DIRECTION INPUT ;
    USE SIGNAL ;
    PORT
      LAYER M5 ;
        RECT  172.956 0 172.98 0.192 ;
    END
  END g_front_1_u_front__q_data_in[461]
  PIN g_front_1_u_front__q_data_in[462]
    DIRECTION INPUT ;
    USE SIGNAL ;
    PORT
      LAYER M5 ;
        RECT  173.292 0 173.316 0.192 ;
    END
  END g_front_1_u_front__q_data_in[462]
  PIN g_front_1_u_front__q_data_in[463]
    DIRECTION INPUT ;
    USE SIGNAL ;
    PORT
      LAYER M5 ;
        RECT  173.628 0 173.652 0.192 ;
    END
  END g_front_1_u_front__q_data_in[463]
  PIN g_front_1_u_front__q_data_in[464]
    DIRECTION INPUT ;
    USE SIGNAL ;
    PORT
      LAYER M5 ;
        RECT  174.012 0 174.036 0.192 ;
    END
  END g_front_1_u_front__q_data_in[464]
  PIN g_front_1_u_front__q_data_in[465]
    DIRECTION INPUT ;
    USE SIGNAL ;
    PORT
      LAYER M5 ;
        RECT  174.348 0 174.372 0.192 ;
    END
  END g_front_1_u_front__q_data_in[465]
  PIN g_front_1_u_front__q_data_in[466]
    DIRECTION INPUT ;
    USE SIGNAL ;
    PORT
      LAYER M5 ;
        RECT  174.684 0 174.708 0.192 ;
    END
  END g_front_1_u_front__q_data_in[466]
  PIN g_front_1_u_front__q_data_in[467]
    DIRECTION INPUT ;
    USE SIGNAL ;
    PORT
      LAYER M5 ;
        RECT  175.02 0 175.044 0.192 ;
    END
  END g_front_1_u_front__q_data_in[467]
  PIN g_front_1_u_front__q_data_in[468]
    DIRECTION INPUT ;
    USE SIGNAL ;
    PORT
      LAYER M5 ;
        RECT  175.356 0 175.38 0.192 ;
    END
  END g_front_1_u_front__q_data_in[468]
  PIN g_front_1_u_front__q_data_in[469]
    DIRECTION INPUT ;
    USE SIGNAL ;
    PORT
      LAYER M5 ;
        RECT  175.692 0 175.716 0.192 ;
    END
  END g_front_1_u_front__q_data_in[469]
  PIN g_front_1_u_front__q_data_in[46]
    DIRECTION INPUT ;
    USE SIGNAL ;
    PORT
      LAYER M5 ;
        RECT  31.068 0 31.092 0.192 ;
    END
  END g_front_1_u_front__q_data_in[46]
  PIN g_front_1_u_front__q_data_in[470]
    DIRECTION INPUT ;
    USE SIGNAL ;
    PORT
      LAYER M5 ;
        RECT  176.028 0 176.052 0.192 ;
    END
  END g_front_1_u_front__q_data_in[470]
  PIN g_front_1_u_front__q_data_in[471]
    DIRECTION INPUT ;
    USE SIGNAL ;
    PORT
      LAYER M5 ;
        RECT  176.364 0 176.388 0.192 ;
    END
  END g_front_1_u_front__q_data_in[471]
  PIN g_front_1_u_front__q_data_in[472]
    DIRECTION INPUT ;
    USE SIGNAL ;
    PORT
      LAYER M5 ;
        RECT  176.748 0 176.772 0.192 ;
    END
  END g_front_1_u_front__q_data_in[472]
  PIN g_front_1_u_front__q_data_in[473]
    DIRECTION INPUT ;
    USE SIGNAL ;
    PORT
      LAYER M5 ;
        RECT  177.084 0 177.108 0.192 ;
    END
  END g_front_1_u_front__q_data_in[473]
  PIN g_front_1_u_front__q_data_in[474]
    DIRECTION INPUT ;
    USE SIGNAL ;
    PORT
      LAYER M5 ;
        RECT  177.42 0 177.444 0.192 ;
    END
  END g_front_1_u_front__q_data_in[474]
  PIN g_front_1_u_front__q_data_in[475]
    DIRECTION INPUT ;
    USE SIGNAL ;
    PORT
      LAYER M5 ;
        RECT  177.756 0 177.78 0.192 ;
    END
  END g_front_1_u_front__q_data_in[475]
  PIN g_front_1_u_front__q_data_in[476]
    DIRECTION INPUT ;
    USE SIGNAL ;
    PORT
      LAYER M5 ;
        RECT  178.092 0 178.116 0.192 ;
    END
  END g_front_1_u_front__q_data_in[476]
  PIN g_front_1_u_front__q_data_in[477]
    DIRECTION INPUT ;
    USE SIGNAL ;
    PORT
      LAYER M5 ;
        RECT  178.428 0 178.452 0.192 ;
    END
  END g_front_1_u_front__q_data_in[477]
  PIN g_front_1_u_front__q_data_in[478]
    DIRECTION INPUT ;
    USE SIGNAL ;
    PORT
      LAYER M5 ;
        RECT  178.764 0 178.788 0.192 ;
    END
  END g_front_1_u_front__q_data_in[478]
  PIN g_front_1_u_front__q_data_in[479]
    DIRECTION INPUT ;
    USE SIGNAL ;
    PORT
      LAYER M5 ;
        RECT  179.1 0 179.124 0.192 ;
    END
  END g_front_1_u_front__q_data_in[479]
  PIN g_front_1_u_front__q_data_in[47]
    DIRECTION INPUT ;
    USE SIGNAL ;
    PORT
      LAYER M5 ;
        RECT  31.404 0 31.428 0.192 ;
    END
  END g_front_1_u_front__q_data_in[47]
  PIN g_front_1_u_front__q_data_in[480]
    DIRECTION INPUT ;
    USE SIGNAL ;
    PORT
      LAYER M5 ;
        RECT  179.436 0 179.46 0.192 ;
    END
  END g_front_1_u_front__q_data_in[480]
  PIN g_front_1_u_front__q_data_in[481]
    DIRECTION INPUT ;
    USE SIGNAL ;
    PORT
      LAYER M5 ;
        RECT  179.82 0 179.844 0.192 ;
    END
  END g_front_1_u_front__q_data_in[481]
  PIN g_front_1_u_front__q_data_in[482]
    DIRECTION INPUT ;
    USE SIGNAL ;
    PORT
      LAYER M5 ;
        RECT  180.156 0 180.18 0.192 ;
    END
  END g_front_1_u_front__q_data_in[482]
  PIN g_front_1_u_front__q_data_in[483]
    DIRECTION INPUT ;
    USE SIGNAL ;
    PORT
      LAYER M5 ;
        RECT  180.492 0 180.516 0.192 ;
    END
  END g_front_1_u_front__q_data_in[483]
  PIN g_front_1_u_front__q_data_in[484]
    DIRECTION INPUT ;
    USE SIGNAL ;
    PORT
      LAYER M5 ;
        RECT  180.828 0 180.852 0.192 ;
    END
  END g_front_1_u_front__q_data_in[484]
  PIN g_front_1_u_front__q_data_in[485]
    DIRECTION INPUT ;
    USE SIGNAL ;
    PORT
      LAYER M5 ;
        RECT  181.164 0 181.188 0.192 ;
    END
  END g_front_1_u_front__q_data_in[485]
  PIN g_front_1_u_front__q_data_in[486]
    DIRECTION INPUT ;
    USE SIGNAL ;
    PORT
      LAYER M5 ;
        RECT  181.5 0 181.524 0.192 ;
    END
  END g_front_1_u_front__q_data_in[486]
  PIN g_front_1_u_front__q_data_in[487]
    DIRECTION INPUT ;
    USE SIGNAL ;
    PORT
      LAYER M5 ;
        RECT  181.836 0 181.86 0.192 ;
    END
  END g_front_1_u_front__q_data_in[487]
  PIN g_front_1_u_front__q_data_in[488]
    DIRECTION INPUT ;
    USE SIGNAL ;
    PORT
      LAYER M5 ;
        RECT  182.172 0 182.196 0.192 ;
    END
  END g_front_1_u_front__q_data_in[488]
  PIN g_front_1_u_front__q_data_in[489]
    DIRECTION INPUT ;
    USE SIGNAL ;
    PORT
      LAYER M5 ;
        RECT  182.556 0 182.58 0.192 ;
    END
  END g_front_1_u_front__q_data_in[489]
  PIN g_front_1_u_front__q_data_in[48]
    DIRECTION INPUT ;
    USE SIGNAL ;
    PORT
      LAYER M5 ;
        RECT  31.74 0 31.764 0.192 ;
    END
  END g_front_1_u_front__q_data_in[48]
  PIN g_front_1_u_front__q_data_in[490]
    DIRECTION INPUT ;
    USE SIGNAL ;
    PORT
      LAYER M5 ;
        RECT  182.892 0 182.916 0.192 ;
    END
  END g_front_1_u_front__q_data_in[490]
  PIN g_front_1_u_front__q_data_in[491]
    DIRECTION INPUT ;
    USE SIGNAL ;
    PORT
      LAYER M5 ;
        RECT  183.228 0 183.252 0.192 ;
    END
  END g_front_1_u_front__q_data_in[491]
  PIN g_front_1_u_front__q_data_in[492]
    DIRECTION INPUT ;
    USE SIGNAL ;
    PORT
      LAYER M5 ;
        RECT  183.564 0 183.588 0.192 ;
    END
  END g_front_1_u_front__q_data_in[492]
  PIN g_front_1_u_front__q_data_in[493]
    DIRECTION INPUT ;
    USE SIGNAL ;
    PORT
      LAYER M5 ;
        RECT  183.9 0 183.924 0.192 ;
    END
  END g_front_1_u_front__q_data_in[493]
  PIN g_front_1_u_front__q_data_in[494]
    DIRECTION INPUT ;
    USE SIGNAL ;
    PORT
      LAYER M5 ;
        RECT  184.236 0 184.26 0.192 ;
    END
  END g_front_1_u_front__q_data_in[494]
  PIN g_front_1_u_front__q_data_in[495]
    DIRECTION INPUT ;
    USE SIGNAL ;
    PORT
      LAYER M5 ;
        RECT  184.572 0 184.596 0.192 ;
    END
  END g_front_1_u_front__q_data_in[495]
  PIN g_front_1_u_front__q_data_in[496]
    DIRECTION INPUT ;
    USE SIGNAL ;
    PORT
      LAYER M5 ;
        RECT  184.908 0 184.932 0.192 ;
    END
  END g_front_1_u_front__q_data_in[496]
  PIN g_front_1_u_front__q_data_in[497]
    DIRECTION INPUT ;
    USE SIGNAL ;
    PORT
      LAYER M5 ;
        RECT  185.292 0 185.316 0.192 ;
    END
  END g_front_1_u_front__q_data_in[497]
  PIN g_front_1_u_front__q_data_in[498]
    DIRECTION INPUT ;
    USE SIGNAL ;
    PORT
      LAYER M5 ;
        RECT  185.628 0 185.652 0.192 ;
    END
  END g_front_1_u_front__q_data_in[498]
  PIN g_front_1_u_front__q_data_in[499]
    DIRECTION INPUT ;
    USE SIGNAL ;
    PORT
      LAYER M5 ;
        RECT  185.964 0 185.988 0.192 ;
    END
  END g_front_1_u_front__q_data_in[499]
  PIN g_front_1_u_front__q_data_in[49]
    DIRECTION INPUT ;
    USE SIGNAL ;
    PORT
      LAYER M5 ;
        RECT  32.076 0 32.1 0.192 ;
    END
  END g_front_1_u_front__q_data_in[49]
  PIN g_front_1_u_front__q_data_in[4]
    DIRECTION INPUT ;
    USE SIGNAL ;
    PORT
      LAYER M5 ;
        RECT  16.668 0 16.692 0.192 ;
    END
  END g_front_1_u_front__q_data_in[4]
  PIN g_front_1_u_front__q_data_in[500]
    DIRECTION INPUT ;
    USE SIGNAL ;
    PORT
      LAYER M5 ;
        RECT  186.3 0 186.324 0.192 ;
    END
  END g_front_1_u_front__q_data_in[500]
  PIN g_front_1_u_front__q_data_in[501]
    DIRECTION INPUT ;
    USE SIGNAL ;
    PORT
      LAYER M5 ;
        RECT  186.636 0 186.66 0.192 ;
    END
  END g_front_1_u_front__q_data_in[501]
  PIN g_front_1_u_front__q_data_in[502]
    DIRECTION INPUT ;
    USE SIGNAL ;
    PORT
      LAYER M5 ;
        RECT  186.972 0 186.996 0.192 ;
    END
  END g_front_1_u_front__q_data_in[502]
  PIN g_front_1_u_front__q_data_in[503]
    DIRECTION INPUT ;
    USE SIGNAL ;
    PORT
      LAYER M5 ;
        RECT  187.308 0 187.332 0.192 ;
    END
  END g_front_1_u_front__q_data_in[503]
  PIN g_front_1_u_front__q_data_in[504]
    DIRECTION INPUT ;
    USE SIGNAL ;
    PORT
      LAYER M5 ;
        RECT  187.644 0 187.668 0.192 ;
    END
  END g_front_1_u_front__q_data_in[504]
  PIN g_front_1_u_front__q_data_in[505]
    DIRECTION INPUT ;
    USE SIGNAL ;
    PORT
      LAYER M5 ;
        RECT  188.028 0 188.052 0.192 ;
    END
  END g_front_1_u_front__q_data_in[505]
  PIN g_front_1_u_front__q_data_in[506]
    DIRECTION INPUT ;
    USE SIGNAL ;
    PORT
      LAYER M5 ;
        RECT  188.364 0 188.388 0.192 ;
    END
  END g_front_1_u_front__q_data_in[506]
  PIN g_front_1_u_front__q_data_in[507]
    DIRECTION INPUT ;
    USE SIGNAL ;
    PORT
      LAYER M5 ;
        RECT  188.7 0 188.724 0.192 ;
    END
  END g_front_1_u_front__q_data_in[507]
  PIN g_front_1_u_front__q_data_in[508]
    DIRECTION INPUT ;
    USE SIGNAL ;
    PORT
      LAYER M5 ;
        RECT  189.036 0 189.06 0.192 ;
    END
  END g_front_1_u_front__q_data_in[508]
  PIN g_front_1_u_front__q_data_in[509]
    DIRECTION INPUT ;
    USE SIGNAL ;
    PORT
      LAYER M5 ;
        RECT  189.372 0 189.396 0.192 ;
    END
  END g_front_1_u_front__q_data_in[509]
  PIN g_front_1_u_front__q_data_in[50]
    DIRECTION INPUT ;
    USE SIGNAL ;
    PORT
      LAYER M5 ;
        RECT  32.412 0 32.436 0.192 ;
    END
  END g_front_1_u_front__q_data_in[50]
  PIN g_front_1_u_front__q_data_in[510]
    DIRECTION INPUT ;
    USE SIGNAL ;
    PORT
      LAYER M5 ;
        RECT  189.708 0 189.732 0.192 ;
    END
  END g_front_1_u_front__q_data_in[510]
  PIN g_front_1_u_front__q_data_in[511]
    DIRECTION INPUT ;
    USE SIGNAL ;
    PORT
      LAYER M5 ;
        RECT  190.044 0 190.068 0.192 ;
    END
  END g_front_1_u_front__q_data_in[511]
  PIN g_front_1_u_front__q_data_in[51]
    DIRECTION INPUT ;
    USE SIGNAL ;
    PORT
      LAYER M5 ;
        RECT  32.748 0 32.772 0.192 ;
    END
  END g_front_1_u_front__q_data_in[51]
  PIN g_front_1_u_front__q_data_in[52]
    DIRECTION INPUT ;
    USE SIGNAL ;
    PORT
      LAYER M5 ;
        RECT  33.084 0 33.108 0.192 ;
    END
  END g_front_1_u_front__q_data_in[52]
  PIN g_front_1_u_front__q_data_in[53]
    DIRECTION INPUT ;
    USE SIGNAL ;
    PORT
      LAYER M5 ;
        RECT  33.42 0 33.444 0.192 ;
    END
  END g_front_1_u_front__q_data_in[53]
  PIN g_front_1_u_front__q_data_in[54]
    DIRECTION INPUT ;
    USE SIGNAL ;
    PORT
      LAYER M5 ;
        RECT  33.804 0 33.828 0.192 ;
    END
  END g_front_1_u_front__q_data_in[54]
  PIN g_front_1_u_front__q_data_in[55]
    DIRECTION INPUT ;
    USE SIGNAL ;
    PORT
      LAYER M5 ;
        RECT  34.14 0 34.164 0.192 ;
    END
  END g_front_1_u_front__q_data_in[55]
  PIN g_front_1_u_front__q_data_in[56]
    DIRECTION INPUT ;
    USE SIGNAL ;
    PORT
      LAYER M5 ;
        RECT  34.476 0 34.5 0.192 ;
    END
  END g_front_1_u_front__q_data_in[56]
  PIN g_front_1_u_front__q_data_in[57]
    DIRECTION INPUT ;
    USE SIGNAL ;
    PORT
      LAYER M5 ;
        RECT  34.812 0 34.836 0.192 ;
    END
  END g_front_1_u_front__q_data_in[57]
  PIN g_front_1_u_front__q_data_in[58]
    DIRECTION INPUT ;
    USE SIGNAL ;
    PORT
      LAYER M5 ;
        RECT  35.148 0 35.172 0.192 ;
    END
  END g_front_1_u_front__q_data_in[58]
  PIN g_front_1_u_front__q_data_in[59]
    DIRECTION INPUT ;
    USE SIGNAL ;
    PORT
      LAYER M5 ;
        RECT  35.484 0 35.508 0.192 ;
    END
  END g_front_1_u_front__q_data_in[59]
  PIN g_front_1_u_front__q_data_in[5]
    DIRECTION INPUT ;
    USE SIGNAL ;
    PORT
      LAYER M5 ;
        RECT  17.004 0 17.028 0.192 ;
    END
  END g_front_1_u_front__q_data_in[5]
  PIN g_front_1_u_front__q_data_in[60]
    DIRECTION INPUT ;
    USE SIGNAL ;
    PORT
      LAYER M5 ;
        RECT  35.82 0 35.844 0.192 ;
    END
  END g_front_1_u_front__q_data_in[60]
  PIN g_front_1_u_front__q_data_in[61]
    DIRECTION INPUT ;
    USE SIGNAL ;
    PORT
      LAYER M5 ;
        RECT  36.156 0 36.18 0.192 ;
    END
  END g_front_1_u_front__q_data_in[61]
  PIN g_front_1_u_front__q_data_in[62]
    DIRECTION INPUT ;
    USE SIGNAL ;
    PORT
      LAYER M5 ;
        RECT  36.54 0 36.564 0.192 ;
    END
  END g_front_1_u_front__q_data_in[62]
  PIN g_front_1_u_front__q_data_in[63]
    DIRECTION INPUT ;
    USE SIGNAL ;
    PORT
      LAYER M5 ;
        RECT  36.876 0 36.9 0.192 ;
    END
  END g_front_1_u_front__q_data_in[63]
  PIN g_front_1_u_front__q_data_in[64]
    DIRECTION INPUT ;
    USE SIGNAL ;
    PORT
      LAYER M5 ;
        RECT  37.212 0 37.236 0.192 ;
    END
  END g_front_1_u_front__q_data_in[64]
  PIN g_front_1_u_front__q_data_in[65]
    DIRECTION INPUT ;
    USE SIGNAL ;
    PORT
      LAYER M5 ;
        RECT  37.548 0 37.572 0.192 ;
    END
  END g_front_1_u_front__q_data_in[65]
  PIN g_front_1_u_front__q_data_in[66]
    DIRECTION INPUT ;
    USE SIGNAL ;
    PORT
      LAYER M5 ;
        RECT  37.884 0 37.908 0.192 ;
    END
  END g_front_1_u_front__q_data_in[66]
  PIN g_front_1_u_front__q_data_in[67]
    DIRECTION INPUT ;
    USE SIGNAL ;
    PORT
      LAYER M5 ;
        RECT  38.22 0 38.244 0.192 ;
    END
  END g_front_1_u_front__q_data_in[67]
  PIN g_front_1_u_front__q_data_in[68]
    DIRECTION INPUT ;
    USE SIGNAL ;
    PORT
      LAYER M5 ;
        RECT  38.556 0 38.58 0.192 ;
    END
  END g_front_1_u_front__q_data_in[68]
  PIN g_front_1_u_front__q_data_in[69]
    DIRECTION INPUT ;
    USE SIGNAL ;
    PORT
      LAYER M5 ;
        RECT  38.892 0 38.916 0.192 ;
    END
  END g_front_1_u_front__q_data_in[69]
  PIN g_front_1_u_front__q_data_in[6]
    DIRECTION INPUT ;
    USE SIGNAL ;
    PORT
      LAYER M5 ;
        RECT  17.388 0 17.412 0.192 ;
    END
  END g_front_1_u_front__q_data_in[6]
  PIN g_front_1_u_front__q_data_in[70]
    DIRECTION INPUT ;
    USE SIGNAL ;
    PORT
      LAYER M5 ;
        RECT  39.228 0 39.252 0.192 ;
    END
  END g_front_1_u_front__q_data_in[70]
  PIN g_front_1_u_front__q_data_in[71]
    DIRECTION INPUT ;
    USE SIGNAL ;
    PORT
      LAYER M5 ;
        RECT  39.612 0 39.636 0.192 ;
    END
  END g_front_1_u_front__q_data_in[71]
  PIN g_front_1_u_front__q_data_in[72]
    DIRECTION INPUT ;
    USE SIGNAL ;
    PORT
      LAYER M5 ;
        RECT  39.948 0 39.972 0.192 ;
    END
  END g_front_1_u_front__q_data_in[72]
  PIN g_front_1_u_front__q_data_in[73]
    DIRECTION INPUT ;
    USE SIGNAL ;
    PORT
      LAYER M5 ;
        RECT  40.284 0 40.308 0.192 ;
    END
  END g_front_1_u_front__q_data_in[73]
  PIN g_front_1_u_front__q_data_in[74]
    DIRECTION INPUT ;
    USE SIGNAL ;
    PORT
      LAYER M5 ;
        RECT  40.62 0 40.644 0.192 ;
    END
  END g_front_1_u_front__q_data_in[74]
  PIN g_front_1_u_front__q_data_in[75]
    DIRECTION INPUT ;
    USE SIGNAL ;
    PORT
      LAYER M5 ;
        RECT  40.956 0 40.98 0.192 ;
    END
  END g_front_1_u_front__q_data_in[75]
  PIN g_front_1_u_front__q_data_in[76]
    DIRECTION INPUT ;
    USE SIGNAL ;
    PORT
      LAYER M5 ;
        RECT  41.292 0 41.316 0.192 ;
    END
  END g_front_1_u_front__q_data_in[76]
  PIN g_front_1_u_front__q_data_in[77]
    DIRECTION INPUT ;
    USE SIGNAL ;
    PORT
      LAYER M5 ;
        RECT  41.628 0 41.652 0.192 ;
    END
  END g_front_1_u_front__q_data_in[77]
  PIN g_front_1_u_front__q_data_in[78]
    DIRECTION INPUT ;
    USE SIGNAL ;
    PORT
      LAYER M5 ;
        RECT  41.964 0 41.988 0.192 ;
    END
  END g_front_1_u_front__q_data_in[78]
  PIN g_front_1_u_front__q_data_in[79]
    DIRECTION INPUT ;
    USE SIGNAL ;
    PORT
      LAYER M5 ;
        RECT  42.348 0 42.372 0.192 ;
    END
  END g_front_1_u_front__q_data_in[79]
  PIN g_front_1_u_front__q_data_in[7]
    DIRECTION INPUT ;
    USE SIGNAL ;
    PORT
      LAYER M5 ;
        RECT  17.724 0 17.748 0.192 ;
    END
  END g_front_1_u_front__q_data_in[7]
  PIN g_front_1_u_front__q_data_in[80]
    DIRECTION INPUT ;
    USE SIGNAL ;
    PORT
      LAYER M5 ;
        RECT  42.684 0 42.708 0.192 ;
    END
  END g_front_1_u_front__q_data_in[80]
  PIN g_front_1_u_front__q_data_in[81]
    DIRECTION INPUT ;
    USE SIGNAL ;
    PORT
      LAYER M5 ;
        RECT  43.02 0 43.044 0.192 ;
    END
  END g_front_1_u_front__q_data_in[81]
  PIN g_front_1_u_front__q_data_in[82]
    DIRECTION INPUT ;
    USE SIGNAL ;
    PORT
      LAYER M5 ;
        RECT  43.356 0 43.38 0.192 ;
    END
  END g_front_1_u_front__q_data_in[82]
  PIN g_front_1_u_front__q_data_in[83]
    DIRECTION INPUT ;
    USE SIGNAL ;
    PORT
      LAYER M5 ;
        RECT  43.692 0 43.716 0.192 ;
    END
  END g_front_1_u_front__q_data_in[83]
  PIN g_front_1_u_front__q_data_in[84]
    DIRECTION INPUT ;
    USE SIGNAL ;
    PORT
      LAYER M5 ;
        RECT  44.028 0 44.052 0.192 ;
    END
  END g_front_1_u_front__q_data_in[84]
  PIN g_front_1_u_front__q_data_in[85]
    DIRECTION INPUT ;
    USE SIGNAL ;
    PORT
      LAYER M5 ;
        RECT  44.364 0 44.388 0.192 ;
    END
  END g_front_1_u_front__q_data_in[85]
  PIN g_front_1_u_front__q_data_in[86]
    DIRECTION INPUT ;
    USE SIGNAL ;
    PORT
      LAYER M5 ;
        RECT  44.7 0 44.724 0.192 ;
    END
  END g_front_1_u_front__q_data_in[86]
  PIN g_front_1_u_front__q_data_in[87]
    DIRECTION INPUT ;
    USE SIGNAL ;
    PORT
      LAYER M5 ;
        RECT  45.084 0 45.108 0.192 ;
    END
  END g_front_1_u_front__q_data_in[87]
  PIN g_front_1_u_front__q_data_in[88]
    DIRECTION INPUT ;
    USE SIGNAL ;
    PORT
      LAYER M5 ;
        RECT  45.42 0 45.444 0.192 ;
    END
  END g_front_1_u_front__q_data_in[88]
  PIN g_front_1_u_front__q_data_in[89]
    DIRECTION INPUT ;
    USE SIGNAL ;
    PORT
      LAYER M5 ;
        RECT  45.756 0 45.78 0.192 ;
    END
  END g_front_1_u_front__q_data_in[89]
  PIN g_front_1_u_front__q_data_in[8]
    DIRECTION INPUT ;
    USE SIGNAL ;
    PORT
      LAYER M5 ;
        RECT  18.06 0 18.084 0.192 ;
    END
  END g_front_1_u_front__q_data_in[8]
  PIN g_front_1_u_front__q_data_in[90]
    DIRECTION INPUT ;
    USE SIGNAL ;
    PORT
      LAYER M5 ;
        RECT  46.092 0 46.116 0.192 ;
    END
  END g_front_1_u_front__q_data_in[90]
  PIN g_front_1_u_front__q_data_in[91]
    DIRECTION INPUT ;
    USE SIGNAL ;
    PORT
      LAYER M5 ;
        RECT  46.428 0 46.452 0.192 ;
    END
  END g_front_1_u_front__q_data_in[91]
  PIN g_front_1_u_front__q_data_in[92]
    DIRECTION INPUT ;
    USE SIGNAL ;
    PORT
      LAYER M5 ;
        RECT  46.764 0 46.788 0.192 ;
    END
  END g_front_1_u_front__q_data_in[92]
  PIN g_front_1_u_front__q_data_in[93]
    DIRECTION INPUT ;
    USE SIGNAL ;
    PORT
      LAYER M5 ;
        RECT  47.1 0 47.124 0.192 ;
    END
  END g_front_1_u_front__q_data_in[93]
  PIN g_front_1_u_front__q_data_in[94]
    DIRECTION INPUT ;
    USE SIGNAL ;
    PORT
      LAYER M5 ;
        RECT  47.436 0 47.46 0.192 ;
    END
  END g_front_1_u_front__q_data_in[94]
  PIN g_front_1_u_front__q_data_in[95]
    DIRECTION INPUT ;
    USE SIGNAL ;
    PORT
      LAYER M5 ;
        RECT  47.82 0 47.844 0.192 ;
    END
  END g_front_1_u_front__q_data_in[95]
  PIN g_front_1_u_front__q_data_in[96]
    DIRECTION INPUT ;
    USE SIGNAL ;
    PORT
      LAYER M5 ;
        RECT  48.156 0 48.18 0.192 ;
    END
  END g_front_1_u_front__q_data_in[96]
  PIN g_front_1_u_front__q_data_in[97]
    DIRECTION INPUT ;
    USE SIGNAL ;
    PORT
      LAYER M5 ;
        RECT  48.492 0 48.516 0.192 ;
    END
  END g_front_1_u_front__q_data_in[97]
  PIN g_front_1_u_front__q_data_in[98]
    DIRECTION INPUT ;
    USE SIGNAL ;
    PORT
      LAYER M5 ;
        RECT  48.828 0 48.852 0.192 ;
    END
  END g_front_1_u_front__q_data_in[98]
  PIN g_front_1_u_front__q_data_in[99]
    DIRECTION INPUT ;
    USE SIGNAL ;
    PORT
      LAYER M5 ;
        RECT  49.164 0 49.188 0.192 ;
    END
  END g_front_1_u_front__q_data_in[99]
  PIN g_front_1_u_front__q_data_in[9]
    DIRECTION INPUT ;
    USE SIGNAL ;
    PORT
      LAYER M5 ;
        RECT  18.396 0 18.42 0.192 ;
    END
  END g_front_1_u_front__q_data_in[9]
  PIN g_front_1_u_front__q_valid_in[0]
    DIRECTION INPUT ;
    USE SIGNAL ;
    PORT
      LAYER M5 ;
        RECT  190.38 0 190.404 0.192 ;
    END
  END g_front_1_u_front__q_valid_in[0]
  PIN g_front_1_u_front__row_in[0]
    DIRECTION INPUT ;
    USE SIGNAL ;
    PORT
      LAYER M5 ;
        RECT  4.092 215.808 4.116 216 ;
    END
  END g_front_1_u_front__row_in[0]
  PIN g_front_1_u_front__row_in[100]
    DIRECTION INPUT ;
    USE SIGNAL ;
    PORT
      LAYER M5 ;
        RECT  82.812 215.808 82.836 216 ;
    END
  END g_front_1_u_front__row_in[100]
  PIN g_front_1_u_front__row_in[101]
    DIRECTION INPUT ;
    USE SIGNAL ;
    PORT
      LAYER M5 ;
        RECT  83.58 215.808 83.604 216 ;
    END
  END g_front_1_u_front__row_in[101]
  PIN g_front_1_u_front__row_in[102]
    DIRECTION INPUT ;
    USE SIGNAL ;
    PORT
      LAYER M5 ;
        RECT  84.396 215.808 84.42 216 ;
    END
  END g_front_1_u_front__row_in[102]
  PIN g_front_1_u_front__row_in[103]
    DIRECTION INPUT ;
    USE SIGNAL ;
    PORT
      LAYER M5 ;
        RECT  85.164 215.808 85.188 216 ;
    END
  END g_front_1_u_front__row_in[103]
  PIN g_front_1_u_front__row_in[104]
    DIRECTION INPUT ;
    USE SIGNAL ;
    PORT
      LAYER M5 ;
        RECT  85.932 215.808 85.956 216 ;
    END
  END g_front_1_u_front__row_in[104]
  PIN g_front_1_u_front__row_in[105]
    DIRECTION INPUT ;
    USE SIGNAL ;
    PORT
      LAYER M5 ;
        RECT  86.748 215.808 86.772 216 ;
    END
  END g_front_1_u_front__row_in[105]
  PIN g_front_1_u_front__row_in[106]
    DIRECTION INPUT ;
    USE SIGNAL ;
    PORT
      LAYER M5 ;
        RECT  87.516 215.808 87.54 216 ;
    END
  END g_front_1_u_front__row_in[106]
  PIN g_front_1_u_front__row_in[107]
    DIRECTION INPUT ;
    USE SIGNAL ;
    PORT
      LAYER M5 ;
        RECT  88.332 215.808 88.356 216 ;
    END
  END g_front_1_u_front__row_in[107]
  PIN g_front_1_u_front__row_in[108]
    DIRECTION INPUT ;
    USE SIGNAL ;
    PORT
      LAYER M5 ;
        RECT  89.1 215.808 89.124 216 ;
    END
  END g_front_1_u_front__row_in[108]
  PIN g_front_1_u_front__row_in[109]
    DIRECTION INPUT ;
    USE SIGNAL ;
    PORT
      LAYER M5 ;
        RECT  89.868 215.808 89.892 216 ;
    END
  END g_front_1_u_front__row_in[109]
  PIN g_front_1_u_front__row_in[10]
    DIRECTION INPUT ;
    USE SIGNAL ;
    PORT
      LAYER M5 ;
        RECT  11.964 215.808 11.988 216 ;
    END
  END g_front_1_u_front__row_in[10]
  PIN g_front_1_u_front__row_in[110]
    DIRECTION INPUT ;
    USE SIGNAL ;
    PORT
      LAYER M5 ;
        RECT  90.684 215.808 90.708 216 ;
    END
  END g_front_1_u_front__row_in[110]
  PIN g_front_1_u_front__row_in[111]
    DIRECTION INPUT ;
    USE SIGNAL ;
    PORT
      LAYER M5 ;
        RECT  91.452 215.808 91.476 216 ;
    END
  END g_front_1_u_front__row_in[111]
  PIN g_front_1_u_front__row_in[112]
    DIRECTION INPUT ;
    USE SIGNAL ;
    PORT
      LAYER M5 ;
        RECT  92.268 215.808 92.292 216 ;
    END
  END g_front_1_u_front__row_in[112]
  PIN g_front_1_u_front__row_in[113]
    DIRECTION INPUT ;
    USE SIGNAL ;
    PORT
      LAYER M5 ;
        RECT  93.036 215.808 93.06 216 ;
    END
  END g_front_1_u_front__row_in[113]
  PIN g_front_1_u_front__row_in[114]
    DIRECTION INPUT ;
    USE SIGNAL ;
    PORT
      LAYER M5 ;
        RECT  93.804 215.808 93.828 216 ;
    END
  END g_front_1_u_front__row_in[114]
  PIN g_front_1_u_front__row_in[115]
    DIRECTION INPUT ;
    USE SIGNAL ;
    PORT
      LAYER M5 ;
        RECT  94.62 215.808 94.644 216 ;
    END
  END g_front_1_u_front__row_in[115]
  PIN g_front_1_u_front__row_in[116]
    DIRECTION INPUT ;
    USE SIGNAL ;
    PORT
      LAYER M5 ;
        RECT  95.388 215.808 95.412 216 ;
    END
  END g_front_1_u_front__row_in[116]
  PIN g_front_1_u_front__row_in[117]
    DIRECTION INPUT ;
    USE SIGNAL ;
    PORT
      LAYER M5 ;
        RECT  96.204 215.808 96.228 216 ;
    END
  END g_front_1_u_front__row_in[117]
  PIN g_front_1_u_front__row_in[118]
    DIRECTION INPUT ;
    USE SIGNAL ;
    PORT
      LAYER M5 ;
        RECT  96.972 215.808 96.996 216 ;
    END
  END g_front_1_u_front__row_in[118]
  PIN g_front_1_u_front__row_in[119]
    DIRECTION INPUT ;
    USE SIGNAL ;
    PORT
      LAYER M5 ;
        RECT  97.74 215.808 97.764 216 ;
    END
  END g_front_1_u_front__row_in[119]
  PIN g_front_1_u_front__row_in[11]
    DIRECTION INPUT ;
    USE SIGNAL ;
    PORT
      LAYER M5 ;
        RECT  12.78 215.808 12.804 216 ;
    END
  END g_front_1_u_front__row_in[11]
  PIN g_front_1_u_front__row_in[120]
    DIRECTION INPUT ;
    USE SIGNAL ;
    PORT
      LAYER M5 ;
        RECT  98.556 215.808 98.58 216 ;
    END
  END g_front_1_u_front__row_in[120]
  PIN g_front_1_u_front__row_in[121]
    DIRECTION INPUT ;
    USE SIGNAL ;
    PORT
      LAYER M5 ;
        RECT  99.324 215.808 99.348 216 ;
    END
  END g_front_1_u_front__row_in[121]
  PIN g_front_1_u_front__row_in[122]
    DIRECTION INPUT ;
    USE SIGNAL ;
    PORT
      LAYER M5 ;
        RECT  100.14 215.808 100.164 216 ;
    END
  END g_front_1_u_front__row_in[122]
  PIN g_front_1_u_front__row_in[123]
    DIRECTION INPUT ;
    USE SIGNAL ;
    PORT
      LAYER M5 ;
        RECT  100.908 215.808 100.932 216 ;
    END
  END g_front_1_u_front__row_in[123]
  PIN g_front_1_u_front__row_in[124]
    DIRECTION INPUT ;
    USE SIGNAL ;
    PORT
      LAYER M5 ;
        RECT  101.676 215.808 101.7 216 ;
    END
  END g_front_1_u_front__row_in[124]
  PIN g_front_1_u_front__row_in[125]
    DIRECTION INPUT ;
    USE SIGNAL ;
    PORT
      LAYER M5 ;
        RECT  102.492 215.808 102.516 216 ;
    END
  END g_front_1_u_front__row_in[125]
  PIN g_front_1_u_front__row_in[126]
    DIRECTION INPUT ;
    USE SIGNAL ;
    PORT
      LAYER M5 ;
        RECT  103.26 215.808 103.284 216 ;
    END
  END g_front_1_u_front__row_in[126]
  PIN g_front_1_u_front__row_in[127]
    DIRECTION INPUT ;
    USE SIGNAL ;
    PORT
      LAYER M5 ;
        RECT  104.076 215.808 104.1 216 ;
    END
  END g_front_1_u_front__row_in[127]
  PIN g_front_1_u_front__row_in[128]
    DIRECTION INPUT ;
    USE SIGNAL ;
    PORT
      LAYER M5 ;
        RECT  104.844 215.808 104.868 216 ;
    END
  END g_front_1_u_front__row_in[128]
  PIN g_front_1_u_front__row_in[129]
    DIRECTION INPUT ;
    USE SIGNAL ;
    PORT
      LAYER M5 ;
        RECT  105.612 215.808 105.636 216 ;
    END
  END g_front_1_u_front__row_in[129]
  PIN g_front_1_u_front__row_in[12]
    DIRECTION INPUT ;
    USE SIGNAL ;
    PORT
      LAYER M5 ;
        RECT  13.548 215.808 13.572 216 ;
    END
  END g_front_1_u_front__row_in[12]
  PIN g_front_1_u_front__row_in[130]
    DIRECTION INPUT ;
    USE SIGNAL ;
    PORT
      LAYER M5 ;
        RECT  106.428 215.808 106.452 216 ;
    END
  END g_front_1_u_front__row_in[130]
  PIN g_front_1_u_front__row_in[131]
    DIRECTION INPUT ;
    USE SIGNAL ;
    PORT
      LAYER M5 ;
        RECT  107.196 215.808 107.22 216 ;
    END
  END g_front_1_u_front__row_in[131]
  PIN g_front_1_u_front__row_in[132]
    DIRECTION INPUT ;
    USE SIGNAL ;
    PORT
      LAYER M5 ;
        RECT  108.012 215.808 108.036 216 ;
    END
  END g_front_1_u_front__row_in[132]
  PIN g_front_1_u_front__row_in[133]
    DIRECTION INPUT ;
    USE SIGNAL ;
    PORT
      LAYER M5 ;
        RECT  108.78 215.808 108.804 216 ;
    END
  END g_front_1_u_front__row_in[133]
  PIN g_front_1_u_front__row_in[134]
    DIRECTION INPUT ;
    USE SIGNAL ;
    PORT
      LAYER M5 ;
        RECT  109.548 215.808 109.572 216 ;
    END
  END g_front_1_u_front__row_in[134]
  PIN g_front_1_u_front__row_in[135]
    DIRECTION INPUT ;
    USE SIGNAL ;
    PORT
      LAYER M5 ;
        RECT  110.364 215.808 110.388 216 ;
    END
  END g_front_1_u_front__row_in[135]
  PIN g_front_1_u_front__row_in[136]
    DIRECTION INPUT ;
    USE SIGNAL ;
    PORT
      LAYER M5 ;
        RECT  111.132 215.808 111.156 216 ;
    END
  END g_front_1_u_front__row_in[136]
  PIN g_front_1_u_front__row_in[137]
    DIRECTION INPUT ;
    USE SIGNAL ;
    PORT
      LAYER M5 ;
        RECT  111.9 215.808 111.924 216 ;
    END
  END g_front_1_u_front__row_in[137]
  PIN g_front_1_u_front__row_in[138]
    DIRECTION INPUT ;
    USE SIGNAL ;
    PORT
      LAYER M5 ;
        RECT  112.716 215.808 112.74 216 ;
    END
  END g_front_1_u_front__row_in[138]
  PIN g_front_1_u_front__row_in[139]
    DIRECTION INPUT ;
    USE SIGNAL ;
    PORT
      LAYER M5 ;
        RECT  113.484 215.808 113.508 216 ;
    END
  END g_front_1_u_front__row_in[139]
  PIN g_front_1_u_front__row_in[13]
    DIRECTION INPUT ;
    USE SIGNAL ;
    PORT
      LAYER M5 ;
        RECT  14.364 215.808 14.388 216 ;
    END
  END g_front_1_u_front__row_in[13]
  PIN g_front_1_u_front__row_in[140]
    DIRECTION INPUT ;
    USE SIGNAL ;
    PORT
      LAYER M5 ;
        RECT  114.3 215.808 114.324 216 ;
    END
  END g_front_1_u_front__row_in[140]
  PIN g_front_1_u_front__row_in[141]
    DIRECTION INPUT ;
    USE SIGNAL ;
    PORT
      LAYER M5 ;
        RECT  115.068 215.808 115.092 216 ;
    END
  END g_front_1_u_front__row_in[141]
  PIN g_front_1_u_front__row_in[142]
    DIRECTION INPUT ;
    USE SIGNAL ;
    PORT
      LAYER M5 ;
        RECT  115.836 215.808 115.86 216 ;
    END
  END g_front_1_u_front__row_in[142]
  PIN g_front_1_u_front__row_in[143]
    DIRECTION INPUT ;
    USE SIGNAL ;
    PORT
      LAYER M5 ;
        RECT  116.652 215.808 116.676 216 ;
    END
  END g_front_1_u_front__row_in[143]
  PIN g_front_1_u_front__row_in[144]
    DIRECTION INPUT ;
    USE SIGNAL ;
    PORT
      LAYER M5 ;
        RECT  117.42 215.808 117.444 216 ;
    END
  END g_front_1_u_front__row_in[144]
  PIN g_front_1_u_front__row_in[145]
    DIRECTION INPUT ;
    USE SIGNAL ;
    PORT
      LAYER M5 ;
        RECT  118.236 215.808 118.26 216 ;
    END
  END g_front_1_u_front__row_in[145]
  PIN g_front_1_u_front__row_in[146]
    DIRECTION INPUT ;
    USE SIGNAL ;
    PORT
      LAYER M5 ;
        RECT  119.004 215.808 119.028 216 ;
    END
  END g_front_1_u_front__row_in[146]
  PIN g_front_1_u_front__row_in[147]
    DIRECTION INPUT ;
    USE SIGNAL ;
    PORT
      LAYER M5 ;
        RECT  119.772 215.808 119.796 216 ;
    END
  END g_front_1_u_front__row_in[147]
  PIN g_front_1_u_front__row_in[148]
    DIRECTION INPUT ;
    USE SIGNAL ;
    PORT
      LAYER M5 ;
        RECT  120.588 215.808 120.612 216 ;
    END
  END g_front_1_u_front__row_in[148]
  PIN g_front_1_u_front__row_in[149]
    DIRECTION INPUT ;
    USE SIGNAL ;
    PORT
      LAYER M5 ;
        RECT  121.356 215.808 121.38 216 ;
    END
  END g_front_1_u_front__row_in[149]
  PIN g_front_1_u_front__row_in[14]
    DIRECTION INPUT ;
    USE SIGNAL ;
    PORT
      LAYER M5 ;
        RECT  15.132 215.808 15.156 216 ;
    END
  END g_front_1_u_front__row_in[14]
  PIN g_front_1_u_front__row_in[150]
    DIRECTION INPUT ;
    USE SIGNAL ;
    PORT
      LAYER M5 ;
        RECT  122.172 215.808 122.196 216 ;
    END
  END g_front_1_u_front__row_in[150]
  PIN g_front_1_u_front__row_in[151]
    DIRECTION INPUT ;
    USE SIGNAL ;
    PORT
      LAYER M5 ;
        RECT  122.94 215.808 122.964 216 ;
    END
  END g_front_1_u_front__row_in[151]
  PIN g_front_1_u_front__row_in[152]
    DIRECTION INPUT ;
    USE SIGNAL ;
    PORT
      LAYER M5 ;
        RECT  123.708 215.808 123.732 216 ;
    END
  END g_front_1_u_front__row_in[152]
  PIN g_front_1_u_front__row_in[153]
    DIRECTION INPUT ;
    USE SIGNAL ;
    PORT
      LAYER M5 ;
        RECT  124.524 215.808 124.548 216 ;
    END
  END g_front_1_u_front__row_in[153]
  PIN g_front_1_u_front__row_in[154]
    DIRECTION INPUT ;
    USE SIGNAL ;
    PORT
      LAYER M5 ;
        RECT  125.292 215.808 125.316 216 ;
    END
  END g_front_1_u_front__row_in[154]
  PIN g_front_1_u_front__row_in[155]
    DIRECTION INPUT ;
    USE SIGNAL ;
    PORT
      LAYER M5 ;
        RECT  126.108 215.808 126.132 216 ;
    END
  END g_front_1_u_front__row_in[155]
  PIN g_front_1_u_front__row_in[156]
    DIRECTION INPUT ;
    USE SIGNAL ;
    PORT
      LAYER M5 ;
        RECT  126.876 215.808 126.9 216 ;
    END
  END g_front_1_u_front__row_in[156]
  PIN g_front_1_u_front__row_in[157]
    DIRECTION INPUT ;
    USE SIGNAL ;
    PORT
      LAYER M5 ;
        RECT  127.644 215.808 127.668 216 ;
    END
  END g_front_1_u_front__row_in[157]
  PIN g_front_1_u_front__row_in[158]
    DIRECTION INPUT ;
    USE SIGNAL ;
    PORT
      LAYER M5 ;
        RECT  128.46 215.808 128.484 216 ;
    END
  END g_front_1_u_front__row_in[158]
  PIN g_front_1_u_front__row_in[159]
    DIRECTION INPUT ;
    USE SIGNAL ;
    PORT
      LAYER M5 ;
        RECT  129.228 215.808 129.252 216 ;
    END
  END g_front_1_u_front__row_in[159]
  PIN g_front_1_u_front__row_in[15]
    DIRECTION INPUT ;
    USE SIGNAL ;
    PORT
      LAYER M5 ;
        RECT  15.9 215.808 15.924 216 ;
    END
  END g_front_1_u_front__row_in[15]
  PIN g_front_1_u_front__row_in[160]
    DIRECTION INPUT ;
    USE SIGNAL ;
    PORT
      LAYER M5 ;
        RECT  130.044 215.808 130.068 216 ;
    END
  END g_front_1_u_front__row_in[160]
  PIN g_front_1_u_front__row_in[161]
    DIRECTION INPUT ;
    USE SIGNAL ;
    PORT
      LAYER M5 ;
        RECT  130.812 215.808 130.836 216 ;
    END
  END g_front_1_u_front__row_in[161]
  PIN g_front_1_u_front__row_in[162]
    DIRECTION INPUT ;
    USE SIGNAL ;
    PORT
      LAYER M5 ;
        RECT  131.58 215.808 131.604 216 ;
    END
  END g_front_1_u_front__row_in[162]
  PIN g_front_1_u_front__row_in[163]
    DIRECTION INPUT ;
    USE SIGNAL ;
    PORT
      LAYER M5 ;
        RECT  132.396 215.808 132.42 216 ;
    END
  END g_front_1_u_front__row_in[163]
  PIN g_front_1_u_front__row_in[164]
    DIRECTION INPUT ;
    USE SIGNAL ;
    PORT
      LAYER M5 ;
        RECT  133.164 215.808 133.188 216 ;
    END
  END g_front_1_u_front__row_in[164]
  PIN g_front_1_u_front__row_in[165]
    DIRECTION INPUT ;
    USE SIGNAL ;
    PORT
      LAYER M5 ;
        RECT  133.98 215.808 134.004 216 ;
    END
  END g_front_1_u_front__row_in[165]
  PIN g_front_1_u_front__row_in[166]
    DIRECTION INPUT ;
    USE SIGNAL ;
    PORT
      LAYER M5 ;
        RECT  134.748 215.808 134.772 216 ;
    END
  END g_front_1_u_front__row_in[166]
  PIN g_front_1_u_front__row_in[167]
    DIRECTION INPUT ;
    USE SIGNAL ;
    PORT
      LAYER M5 ;
        RECT  135.516 215.808 135.54 216 ;
    END
  END g_front_1_u_front__row_in[167]
  PIN g_front_1_u_front__row_in[168]
    DIRECTION INPUT ;
    USE SIGNAL ;
    PORT
      LAYER M5 ;
        RECT  136.332 215.808 136.356 216 ;
    END
  END g_front_1_u_front__row_in[168]
  PIN g_front_1_u_front__row_in[169]
    DIRECTION INPUT ;
    USE SIGNAL ;
    PORT
      LAYER M5 ;
        RECT  137.1 215.808 137.124 216 ;
    END
  END g_front_1_u_front__row_in[169]
  PIN g_front_1_u_front__row_in[16]
    DIRECTION INPUT ;
    USE SIGNAL ;
    PORT
      LAYER M5 ;
        RECT  16.716 215.808 16.74 216 ;
    END
  END g_front_1_u_front__row_in[16]
  PIN g_front_1_u_front__row_in[170]
    DIRECTION INPUT ;
    USE SIGNAL ;
    PORT
      LAYER M5 ;
        RECT  137.868 215.808 137.892 216 ;
    END
  END g_front_1_u_front__row_in[170]
  PIN g_front_1_u_front__row_in[171]
    DIRECTION INPUT ;
    USE SIGNAL ;
    PORT
      LAYER M5 ;
        RECT  138.684 215.808 138.708 216 ;
    END
  END g_front_1_u_front__row_in[171]
  PIN g_front_1_u_front__row_in[172]
    DIRECTION INPUT ;
    USE SIGNAL ;
    PORT
      LAYER M5 ;
        RECT  139.452 215.808 139.476 216 ;
    END
  END g_front_1_u_front__row_in[172]
  PIN g_front_1_u_front__row_in[173]
    DIRECTION INPUT ;
    USE SIGNAL ;
    PORT
      LAYER M5 ;
        RECT  140.268 215.808 140.292 216 ;
    END
  END g_front_1_u_front__row_in[173]
  PIN g_front_1_u_front__row_in[174]
    DIRECTION INPUT ;
    USE SIGNAL ;
    PORT
      LAYER M5 ;
        RECT  141.036 215.808 141.06 216 ;
    END
  END g_front_1_u_front__row_in[174]
  PIN g_front_1_u_front__row_in[175]
    DIRECTION INPUT ;
    USE SIGNAL ;
    PORT
      LAYER M5 ;
        RECT  141.804 215.808 141.828 216 ;
    END
  END g_front_1_u_front__row_in[175]
  PIN g_front_1_u_front__row_in[176]
    DIRECTION INPUT ;
    USE SIGNAL ;
    PORT
      LAYER M5 ;
        RECT  142.62 215.808 142.644 216 ;
    END
  END g_front_1_u_front__row_in[176]
  PIN g_front_1_u_front__row_in[177]
    DIRECTION INPUT ;
    USE SIGNAL ;
    PORT
      LAYER M5 ;
        RECT  143.388 215.808 143.412 216 ;
    END
  END g_front_1_u_front__row_in[177]
  PIN g_front_1_u_front__row_in[178]
    DIRECTION INPUT ;
    USE SIGNAL ;
    PORT
      LAYER M5 ;
        RECT  144.204 215.808 144.228 216 ;
    END
  END g_front_1_u_front__row_in[178]
  PIN g_front_1_u_front__row_in[179]
    DIRECTION INPUT ;
    USE SIGNAL ;
    PORT
      LAYER M5 ;
        RECT  144.972 215.808 144.996 216 ;
    END
  END g_front_1_u_front__row_in[179]
  PIN g_front_1_u_front__row_in[17]
    DIRECTION INPUT ;
    USE SIGNAL ;
    PORT
      LAYER M5 ;
        RECT  17.484 215.808 17.508 216 ;
    END
  END g_front_1_u_front__row_in[17]
  PIN g_front_1_u_front__row_in[180]
    DIRECTION INPUT ;
    USE SIGNAL ;
    PORT
      LAYER M5 ;
        RECT  145.74 215.808 145.764 216 ;
    END
  END g_front_1_u_front__row_in[180]
  PIN g_front_1_u_front__row_in[181]
    DIRECTION INPUT ;
    USE SIGNAL ;
    PORT
      LAYER M5 ;
        RECT  146.556 215.808 146.58 216 ;
    END
  END g_front_1_u_front__row_in[181]
  PIN g_front_1_u_front__row_in[182]
    DIRECTION INPUT ;
    USE SIGNAL ;
    PORT
      LAYER M5 ;
        RECT  147.324 215.808 147.348 216 ;
    END
  END g_front_1_u_front__row_in[182]
  PIN g_front_1_u_front__row_in[183]
    DIRECTION INPUT ;
    USE SIGNAL ;
    PORT
      LAYER M5 ;
        RECT  148.14 215.808 148.164 216 ;
    END
  END g_front_1_u_front__row_in[183]
  PIN g_front_1_u_front__row_in[184]
    DIRECTION INPUT ;
    USE SIGNAL ;
    PORT
      LAYER M5 ;
        RECT  148.908 215.808 148.932 216 ;
    END
  END g_front_1_u_front__row_in[184]
  PIN g_front_1_u_front__row_in[185]
    DIRECTION INPUT ;
    USE SIGNAL ;
    PORT
      LAYER M5 ;
        RECT  149.676 215.808 149.7 216 ;
    END
  END g_front_1_u_front__row_in[185]
  PIN g_front_1_u_front__row_in[186]
    DIRECTION INPUT ;
    USE SIGNAL ;
    PORT
      LAYER M5 ;
        RECT  150.492 215.808 150.516 216 ;
    END
  END g_front_1_u_front__row_in[186]
  PIN g_front_1_u_front__row_in[187]
    DIRECTION INPUT ;
    USE SIGNAL ;
    PORT
      LAYER M5 ;
        RECT  151.26 215.808 151.284 216 ;
    END
  END g_front_1_u_front__row_in[187]
  PIN g_front_1_u_front__row_in[188]
    DIRECTION INPUT ;
    USE SIGNAL ;
    PORT
      LAYER M5 ;
        RECT  152.076 215.808 152.1 216 ;
    END
  END g_front_1_u_front__row_in[188]
  PIN g_front_1_u_front__row_in[189]
    DIRECTION INPUT ;
    USE SIGNAL ;
    PORT
      LAYER M5 ;
        RECT  152.844 215.808 152.868 216 ;
    END
  END g_front_1_u_front__row_in[189]
  PIN g_front_1_u_front__row_in[18]
    DIRECTION INPUT ;
    USE SIGNAL ;
    PORT
      LAYER M5 ;
        RECT  18.3 215.808 18.324 216 ;
    END
  END g_front_1_u_front__row_in[18]
  PIN g_front_1_u_front__row_in[190]
    DIRECTION INPUT ;
    USE SIGNAL ;
    PORT
      LAYER M5 ;
        RECT  153.612 215.808 153.636 216 ;
    END
  END g_front_1_u_front__row_in[190]
  PIN g_front_1_u_front__row_in[191]
    DIRECTION INPUT ;
    USE SIGNAL ;
    PORT
      LAYER M5 ;
        RECT  154.428 215.808 154.452 216 ;
    END
  END g_front_1_u_front__row_in[191]
  PIN g_front_1_u_front__row_in[192]
    DIRECTION INPUT ;
    USE SIGNAL ;
    PORT
      LAYER M5 ;
        RECT  155.196 215.808 155.22 216 ;
    END
  END g_front_1_u_front__row_in[192]
  PIN g_front_1_u_front__row_in[193]
    DIRECTION INPUT ;
    USE SIGNAL ;
    PORT
      LAYER M5 ;
        RECT  156.012 215.808 156.036 216 ;
    END
  END g_front_1_u_front__row_in[193]
  PIN g_front_1_u_front__row_in[194]
    DIRECTION INPUT ;
    USE SIGNAL ;
    PORT
      LAYER M5 ;
        RECT  156.78 215.808 156.804 216 ;
    END
  END g_front_1_u_front__row_in[194]
  PIN g_front_1_u_front__row_in[195]
    DIRECTION INPUT ;
    USE SIGNAL ;
    PORT
      LAYER M5 ;
        RECT  157.548 215.808 157.572 216 ;
    END
  END g_front_1_u_front__row_in[195]
  PIN g_front_1_u_front__row_in[196]
    DIRECTION INPUT ;
    USE SIGNAL ;
    PORT
      LAYER M5 ;
        RECT  158.364 215.808 158.388 216 ;
    END
  END g_front_1_u_front__row_in[196]
  PIN g_front_1_u_front__row_in[197]
    DIRECTION INPUT ;
    USE SIGNAL ;
    PORT
      LAYER M5 ;
        RECT  159.132 215.808 159.156 216 ;
    END
  END g_front_1_u_front__row_in[197]
  PIN g_front_1_u_front__row_in[198]
    DIRECTION INPUT ;
    USE SIGNAL ;
    PORT
      LAYER M5 ;
        RECT  159.948 215.808 159.972 216 ;
    END
  END g_front_1_u_front__row_in[198]
  PIN g_front_1_u_front__row_in[199]
    DIRECTION INPUT ;
    USE SIGNAL ;
    PORT
      LAYER M5 ;
        RECT  160.716 215.808 160.74 216 ;
    END
  END g_front_1_u_front__row_in[199]
  PIN g_front_1_u_front__row_in[19]
    DIRECTION INPUT ;
    USE SIGNAL ;
    PORT
      LAYER M5 ;
        RECT  19.068 215.808 19.092 216 ;
    END
  END g_front_1_u_front__row_in[19]
  PIN g_front_1_u_front__row_in[1]
    DIRECTION INPUT ;
    USE SIGNAL ;
    PORT
      LAYER M5 ;
        RECT  4.908 215.808 4.932 216 ;
    END
  END g_front_1_u_front__row_in[1]
  PIN g_front_1_u_front__row_in[200]
    DIRECTION INPUT ;
    USE SIGNAL ;
    PORT
      LAYER M5 ;
        RECT  161.484 215.808 161.508 216 ;
    END
  END g_front_1_u_front__row_in[200]
  PIN g_front_1_u_front__row_in[201]
    DIRECTION INPUT ;
    USE SIGNAL ;
    PORT
      LAYER M5 ;
        RECT  162.3 215.808 162.324 216 ;
    END
  END g_front_1_u_front__row_in[201]
  PIN g_front_1_u_front__row_in[202]
    DIRECTION INPUT ;
    USE SIGNAL ;
    PORT
      LAYER M5 ;
        RECT  163.068 215.808 163.092 216 ;
    END
  END g_front_1_u_front__row_in[202]
  PIN g_front_1_u_front__row_in[203]
    DIRECTION INPUT ;
    USE SIGNAL ;
    PORT
      LAYER M5 ;
        RECT  163.836 215.808 163.86 216 ;
    END
  END g_front_1_u_front__row_in[203]
  PIN g_front_1_u_front__row_in[204]
    DIRECTION INPUT ;
    USE SIGNAL ;
    PORT
      LAYER M5 ;
        RECT  164.652 215.808 164.676 216 ;
    END
  END g_front_1_u_front__row_in[204]
  PIN g_front_1_u_front__row_in[205]
    DIRECTION INPUT ;
    USE SIGNAL ;
    PORT
      LAYER M5 ;
        RECT  165.42 215.808 165.444 216 ;
    END
  END g_front_1_u_front__row_in[205]
  PIN g_front_1_u_front__row_in[206]
    DIRECTION INPUT ;
    USE SIGNAL ;
    PORT
      LAYER M5 ;
        RECT  166.236 215.808 166.26 216 ;
    END
  END g_front_1_u_front__row_in[206]
  PIN g_front_1_u_front__row_in[207]
    DIRECTION INPUT ;
    USE SIGNAL ;
    PORT
      LAYER M5 ;
        RECT  167.004 215.808 167.028 216 ;
    END
  END g_front_1_u_front__row_in[207]
  PIN g_front_1_u_front__row_in[208]
    DIRECTION INPUT ;
    USE SIGNAL ;
    PORT
      LAYER M5 ;
        RECT  167.772 215.808 167.796 216 ;
    END
  END g_front_1_u_front__row_in[208]
  PIN g_front_1_u_front__row_in[209]
    DIRECTION INPUT ;
    USE SIGNAL ;
    PORT
      LAYER M5 ;
        RECT  168.588 215.808 168.612 216 ;
    END
  END g_front_1_u_front__row_in[209]
  PIN g_front_1_u_front__row_in[20]
    DIRECTION INPUT ;
    USE SIGNAL ;
    PORT
      LAYER M5 ;
        RECT  19.836 215.808 19.86 216 ;
    END
  END g_front_1_u_front__row_in[20]
  PIN g_front_1_u_front__row_in[210]
    DIRECTION INPUT ;
    USE SIGNAL ;
    PORT
      LAYER M5 ;
        RECT  169.356 215.808 169.38 216 ;
    END
  END g_front_1_u_front__row_in[210]
  PIN g_front_1_u_front__row_in[211]
    DIRECTION INPUT ;
    USE SIGNAL ;
    PORT
      LAYER M5 ;
        RECT  170.172 215.808 170.196 216 ;
    END
  END g_front_1_u_front__row_in[211]
  PIN g_front_1_u_front__row_in[212]
    DIRECTION INPUT ;
    USE SIGNAL ;
    PORT
      LAYER M5 ;
        RECT  170.94 215.808 170.964 216 ;
    END
  END g_front_1_u_front__row_in[212]
  PIN g_front_1_u_front__row_in[213]
    DIRECTION INPUT ;
    USE SIGNAL ;
    PORT
      LAYER M5 ;
        RECT  171.708 215.808 171.732 216 ;
    END
  END g_front_1_u_front__row_in[213]
  PIN g_front_1_u_front__row_in[214]
    DIRECTION INPUT ;
    USE SIGNAL ;
    PORT
      LAYER M5 ;
        RECT  172.524 215.808 172.548 216 ;
    END
  END g_front_1_u_front__row_in[214]
  PIN g_front_1_u_front__row_in[215]
    DIRECTION INPUT ;
    USE SIGNAL ;
    PORT
      LAYER M5 ;
        RECT  173.292 215.808 173.316 216 ;
    END
  END g_front_1_u_front__row_in[215]
  PIN g_front_1_u_front__row_in[216]
    DIRECTION INPUT ;
    USE SIGNAL ;
    PORT
      LAYER M5 ;
        RECT  174.108 215.808 174.132 216 ;
    END
  END g_front_1_u_front__row_in[216]
  PIN g_front_1_u_front__row_in[217]
    DIRECTION INPUT ;
    USE SIGNAL ;
    PORT
      LAYER M5 ;
        RECT  174.876 215.808 174.9 216 ;
    END
  END g_front_1_u_front__row_in[217]
  PIN g_front_1_u_front__row_in[218]
    DIRECTION INPUT ;
    USE SIGNAL ;
    PORT
      LAYER M5 ;
        RECT  175.644 215.808 175.668 216 ;
    END
  END g_front_1_u_front__row_in[218]
  PIN g_front_1_u_front__row_in[219]
    DIRECTION INPUT ;
    USE SIGNAL ;
    PORT
      LAYER M5 ;
        RECT  176.46 215.808 176.484 216 ;
    END
  END g_front_1_u_front__row_in[219]
  PIN g_front_1_u_front__row_in[21]
    DIRECTION INPUT ;
    USE SIGNAL ;
    PORT
      LAYER M5 ;
        RECT  20.652 215.808 20.676 216 ;
    END
  END g_front_1_u_front__row_in[21]
  PIN g_front_1_u_front__row_in[220]
    DIRECTION INPUT ;
    USE SIGNAL ;
    PORT
      LAYER M5 ;
        RECT  177.228 215.808 177.252 216 ;
    END
  END g_front_1_u_front__row_in[220]
  PIN g_front_1_u_front__row_in[221]
    DIRECTION INPUT ;
    USE SIGNAL ;
    PORT
      LAYER M5 ;
        RECT  178.044 215.808 178.068 216 ;
    END
  END g_front_1_u_front__row_in[221]
  PIN g_front_1_u_front__row_in[222]
    DIRECTION INPUT ;
    USE SIGNAL ;
    PORT
      LAYER M5 ;
        RECT  178.812 215.808 178.836 216 ;
    END
  END g_front_1_u_front__row_in[222]
  PIN g_front_1_u_front__row_in[223]
    DIRECTION INPUT ;
    USE SIGNAL ;
    PORT
      LAYER M5 ;
        RECT  179.58 215.808 179.604 216 ;
    END
  END g_front_1_u_front__row_in[223]
  PIN g_front_1_u_front__row_in[224]
    DIRECTION INPUT ;
    USE SIGNAL ;
    PORT
      LAYER M5 ;
        RECT  180.396 215.808 180.42 216 ;
    END
  END g_front_1_u_front__row_in[224]
  PIN g_front_1_u_front__row_in[225]
    DIRECTION INPUT ;
    USE SIGNAL ;
    PORT
      LAYER M5 ;
        RECT  181.164 215.808 181.188 216 ;
    END
  END g_front_1_u_front__row_in[225]
  PIN g_front_1_u_front__row_in[226]
    DIRECTION INPUT ;
    USE SIGNAL ;
    PORT
      LAYER M5 ;
        RECT  181.98 215.808 182.004 216 ;
    END
  END g_front_1_u_front__row_in[226]
  PIN g_front_1_u_front__row_in[227]
    DIRECTION INPUT ;
    USE SIGNAL ;
    PORT
      LAYER M5 ;
        RECT  182.748 215.808 182.772 216 ;
    END
  END g_front_1_u_front__row_in[227]
  PIN g_front_1_u_front__row_in[228]
    DIRECTION INPUT ;
    USE SIGNAL ;
    PORT
      LAYER M5 ;
        RECT  183.516 215.808 183.54 216 ;
    END
  END g_front_1_u_front__row_in[228]
  PIN g_front_1_u_front__row_in[229]
    DIRECTION INPUT ;
    USE SIGNAL ;
    PORT
      LAYER M5 ;
        RECT  184.332 215.808 184.356 216 ;
    END
  END g_front_1_u_front__row_in[229]
  PIN g_front_1_u_front__row_in[22]
    DIRECTION INPUT ;
    USE SIGNAL ;
    PORT
      LAYER M5 ;
        RECT  21.42 215.808 21.444 216 ;
    END
  END g_front_1_u_front__row_in[22]
  PIN g_front_1_u_front__row_in[230]
    DIRECTION INPUT ;
    USE SIGNAL ;
    PORT
      LAYER M5 ;
        RECT  185.1 215.808 185.124 216 ;
    END
  END g_front_1_u_front__row_in[230]
  PIN g_front_1_u_front__row_in[231]
    DIRECTION INPUT ;
    USE SIGNAL ;
    PORT
      LAYER M5 ;
        RECT  185.916 215.808 185.94 216 ;
    END
  END g_front_1_u_front__row_in[231]
  PIN g_front_1_u_front__row_in[232]
    DIRECTION INPUT ;
    USE SIGNAL ;
    PORT
      LAYER M5 ;
        RECT  186.684 215.808 186.708 216 ;
    END
  END g_front_1_u_front__row_in[232]
  PIN g_front_1_u_front__row_in[233]
    DIRECTION INPUT ;
    USE SIGNAL ;
    PORT
      LAYER M5 ;
        RECT  187.452 215.808 187.476 216 ;
    END
  END g_front_1_u_front__row_in[233]
  PIN g_front_1_u_front__row_in[234]
    DIRECTION INPUT ;
    USE SIGNAL ;
    PORT
      LAYER M5 ;
        RECT  188.268 215.808 188.292 216 ;
    END
  END g_front_1_u_front__row_in[234]
  PIN g_front_1_u_front__row_in[235]
    DIRECTION INPUT ;
    USE SIGNAL ;
    PORT
      LAYER M5 ;
        RECT  189.036 215.808 189.06 216 ;
    END
  END g_front_1_u_front__row_in[235]
  PIN g_front_1_u_front__row_in[236]
    DIRECTION INPUT ;
    USE SIGNAL ;
    PORT
      LAYER M5 ;
        RECT  189.804 215.808 189.828 216 ;
    END
  END g_front_1_u_front__row_in[236]
  PIN g_front_1_u_front__row_in[237]
    DIRECTION INPUT ;
    USE SIGNAL ;
    PORT
      LAYER M5 ;
        RECT  190.62 215.808 190.644 216 ;
    END
  END g_front_1_u_front__row_in[237]
  PIN g_front_1_u_front__row_in[238]
    DIRECTION INPUT ;
    USE SIGNAL ;
    PORT
      LAYER M5 ;
        RECT  191.388 215.808 191.412 216 ;
    END
  END g_front_1_u_front__row_in[238]
  PIN g_front_1_u_front__row_in[239]
    DIRECTION INPUT ;
    USE SIGNAL ;
    PORT
      LAYER M5 ;
        RECT  192.204 215.808 192.228 216 ;
    END
  END g_front_1_u_front__row_in[239]
  PIN g_front_1_u_front__row_in[23]
    DIRECTION INPUT ;
    USE SIGNAL ;
    PORT
      LAYER M5 ;
        RECT  22.236 215.808 22.26 216 ;
    END
  END g_front_1_u_front__row_in[23]
  PIN g_front_1_u_front__row_in[240]
    DIRECTION INPUT ;
    USE SIGNAL ;
    PORT
      LAYER M5 ;
        RECT  192.972 215.808 192.996 216 ;
    END
  END g_front_1_u_front__row_in[240]
  PIN g_front_1_u_front__row_in[241]
    DIRECTION INPUT ;
    USE SIGNAL ;
    PORT
      LAYER M5 ;
        RECT  193.74 215.808 193.764 216 ;
    END
  END g_front_1_u_front__row_in[241]
  PIN g_front_1_u_front__row_in[242]
    DIRECTION INPUT ;
    USE SIGNAL ;
    PORT
      LAYER M5 ;
        RECT  194.556 215.808 194.58 216 ;
    END
  END g_front_1_u_front__row_in[242]
  PIN g_front_1_u_front__row_in[243]
    DIRECTION INPUT ;
    USE SIGNAL ;
    PORT
      LAYER M5 ;
        RECT  195.324 215.808 195.348 216 ;
    END
  END g_front_1_u_front__row_in[243]
  PIN g_front_1_u_front__row_in[244]
    DIRECTION INPUT ;
    USE SIGNAL ;
    PORT
      LAYER M5 ;
        RECT  196.14 215.808 196.164 216 ;
    END
  END g_front_1_u_front__row_in[244]
  PIN g_front_1_u_front__row_in[245]
    DIRECTION INPUT ;
    USE SIGNAL ;
    PORT
      LAYER M5 ;
        RECT  196.908 215.808 196.932 216 ;
    END
  END g_front_1_u_front__row_in[245]
  PIN g_front_1_u_front__row_in[246]
    DIRECTION INPUT ;
    USE SIGNAL ;
    PORT
      LAYER M5 ;
        RECT  197.676 215.808 197.7 216 ;
    END
  END g_front_1_u_front__row_in[246]
  PIN g_front_1_u_front__row_in[247]
    DIRECTION INPUT ;
    USE SIGNAL ;
    PORT
      LAYER M5 ;
        RECT  198.492 215.808 198.516 216 ;
    END
  END g_front_1_u_front__row_in[247]
  PIN g_front_1_u_front__row_in[248]
    DIRECTION INPUT ;
    USE SIGNAL ;
    PORT
      LAYER M5 ;
        RECT  199.26 215.808 199.284 216 ;
    END
  END g_front_1_u_front__row_in[248]
  PIN g_front_1_u_front__row_in[249]
    DIRECTION INPUT ;
    USE SIGNAL ;
    PORT
      LAYER M5 ;
        RECT  200.076 215.808 200.1 216 ;
    END
  END g_front_1_u_front__row_in[249]
  PIN g_front_1_u_front__row_in[24]
    DIRECTION INPUT ;
    USE SIGNAL ;
    PORT
      LAYER M5 ;
        RECT  23.004 215.808 23.028 216 ;
    END
  END g_front_1_u_front__row_in[24]
  PIN g_front_1_u_front__row_in[250]
    DIRECTION INPUT ;
    USE SIGNAL ;
    PORT
      LAYER M5 ;
        RECT  200.844 215.808 200.868 216 ;
    END
  END g_front_1_u_front__row_in[250]
  PIN g_front_1_u_front__row_in[251]
    DIRECTION INPUT ;
    USE SIGNAL ;
    PORT
      LAYER M5 ;
        RECT  201.612 215.808 201.636 216 ;
    END
  END g_front_1_u_front__row_in[251]
  PIN g_front_1_u_front__row_in[252]
    DIRECTION INPUT ;
    USE SIGNAL ;
    PORT
      LAYER M5 ;
        RECT  202.428 215.808 202.452 216 ;
    END
  END g_front_1_u_front__row_in[252]
  PIN g_front_1_u_front__row_in[253]
    DIRECTION INPUT ;
    USE SIGNAL ;
    PORT
      LAYER M5 ;
        RECT  203.196 215.808 203.22 216 ;
    END
  END g_front_1_u_front__row_in[253]
  PIN g_front_1_u_front__row_in[254]
    DIRECTION INPUT ;
    USE SIGNAL ;
    PORT
      LAYER M5 ;
        RECT  204.012 215.808 204.036 216 ;
    END
  END g_front_1_u_front__row_in[254]
  PIN g_front_1_u_front__row_in[255]
    DIRECTION INPUT ;
    USE SIGNAL ;
    PORT
      LAYER M5 ;
        RECT  204.78 215.808 204.804 216 ;
    END
  END g_front_1_u_front__row_in[255]
  PIN g_front_1_u_front__row_in[25]
    DIRECTION INPUT ;
    USE SIGNAL ;
    PORT
      LAYER M5 ;
        RECT  23.772 215.808 23.796 216 ;
    END
  END g_front_1_u_front__row_in[25]
  PIN g_front_1_u_front__row_in[26]
    DIRECTION INPUT ;
    USE SIGNAL ;
    PORT
      LAYER M5 ;
        RECT  24.588 215.808 24.612 216 ;
    END
  END g_front_1_u_front__row_in[26]
  PIN g_front_1_u_front__row_in[27]
    DIRECTION INPUT ;
    USE SIGNAL ;
    PORT
      LAYER M5 ;
        RECT  25.356 215.808 25.38 216 ;
    END
  END g_front_1_u_front__row_in[27]
  PIN g_front_1_u_front__row_in[28]
    DIRECTION INPUT ;
    USE SIGNAL ;
    PORT
      LAYER M5 ;
        RECT  26.172 215.808 26.196 216 ;
    END
  END g_front_1_u_front__row_in[28]
  PIN g_front_1_u_front__row_in[29]
    DIRECTION INPUT ;
    USE SIGNAL ;
    PORT
      LAYER M5 ;
        RECT  26.94 215.808 26.964 216 ;
    END
  END g_front_1_u_front__row_in[29]
  PIN g_front_1_u_front__row_in[2]
    DIRECTION INPUT ;
    USE SIGNAL ;
    PORT
      LAYER M5 ;
        RECT  5.676 215.808 5.7 216 ;
    END
  END g_front_1_u_front__row_in[2]
  PIN g_front_1_u_front__row_in[30]
    DIRECTION INPUT ;
    USE SIGNAL ;
    PORT
      LAYER M5 ;
        RECT  27.708 215.808 27.732 216 ;
    END
  END g_front_1_u_front__row_in[30]
  PIN g_front_1_u_front__row_in[31]
    DIRECTION INPUT ;
    USE SIGNAL ;
    PORT
      LAYER M5 ;
        RECT  28.524 215.808 28.548 216 ;
    END
  END g_front_1_u_front__row_in[31]
  PIN g_front_1_u_front__row_in[32]
    DIRECTION INPUT ;
    USE SIGNAL ;
    PORT
      LAYER M5 ;
        RECT  29.292 215.808 29.316 216 ;
    END
  END g_front_1_u_front__row_in[32]
  PIN g_front_1_u_front__row_in[33]
    DIRECTION INPUT ;
    USE SIGNAL ;
    PORT
      LAYER M5 ;
        RECT  30.06 215.808 30.084 216 ;
    END
  END g_front_1_u_front__row_in[33]
  PIN g_front_1_u_front__row_in[34]
    DIRECTION INPUT ;
    USE SIGNAL ;
    PORT
      LAYER M5 ;
        RECT  30.876 215.808 30.9 216 ;
    END
  END g_front_1_u_front__row_in[34]
  PIN g_front_1_u_front__row_in[35]
    DIRECTION INPUT ;
    USE SIGNAL ;
    PORT
      LAYER M5 ;
        RECT  31.644 215.808 31.668 216 ;
    END
  END g_front_1_u_front__row_in[35]
  PIN g_front_1_u_front__row_in[36]
    DIRECTION INPUT ;
    USE SIGNAL ;
    PORT
      LAYER M5 ;
        RECT  32.46 215.808 32.484 216 ;
    END
  END g_front_1_u_front__row_in[36]
  PIN g_front_1_u_front__row_in[37]
    DIRECTION INPUT ;
    USE SIGNAL ;
    PORT
      LAYER M5 ;
        RECT  33.228 215.808 33.252 216 ;
    END
  END g_front_1_u_front__row_in[37]
  PIN g_front_1_u_front__row_in[38]
    DIRECTION INPUT ;
    USE SIGNAL ;
    PORT
      LAYER M5 ;
        RECT  33.996 215.808 34.02 216 ;
    END
  END g_front_1_u_front__row_in[38]
  PIN g_front_1_u_front__row_in[39]
    DIRECTION INPUT ;
    USE SIGNAL ;
    PORT
      LAYER M5 ;
        RECT  34.812 215.808 34.836 216 ;
    END
  END g_front_1_u_front__row_in[39]
  PIN g_front_1_u_front__row_in[3]
    DIRECTION INPUT ;
    USE SIGNAL ;
    PORT
      LAYER M5 ;
        RECT  6.492 215.808 6.516 216 ;
    END
  END g_front_1_u_front__row_in[3]
  PIN g_front_1_u_front__row_in[40]
    DIRECTION INPUT ;
    USE SIGNAL ;
    PORT
      LAYER M5 ;
        RECT  35.58 215.808 35.604 216 ;
    END
  END g_front_1_u_front__row_in[40]
  PIN g_front_1_u_front__row_in[41]
    DIRECTION INPUT ;
    USE SIGNAL ;
    PORT
      LAYER M5 ;
        RECT  36.396 215.808 36.42 216 ;
    END
  END g_front_1_u_front__row_in[41]
  PIN g_front_1_u_front__row_in[42]
    DIRECTION INPUT ;
    USE SIGNAL ;
    PORT
      LAYER M5 ;
        RECT  37.164 215.808 37.188 216 ;
    END
  END g_front_1_u_front__row_in[42]
  PIN g_front_1_u_front__row_in[43]
    DIRECTION INPUT ;
    USE SIGNAL ;
    PORT
      LAYER M5 ;
        RECT  37.932 215.808 37.956 216 ;
    END
  END g_front_1_u_front__row_in[43]
  PIN g_front_1_u_front__row_in[44]
    DIRECTION INPUT ;
    USE SIGNAL ;
    PORT
      LAYER M5 ;
        RECT  38.748 215.808 38.772 216 ;
    END
  END g_front_1_u_front__row_in[44]
  PIN g_front_1_u_front__row_in[45]
    DIRECTION INPUT ;
    USE SIGNAL ;
    PORT
      LAYER M5 ;
        RECT  39.516 215.808 39.54 216 ;
    END
  END g_front_1_u_front__row_in[45]
  PIN g_front_1_u_front__row_in[46]
    DIRECTION INPUT ;
    USE SIGNAL ;
    PORT
      LAYER M5 ;
        RECT  40.332 215.808 40.356 216 ;
    END
  END g_front_1_u_front__row_in[46]
  PIN g_front_1_u_front__row_in[47]
    DIRECTION INPUT ;
    USE SIGNAL ;
    PORT
      LAYER M5 ;
        RECT  41.1 215.808 41.124 216 ;
    END
  END g_front_1_u_front__row_in[47]
  PIN g_front_1_u_front__row_in[48]
    DIRECTION INPUT ;
    USE SIGNAL ;
    PORT
      LAYER M5 ;
        RECT  41.868 215.808 41.892 216 ;
    END
  END g_front_1_u_front__row_in[48]
  PIN g_front_1_u_front__row_in[49]
    DIRECTION INPUT ;
    USE SIGNAL ;
    PORT
      LAYER M5 ;
        RECT  42.684 215.808 42.708 216 ;
    END
  END g_front_1_u_front__row_in[49]
  PIN g_front_1_u_front__row_in[4]
    DIRECTION INPUT ;
    USE SIGNAL ;
    PORT
      LAYER M5 ;
        RECT  7.26 215.808 7.284 216 ;
    END
  END g_front_1_u_front__row_in[4]
  PIN g_front_1_u_front__row_in[50]
    DIRECTION INPUT ;
    USE SIGNAL ;
    PORT
      LAYER M5 ;
        RECT  43.452 215.808 43.476 216 ;
    END
  END g_front_1_u_front__row_in[50]
  PIN g_front_1_u_front__row_in[51]
    DIRECTION INPUT ;
    USE SIGNAL ;
    PORT
      LAYER M5 ;
        RECT  44.268 215.808 44.292 216 ;
    END
  END g_front_1_u_front__row_in[51]
  PIN g_front_1_u_front__row_in[52]
    DIRECTION INPUT ;
    USE SIGNAL ;
    PORT
      LAYER M5 ;
        RECT  45.036 215.808 45.06 216 ;
    END
  END g_front_1_u_front__row_in[52]
  PIN g_front_1_u_front__row_in[53]
    DIRECTION INPUT ;
    USE SIGNAL ;
    PORT
      LAYER M5 ;
        RECT  45.804 215.808 45.828 216 ;
    END
  END g_front_1_u_front__row_in[53]
  PIN g_front_1_u_front__row_in[54]
    DIRECTION INPUT ;
    USE SIGNAL ;
    PORT
      LAYER M5 ;
        RECT  46.62 215.808 46.644 216 ;
    END
  END g_front_1_u_front__row_in[54]
  PIN g_front_1_u_front__row_in[55]
    DIRECTION INPUT ;
    USE SIGNAL ;
    PORT
      LAYER M5 ;
        RECT  47.388 215.808 47.412 216 ;
    END
  END g_front_1_u_front__row_in[55]
  PIN g_front_1_u_front__row_in[56]
    DIRECTION INPUT ;
    USE SIGNAL ;
    PORT
      LAYER M5 ;
        RECT  48.204 215.808 48.228 216 ;
    END
  END g_front_1_u_front__row_in[56]
  PIN g_front_1_u_front__row_in[57]
    DIRECTION INPUT ;
    USE SIGNAL ;
    PORT
      LAYER M5 ;
        RECT  48.972 215.808 48.996 216 ;
    END
  END g_front_1_u_front__row_in[57]
  PIN g_front_1_u_front__row_in[58]
    DIRECTION INPUT ;
    USE SIGNAL ;
    PORT
      LAYER M5 ;
        RECT  49.74 215.808 49.764 216 ;
    END
  END g_front_1_u_front__row_in[58]
  PIN g_front_1_u_front__row_in[59]
    DIRECTION INPUT ;
    USE SIGNAL ;
    PORT
      LAYER M5 ;
        RECT  50.556 215.808 50.58 216 ;
    END
  END g_front_1_u_front__row_in[59]
  PIN g_front_1_u_front__row_in[5]
    DIRECTION INPUT ;
    USE SIGNAL ;
    PORT
      LAYER M5 ;
        RECT  8.028 215.808 8.052 216 ;
    END
  END g_front_1_u_front__row_in[5]
  PIN g_front_1_u_front__row_in[60]
    DIRECTION INPUT ;
    USE SIGNAL ;
    PORT
      LAYER M5 ;
        RECT  51.324 215.808 51.348 216 ;
    END
  END g_front_1_u_front__row_in[60]
  PIN g_front_1_u_front__row_in[61]
    DIRECTION INPUT ;
    USE SIGNAL ;
    PORT
      LAYER M5 ;
        RECT  52.14 215.808 52.164 216 ;
    END
  END g_front_1_u_front__row_in[61]
  PIN g_front_1_u_front__row_in[62]
    DIRECTION INPUT ;
    USE SIGNAL ;
    PORT
      LAYER M5 ;
        RECT  52.908 215.808 52.932 216 ;
    END
  END g_front_1_u_front__row_in[62]
  PIN g_front_1_u_front__row_in[63]
    DIRECTION INPUT ;
    USE SIGNAL ;
    PORT
      LAYER M5 ;
        RECT  53.676 215.808 53.7 216 ;
    END
  END g_front_1_u_front__row_in[63]
  PIN g_front_1_u_front__row_in[64]
    DIRECTION INPUT ;
    USE SIGNAL ;
    PORT
      LAYER M5 ;
        RECT  54.492 215.808 54.516 216 ;
    END
  END g_front_1_u_front__row_in[64]
  PIN g_front_1_u_front__row_in[65]
    DIRECTION INPUT ;
    USE SIGNAL ;
    PORT
      LAYER M5 ;
        RECT  55.26 215.808 55.284 216 ;
    END
  END g_front_1_u_front__row_in[65]
  PIN g_front_1_u_front__row_in[66]
    DIRECTION INPUT ;
    USE SIGNAL ;
    PORT
      LAYER M5 ;
        RECT  56.028 215.808 56.052 216 ;
    END
  END g_front_1_u_front__row_in[66]
  PIN g_front_1_u_front__row_in[67]
    DIRECTION INPUT ;
    USE SIGNAL ;
    PORT
      LAYER M5 ;
        RECT  56.844 215.808 56.868 216 ;
    END
  END g_front_1_u_front__row_in[67]
  PIN g_front_1_u_front__row_in[68]
    DIRECTION INPUT ;
    USE SIGNAL ;
    PORT
      LAYER M5 ;
        RECT  57.612 215.808 57.636 216 ;
    END
  END g_front_1_u_front__row_in[68]
  PIN g_front_1_u_front__row_in[69]
    DIRECTION INPUT ;
    USE SIGNAL ;
    PORT
      LAYER M5 ;
        RECT  58.428 215.808 58.452 216 ;
    END
  END g_front_1_u_front__row_in[69]
  PIN g_front_1_u_front__row_in[6]
    DIRECTION INPUT ;
    USE SIGNAL ;
    PORT
      LAYER M5 ;
        RECT  8.844 215.808 8.868 216 ;
    END
  END g_front_1_u_front__row_in[6]
  PIN g_front_1_u_front__row_in[70]
    DIRECTION INPUT ;
    USE SIGNAL ;
    PORT
      LAYER M5 ;
        RECT  59.196 215.808 59.22 216 ;
    END
  END g_front_1_u_front__row_in[70]
  PIN g_front_1_u_front__row_in[71]
    DIRECTION INPUT ;
    USE SIGNAL ;
    PORT
      LAYER M5 ;
        RECT  59.964 215.808 59.988 216 ;
    END
  END g_front_1_u_front__row_in[71]
  PIN g_front_1_u_front__row_in[72]
    DIRECTION INPUT ;
    USE SIGNAL ;
    PORT
      LAYER M5 ;
        RECT  60.78 215.808 60.804 216 ;
    END
  END g_front_1_u_front__row_in[72]
  PIN g_front_1_u_front__row_in[73]
    DIRECTION INPUT ;
    USE SIGNAL ;
    PORT
      LAYER M5 ;
        RECT  61.548 215.808 61.572 216 ;
    END
  END g_front_1_u_front__row_in[73]
  PIN g_front_1_u_front__row_in[74]
    DIRECTION INPUT ;
    USE SIGNAL ;
    PORT
      LAYER M5 ;
        RECT  62.364 215.808 62.388 216 ;
    END
  END g_front_1_u_front__row_in[74]
  PIN g_front_1_u_front__row_in[75]
    DIRECTION INPUT ;
    USE SIGNAL ;
    PORT
      LAYER M5 ;
        RECT  63.132 215.808 63.156 216 ;
    END
  END g_front_1_u_front__row_in[75]
  PIN g_front_1_u_front__row_in[76]
    DIRECTION INPUT ;
    USE SIGNAL ;
    PORT
      LAYER M5 ;
        RECT  63.9 215.808 63.924 216 ;
    END
  END g_front_1_u_front__row_in[76]
  PIN g_front_1_u_front__row_in[77]
    DIRECTION INPUT ;
    USE SIGNAL ;
    PORT
      LAYER M5 ;
        RECT  64.716 215.808 64.74 216 ;
    END
  END g_front_1_u_front__row_in[77]
  PIN g_front_1_u_front__row_in[78]
    DIRECTION INPUT ;
    USE SIGNAL ;
    PORT
      LAYER M5 ;
        RECT  65.484 215.808 65.508 216 ;
    END
  END g_front_1_u_front__row_in[78]
  PIN g_front_1_u_front__row_in[79]
    DIRECTION INPUT ;
    USE SIGNAL ;
    PORT
      LAYER M5 ;
        RECT  66.3 215.808 66.324 216 ;
    END
  END g_front_1_u_front__row_in[79]
  PIN g_front_1_u_front__row_in[7]
    DIRECTION INPUT ;
    USE SIGNAL ;
    PORT
      LAYER M5 ;
        RECT  9.612 215.808 9.636 216 ;
    END
  END g_front_1_u_front__row_in[7]
  PIN g_front_1_u_front__row_in[80]
    DIRECTION INPUT ;
    USE SIGNAL ;
    PORT
      LAYER M5 ;
        RECT  67.068 215.808 67.092 216 ;
    END
  END g_front_1_u_front__row_in[80]
  PIN g_front_1_u_front__row_in[81]
    DIRECTION INPUT ;
    USE SIGNAL ;
    PORT
      LAYER M5 ;
        RECT  67.836 215.808 67.86 216 ;
    END
  END g_front_1_u_front__row_in[81]
  PIN g_front_1_u_front__row_in[82]
    DIRECTION INPUT ;
    USE SIGNAL ;
    PORT
      LAYER M5 ;
        RECT  68.652 215.808 68.676 216 ;
    END
  END g_front_1_u_front__row_in[82]
  PIN g_front_1_u_front__row_in[83]
    DIRECTION INPUT ;
    USE SIGNAL ;
    PORT
      LAYER M5 ;
        RECT  69.42 215.808 69.444 216 ;
    END
  END g_front_1_u_front__row_in[83]
  PIN g_front_1_u_front__row_in[84]
    DIRECTION INPUT ;
    USE SIGNAL ;
    PORT
      LAYER M5 ;
        RECT  70.236 215.808 70.26 216 ;
    END
  END g_front_1_u_front__row_in[84]
  PIN g_front_1_u_front__row_in[85]
    DIRECTION INPUT ;
    USE SIGNAL ;
    PORT
      LAYER M5 ;
        RECT  71.004 215.808 71.028 216 ;
    END
  END g_front_1_u_front__row_in[85]
  PIN g_front_1_u_front__row_in[86]
    DIRECTION INPUT ;
    USE SIGNAL ;
    PORT
      LAYER M5 ;
        RECT  71.772 215.808 71.796 216 ;
    END
  END g_front_1_u_front__row_in[86]
  PIN g_front_1_u_front__row_in[87]
    DIRECTION INPUT ;
    USE SIGNAL ;
    PORT
      LAYER M5 ;
        RECT  72.588 215.808 72.612 216 ;
    END
  END g_front_1_u_front__row_in[87]
  PIN g_front_1_u_front__row_in[88]
    DIRECTION INPUT ;
    USE SIGNAL ;
    PORT
      LAYER M5 ;
        RECT  73.356 215.808 73.38 216 ;
    END
  END g_front_1_u_front__row_in[88]
  PIN g_front_1_u_front__row_in[89]
    DIRECTION INPUT ;
    USE SIGNAL ;
    PORT
      LAYER M5 ;
        RECT  74.172 215.808 74.196 216 ;
    END
  END g_front_1_u_front__row_in[89]
  PIN g_front_1_u_front__row_in[8]
    DIRECTION INPUT ;
    USE SIGNAL ;
    PORT
      LAYER M5 ;
        RECT  10.428 215.808 10.452 216 ;
    END
  END g_front_1_u_front__row_in[8]
  PIN g_front_1_u_front__row_in[90]
    DIRECTION INPUT ;
    USE SIGNAL ;
    PORT
      LAYER M5 ;
        RECT  74.94 215.808 74.964 216 ;
    END
  END g_front_1_u_front__row_in[90]
  PIN g_front_1_u_front__row_in[91]
    DIRECTION INPUT ;
    USE SIGNAL ;
    PORT
      LAYER M5 ;
        RECT  75.708 215.808 75.732 216 ;
    END
  END g_front_1_u_front__row_in[91]
  PIN g_front_1_u_front__row_in[92]
    DIRECTION INPUT ;
    USE SIGNAL ;
    PORT
      LAYER M5 ;
        RECT  76.524 215.808 76.548 216 ;
    END
  END g_front_1_u_front__row_in[92]
  PIN g_front_1_u_front__row_in[93]
    DIRECTION INPUT ;
    USE SIGNAL ;
    PORT
      LAYER M5 ;
        RECT  77.292 215.808 77.316 216 ;
    END
  END g_front_1_u_front__row_in[93]
  PIN g_front_1_u_front__row_in[94]
    DIRECTION INPUT ;
    USE SIGNAL ;
    PORT
      LAYER M5 ;
        RECT  78.108 215.808 78.132 216 ;
    END
  END g_front_1_u_front__row_in[94]
  PIN g_front_1_u_front__row_in[95]
    DIRECTION INPUT ;
    USE SIGNAL ;
    PORT
      LAYER M5 ;
        RECT  78.876 215.808 78.9 216 ;
    END
  END g_front_1_u_front__row_in[95]
  PIN g_front_1_u_front__row_in[96]
    DIRECTION INPUT ;
    USE SIGNAL ;
    PORT
      LAYER M5 ;
        RECT  79.644 215.808 79.668 216 ;
    END
  END g_front_1_u_front__row_in[96]
  PIN g_front_1_u_front__row_in[97]
    DIRECTION INPUT ;
    USE SIGNAL ;
    PORT
      LAYER M5 ;
        RECT  80.46 215.808 80.484 216 ;
    END
  END g_front_1_u_front__row_in[97]
  PIN g_front_1_u_front__row_in[98]
    DIRECTION INPUT ;
    USE SIGNAL ;
    PORT
      LAYER M5 ;
        RECT  81.228 215.808 81.252 216 ;
    END
  END g_front_1_u_front__row_in[98]
  PIN g_front_1_u_front__row_in[99]
    DIRECTION INPUT ;
    USE SIGNAL ;
    PORT
      LAYER M5 ;
        RECT  81.996 215.808 82.02 216 ;
    END
  END g_front_1_u_front__row_in[99]
  PIN g_front_1_u_front__row_in[9]
    DIRECTION INPUT ;
    USE SIGNAL ;
    PORT
      LAYER M5 ;
        RECT  11.196 215.808 11.22 216 ;
    END
  END g_front_1_u_front__row_in[9]
  PIN g_front_1_u_front__rst_n[0]
    DIRECTION INPUT ;
    USE SIGNAL ;
    PORT
      LAYER M5 ;
        RECT  205.548 215.808 205.572 216 ;
    END
  END g_front_1_u_front__rst_n[0]
  PIN g_t_4_u_l8__clk[0]
    DIRECTION INPUT ;
    USE SIGNAL ;
    PORT
      LAYER M5 ;
        RECT  206.364 215.808 206.388 216 ;
    END
  END g_t_4_u_l8__clk[0]
  PIN g_t_4_u_stin__clk[0]
    DIRECTION INPUT ;
    USE SIGNAL ;
    PORT
      LAYER M5 ;
        RECT  207.132 215.808 207.156 216 ;
    END
  END g_t_4_u_stin__clk[0]
  PIN g_t_4_u_stin__rst_n[0]
    DIRECTION INPUT ;
    USE SIGNAL ;
    PORT
      LAYER M5 ;
        RECT  207.948 215.808 207.972 216 ;
    END
  END g_t_4_u_stin__rst_n[0]
  PIN g_t_4_u_stk__clk[0]
    DIRECTION INPUT ;
    USE SIGNAL ;
    PORT
      LAYER M5 ;
        RECT  208.716 215.808 208.74 216 ;
    END
  END g_t_4_u_stk__clk[0]
  PIN g_t_4_u_stk__gf_o[0]
    DIRECTION OUTPUT ;
    USE SIGNAL ;
    PORT
      LAYER M5 ;
        RECT  190.764 0 190.788 0.192 ;
    END
  END g_t_4_u_stk__gf_o[0]
  PIN g_t_4_u_stk__kp_o[0]
    DIRECTION OUTPUT ;
    USE SIGNAL ;
    PORT
      LAYER M5 ;
        RECT  191.1 0 191.124 0.192 ;
    END
  END g_t_4_u_stk__kp_o[0]
  PIN g_t_4_u_stk__kp_o[10]
    DIRECTION OUTPUT ;
    USE SIGNAL ;
    PORT
      LAYER M5 ;
        RECT  194.508 0 194.532 0.192 ;
    END
  END g_t_4_u_stk__kp_o[10]
  PIN g_t_4_u_stk__kp_o[11]
    DIRECTION OUTPUT ;
    USE SIGNAL ;
    PORT
      LAYER M5 ;
        RECT  194.844 0 194.868 0.192 ;
    END
  END g_t_4_u_stk__kp_o[11]
  PIN g_t_4_u_stk__kp_o[12]
    DIRECTION OUTPUT ;
    USE SIGNAL ;
    PORT
      LAYER M5 ;
        RECT  195.18 0 195.204 0.192 ;
    END
  END g_t_4_u_stk__kp_o[12]
  PIN g_t_4_u_stk__kp_o[13]
    DIRECTION OUTPUT ;
    USE SIGNAL ;
    PORT
      LAYER M5 ;
        RECT  195.516 0 195.54 0.192 ;
    END
  END g_t_4_u_stk__kp_o[13]
  PIN g_t_4_u_stk__kp_o[14]
    DIRECTION OUTPUT ;
    USE SIGNAL ;
    PORT
      LAYER M5 ;
        RECT  195.852 0 195.876 0.192 ;
    END
  END g_t_4_u_stk__kp_o[14]
  PIN g_t_4_u_stk__kp_o[15]
    DIRECTION OUTPUT ;
    USE SIGNAL ;
    PORT
      LAYER M5 ;
        RECT  196.236 0 196.26 0.192 ;
    END
  END g_t_4_u_stk__kp_o[15]
  PIN g_t_4_u_stk__kp_o[16]
    DIRECTION OUTPUT ;
    USE SIGNAL ;
    PORT
      LAYER M5 ;
        RECT  196.572 0 196.596 0.192 ;
    END
  END g_t_4_u_stk__kp_o[16]
  PIN g_t_4_u_stk__kp_o[17]
    DIRECTION OUTPUT ;
    USE SIGNAL ;
    PORT
      LAYER M5 ;
        RECT  196.908 0 196.932 0.192 ;
    END
  END g_t_4_u_stk__kp_o[17]
  PIN g_t_4_u_stk__kp_o[18]
    DIRECTION OUTPUT ;
    USE SIGNAL ;
    PORT
      LAYER M5 ;
        RECT  197.244 0 197.268 0.192 ;
    END
  END g_t_4_u_stk__kp_o[18]
  PIN g_t_4_u_stk__kp_o[19]
    DIRECTION OUTPUT ;
    USE SIGNAL ;
    PORT
      LAYER M5 ;
        RECT  197.58 0 197.604 0.192 ;
    END
  END g_t_4_u_stk__kp_o[19]
  PIN g_t_4_u_stk__kp_o[1]
    DIRECTION OUTPUT ;
    USE SIGNAL ;
    PORT
      LAYER M5 ;
        RECT  191.436 0 191.46 0.192 ;
    END
  END g_t_4_u_stk__kp_o[1]
  PIN g_t_4_u_stk__kp_o[20]
    DIRECTION OUTPUT ;
    USE SIGNAL ;
    PORT
      LAYER M5 ;
        RECT  197.916 0 197.94 0.192 ;
    END
  END g_t_4_u_stk__kp_o[20]
  PIN g_t_4_u_stk__kp_o[21]
    DIRECTION OUTPUT ;
    USE SIGNAL ;
    PORT
      LAYER M5 ;
        RECT  198.252 0 198.276 0.192 ;
    END
  END g_t_4_u_stk__kp_o[21]
  PIN g_t_4_u_stk__kp_o[22]
    DIRECTION OUTPUT ;
    USE SIGNAL ;
    PORT
      LAYER M5 ;
        RECT  198.588 0 198.612 0.192 ;
    END
  END g_t_4_u_stk__kp_o[22]
  PIN g_t_4_u_stk__kp_o[23]
    DIRECTION OUTPUT ;
    USE SIGNAL ;
    PORT
      LAYER M5 ;
        RECT  198.972 0 198.996 0.192 ;
    END
  END g_t_4_u_stk__kp_o[23]
  PIN g_t_4_u_stk__kp_o[24]
    DIRECTION OUTPUT ;
    USE SIGNAL ;
    PORT
      LAYER M5 ;
        RECT  199.308 0 199.332 0.192 ;
    END
  END g_t_4_u_stk__kp_o[24]
  PIN g_t_4_u_stk__kp_o[25]
    DIRECTION OUTPUT ;
    USE SIGNAL ;
    PORT
      LAYER M5 ;
        RECT  199.644 0 199.668 0.192 ;
    END
  END g_t_4_u_stk__kp_o[25]
  PIN g_t_4_u_stk__kp_o[26]
    DIRECTION OUTPUT ;
    USE SIGNAL ;
    PORT
      LAYER M5 ;
        RECT  199.98 0 200.004 0.192 ;
    END
  END g_t_4_u_stk__kp_o[26]
  PIN g_t_4_u_stk__kp_o[27]
    DIRECTION OUTPUT ;
    USE SIGNAL ;
    PORT
      LAYER M5 ;
        RECT  200.316 0 200.34 0.192 ;
    END
  END g_t_4_u_stk__kp_o[27]
  PIN g_t_4_u_stk__kp_o[28]
    DIRECTION OUTPUT ;
    USE SIGNAL ;
    PORT
      LAYER M5 ;
        RECT  200.652 0 200.676 0.192 ;
    END
  END g_t_4_u_stk__kp_o[28]
  PIN g_t_4_u_stk__kp_o[29]
    DIRECTION OUTPUT ;
    USE SIGNAL ;
    PORT
      LAYER M5 ;
        RECT  200.988 0 201.012 0.192 ;
    END
  END g_t_4_u_stk__kp_o[29]
  PIN g_t_4_u_stk__kp_o[2]
    DIRECTION OUTPUT ;
    USE SIGNAL ;
    PORT
      LAYER M5 ;
        RECT  191.772 0 191.796 0.192 ;
    END
  END g_t_4_u_stk__kp_o[2]
  PIN g_t_4_u_stk__kp_o[30]
    DIRECTION OUTPUT ;
    USE SIGNAL ;
    PORT
      LAYER M5 ;
        RECT  201.324 0 201.348 0.192 ;
    END
  END g_t_4_u_stk__kp_o[30]
  PIN g_t_4_u_stk__kp_o[31]
    DIRECTION OUTPUT ;
    USE SIGNAL ;
    PORT
      LAYER M5 ;
        RECT  201.708 0 201.732 0.192 ;
    END
  END g_t_4_u_stk__kp_o[31]
  PIN g_t_4_u_stk__kp_o[3]
    DIRECTION OUTPUT ;
    USE SIGNAL ;
    PORT
      LAYER M5 ;
        RECT  192.108 0 192.132 0.192 ;
    END
  END g_t_4_u_stk__kp_o[3]
  PIN g_t_4_u_stk__kp_o[4]
    DIRECTION OUTPUT ;
    USE SIGNAL ;
    PORT
      LAYER M5 ;
        RECT  192.444 0 192.468 0.192 ;
    END
  END g_t_4_u_stk__kp_o[4]
  PIN g_t_4_u_stk__kp_o[5]
    DIRECTION OUTPUT ;
    USE SIGNAL ;
    PORT
      LAYER M5 ;
        RECT  192.78 0 192.804 0.192 ;
    END
  END g_t_4_u_stk__kp_o[5]
  PIN g_t_4_u_stk__kp_o[6]
    DIRECTION OUTPUT ;
    USE SIGNAL ;
    PORT
      LAYER M5 ;
        RECT  193.116 0 193.14 0.192 ;
    END
  END g_t_4_u_stk__kp_o[6]
  PIN g_t_4_u_stk__kp_o[7]
    DIRECTION OUTPUT ;
    USE SIGNAL ;
    PORT
      LAYER M5 ;
        RECT  193.5 0 193.524 0.192 ;
    END
  END g_t_4_u_stk__kp_o[7]
  PIN g_t_4_u_stk__kp_o[8]
    DIRECTION OUTPUT ;
    USE SIGNAL ;
    PORT
      LAYER M5 ;
        RECT  193.836 0 193.86 0.192 ;
    END
  END g_t_4_u_stk__kp_o[8]
  PIN g_t_4_u_stk__kp_o[9]
    DIRECTION OUTPUT ;
    USE SIGNAL ;
    PORT
      LAYER M5 ;
        RECT  194.172 0 194.196 0.192 ;
    END
  END g_t_4_u_stk__kp_o[9]
  PIN g_t_4_u_stk__kpv_o[0]
    DIRECTION OUTPUT ;
    USE SIGNAL ;
    PORT
      LAYER M5 ;
        RECT  202.044 0 202.068 0.192 ;
    END
  END g_t_4_u_stk__kpv_o[0]
  PIN g_t_4_u_stk__rst_n[0]
    DIRECTION INPUT ;
    USE SIGNAL ;
    PORT
      LAYER M5 ;
        RECT  209.484 215.808 209.508 216 ;
    END
  END g_t_4_u_stk__rst_n[0]
  PIN g_t_5_u_l8__clk[0]
    DIRECTION INPUT ;
    USE SIGNAL ;
    PORT
      LAYER M5 ;
        RECT  210.3 215.808 210.324 216 ;
    END
  END g_t_5_u_l8__clk[0]
  PIN g_t_5_u_stin__clk[0]
    DIRECTION INPUT ;
    USE SIGNAL ;
    PORT
      LAYER M5 ;
        RECT  211.068 215.808 211.092 216 ;
    END
  END g_t_5_u_stin__clk[0]
  PIN g_t_5_u_stin__rst_n[0]
    DIRECTION INPUT ;
    USE SIGNAL ;
    PORT
      LAYER M5 ;
        RECT  211.884 215.808 211.908 216 ;
    END
  END g_t_5_u_stin__rst_n[0]
  PIN g_t_5_u_stk__clk[0]
    DIRECTION INPUT ;
    USE SIGNAL ;
    PORT
      LAYER M5 ;
        RECT  212.652 215.808 212.676 216 ;
    END
  END g_t_5_u_stk__clk[0]
  PIN g_t_5_u_stk__gf_o[0]
    DIRECTION OUTPUT ;
    USE SIGNAL ;
    PORT
      LAYER M5 ;
        RECT  202.38 0 202.404 0.192 ;
    END
  END g_t_5_u_stk__gf_o[0]
  PIN g_t_5_u_stk__kp_o[0]
    DIRECTION OUTPUT ;
    USE SIGNAL ;
    PORT
      LAYER M5 ;
        RECT  202.716 0 202.74 0.192 ;
    END
  END g_t_5_u_stk__kp_o[0]
  PIN g_t_5_u_stk__kp_o[10]
    DIRECTION OUTPUT ;
    USE SIGNAL ;
    PORT
      LAYER M5 ;
        RECT  206.124 0 206.148 0.192 ;
    END
  END g_t_5_u_stk__kp_o[10]
  PIN g_t_5_u_stk__kp_o[11]
    DIRECTION OUTPUT ;
    USE SIGNAL ;
    PORT
      LAYER M5 ;
        RECT  206.46 0 206.484 0.192 ;
    END
  END g_t_5_u_stk__kp_o[11]
  PIN g_t_5_u_stk__kp_o[12]
    DIRECTION OUTPUT ;
    USE SIGNAL ;
    PORT
      LAYER M5 ;
        RECT  206.796 0 206.82 0.192 ;
    END
  END g_t_5_u_stk__kp_o[12]
  PIN g_t_5_u_stk__kp_o[13]
    DIRECTION OUTPUT ;
    USE SIGNAL ;
    PORT
      LAYER M5 ;
        RECT  207.18 0 207.204 0.192 ;
    END
  END g_t_5_u_stk__kp_o[13]
  PIN g_t_5_u_stk__kp_o[14]
    DIRECTION OUTPUT ;
    USE SIGNAL ;
    PORT
      LAYER M5 ;
        RECT  207.516 0 207.54 0.192 ;
    END
  END g_t_5_u_stk__kp_o[14]
  PIN g_t_5_u_stk__kp_o[15]
    DIRECTION OUTPUT ;
    USE SIGNAL ;
    PORT
      LAYER M5 ;
        RECT  207.852 0 207.876 0.192 ;
    END
  END g_t_5_u_stk__kp_o[15]
  PIN g_t_5_u_stk__kp_o[16]
    DIRECTION OUTPUT ;
    USE SIGNAL ;
    PORT
      LAYER M5 ;
        RECT  208.188 0 208.212 0.192 ;
    END
  END g_t_5_u_stk__kp_o[16]
  PIN g_t_5_u_stk__kp_o[17]
    DIRECTION OUTPUT ;
    USE SIGNAL ;
    PORT
      LAYER M5 ;
        RECT  208.524 0 208.548 0.192 ;
    END
  END g_t_5_u_stk__kp_o[17]
  PIN g_t_5_u_stk__kp_o[18]
    DIRECTION OUTPUT ;
    USE SIGNAL ;
    PORT
      LAYER M5 ;
        RECT  208.86 0 208.884 0.192 ;
    END
  END g_t_5_u_stk__kp_o[18]
  PIN g_t_5_u_stk__kp_o[19]
    DIRECTION OUTPUT ;
    USE SIGNAL ;
    PORT
      LAYER M5 ;
        RECT  209.196 0 209.22 0.192 ;
    END
  END g_t_5_u_stk__kp_o[19]
  PIN g_t_5_u_stk__kp_o[1]
    DIRECTION OUTPUT ;
    USE SIGNAL ;
    PORT
      LAYER M5 ;
        RECT  203.052 0 203.076 0.192 ;
    END
  END g_t_5_u_stk__kp_o[1]
  PIN g_t_5_u_stk__kp_o[20]
    DIRECTION OUTPUT ;
    USE SIGNAL ;
    PORT
      LAYER M5 ;
        RECT  209.532 0 209.556 0.192 ;
    END
  END g_t_5_u_stk__kp_o[20]
  PIN g_t_5_u_stk__kp_o[21]
    DIRECTION OUTPUT ;
    USE SIGNAL ;
    PORT
      LAYER M5 ;
        RECT  209.916 0 209.94 0.192 ;
    END
  END g_t_5_u_stk__kp_o[21]
  PIN g_t_5_u_stk__kp_o[22]
    DIRECTION OUTPUT ;
    USE SIGNAL ;
    PORT
      LAYER M5 ;
        RECT  210.252 0 210.276 0.192 ;
    END
  END g_t_5_u_stk__kp_o[22]
  PIN g_t_5_u_stk__kp_o[23]
    DIRECTION OUTPUT ;
    USE SIGNAL ;
    PORT
      LAYER M5 ;
        RECT  210.588 0 210.612 0.192 ;
    END
  END g_t_5_u_stk__kp_o[23]
  PIN g_t_5_u_stk__kp_o[24]
    DIRECTION OUTPUT ;
    USE SIGNAL ;
    PORT
      LAYER M5 ;
        RECT  210.924 0 210.948 0.192 ;
    END
  END g_t_5_u_stk__kp_o[24]
  PIN g_t_5_u_stk__kp_o[25]
    DIRECTION OUTPUT ;
    USE SIGNAL ;
    PORT
      LAYER M5 ;
        RECT  211.26 0 211.284 0.192 ;
    END
  END g_t_5_u_stk__kp_o[25]
  PIN g_t_5_u_stk__kp_o[26]
    DIRECTION OUTPUT ;
    USE SIGNAL ;
    PORT
      LAYER M5 ;
        RECT  211.596 0 211.62 0.192 ;
    END
  END g_t_5_u_stk__kp_o[26]
  PIN g_t_5_u_stk__kp_o[27]
    DIRECTION OUTPUT ;
    USE SIGNAL ;
    PORT
      LAYER M5 ;
        RECT  211.932 0 211.956 0.192 ;
    END
  END g_t_5_u_stk__kp_o[27]
  PIN g_t_5_u_stk__kp_o[28]
    DIRECTION OUTPUT ;
    USE SIGNAL ;
    PORT
      LAYER M5 ;
        RECT  212.268 0 212.292 0.192 ;
    END
  END g_t_5_u_stk__kp_o[28]
  PIN g_t_5_u_stk__kp_o[29]
    DIRECTION OUTPUT ;
    USE SIGNAL ;
    PORT
      LAYER M5 ;
        RECT  212.652 0 212.676 0.192 ;
    END
  END g_t_5_u_stk__kp_o[29]
  PIN g_t_5_u_stk__kp_o[2]
    DIRECTION OUTPUT ;
    USE SIGNAL ;
    PORT
      LAYER M5 ;
        RECT  203.388 0 203.412 0.192 ;
    END
  END g_t_5_u_stk__kp_o[2]
  PIN g_t_5_u_stk__kp_o[30]
    DIRECTION OUTPUT ;
    USE SIGNAL ;
    PORT
      LAYER M5 ;
        RECT  212.988 0 213.012 0.192 ;
    END
  END g_t_5_u_stk__kp_o[30]
  PIN g_t_5_u_stk__kp_o[31]
    DIRECTION OUTPUT ;
    USE SIGNAL ;
    PORT
      LAYER M5 ;
        RECT  213.324 0 213.348 0.192 ;
    END
  END g_t_5_u_stk__kp_o[31]
  PIN g_t_5_u_stk__kp_o[3]
    DIRECTION OUTPUT ;
    USE SIGNAL ;
    PORT
      LAYER M5 ;
        RECT  203.724 0 203.748 0.192 ;
    END
  END g_t_5_u_stk__kp_o[3]
  PIN g_t_5_u_stk__kp_o[4]
    DIRECTION OUTPUT ;
    USE SIGNAL ;
    PORT
      LAYER M5 ;
        RECT  204.06 0 204.084 0.192 ;
    END
  END g_t_5_u_stk__kp_o[4]
  PIN g_t_5_u_stk__kp_o[5]
    DIRECTION OUTPUT ;
    USE SIGNAL ;
    PORT
      LAYER M5 ;
        RECT  204.444 0 204.468 0.192 ;
    END
  END g_t_5_u_stk__kp_o[5]
  PIN g_t_5_u_stk__kp_o[6]
    DIRECTION OUTPUT ;
    USE SIGNAL ;
    PORT
      LAYER M5 ;
        RECT  204.78 0 204.804 0.192 ;
    END
  END g_t_5_u_stk__kp_o[6]
  PIN g_t_5_u_stk__kp_o[7]
    DIRECTION OUTPUT ;
    USE SIGNAL ;
    PORT
      LAYER M5 ;
        RECT  205.116 0 205.14 0.192 ;
    END
  END g_t_5_u_stk__kp_o[7]
  PIN g_t_5_u_stk__kp_o[8]
    DIRECTION OUTPUT ;
    USE SIGNAL ;
    PORT
      LAYER M5 ;
        RECT  205.452 0 205.476 0.192 ;
    END
  END g_t_5_u_stk__kp_o[8]
  PIN g_t_5_u_stk__kp_o[9]
    DIRECTION OUTPUT ;
    USE SIGNAL ;
    PORT
      LAYER M5 ;
        RECT  205.788 0 205.812 0.192 ;
    END
  END g_t_5_u_stk__kp_o[9]
  PIN g_t_5_u_stk__kpv_o[0]
    DIRECTION OUTPUT ;
    USE SIGNAL ;
    PORT
      LAYER M5 ;
        RECT  213.66 0 213.684 0.192 ;
    END
  END g_t_5_u_stk__kpv_o[0]
  PIN g_t_5_u_stk__rst_n[0]
    DIRECTION INPUT ;
    USE SIGNAL ;
    PORT
      LAYER M5 ;
        RECT  213.42 215.808 213.444 216 ;
    END
  END g_t_5_u_stk__rst_n[0]
  PIN VSS
    DIRECTION INOUT ;
    USE GROUND ;
    PORT
      LAYER M5 ;
        RECT  209.364 4.297 209.484 211.703 ;
        RECT  205.044 4.297 205.164 211.703 ;
        RECT  200.724 4.297 200.844 211.703 ;
        RECT  196.404 4.297 196.524 211.703 ;
        RECT  192.084 4.297 192.204 211.703 ;
        RECT  187.764 4.297 187.884 211.703 ;
        RECT  183.444 4.297 183.564 211.703 ;
        RECT  179.124 4.297 179.244 211.703 ;
        RECT  174.804 4.297 174.924 211.703 ;
        RECT  170.484 4.297 170.604 211.703 ;
        RECT  166.164 4.297 166.284 211.703 ;
        RECT  161.844 4.297 161.964 211.703 ;
        RECT  157.524 4.297 157.644 211.703 ;
        RECT  153.204 4.297 153.324 211.703 ;
        RECT  148.884 4.297 149.004 211.703 ;
        RECT  144.564 4.297 144.684 211.703 ;
        RECT  140.244 4.297 140.364 211.703 ;
        RECT  135.924 4.297 136.044 211.703 ;
        RECT  131.604 4.297 131.724 211.703 ;
        RECT  127.284 4.297 127.404 211.703 ;
        RECT  122.964 4.297 123.084 211.703 ;
        RECT  118.644 4.297 118.764 211.703 ;
        RECT  114.324 4.297 114.444 211.703 ;
        RECT  110.004 4.297 110.124 211.703 ;
        RECT  105.684 4.297 105.804 211.703 ;
        RECT  101.364 4.297 101.484 211.703 ;
        RECT  97.044 4.297 97.164 211.703 ;
        RECT  92.724 4.297 92.844 211.703 ;
        RECT  88.404 4.297 88.524 211.703 ;
        RECT  84.084 4.297 84.204 211.703 ;
        RECT  79.764 4.297 79.884 211.703 ;
        RECT  75.444 4.297 75.564 211.703 ;
        RECT  71.124 4.297 71.244 211.703 ;
        RECT  66.804 4.297 66.924 211.703 ;
        RECT  62.484 4.297 62.604 211.703 ;
        RECT  58.164 4.297 58.284 211.703 ;
        RECT  53.844 4.297 53.964 211.703 ;
        RECT  49.524 4.297 49.644 211.703 ;
        RECT  45.204 4.297 45.324 211.703 ;
        RECT  40.884 4.297 41.004 211.703 ;
        RECT  36.564 4.297 36.684 211.703 ;
        RECT  32.244 4.297 32.364 211.703 ;
        RECT  27.924 4.297 28.044 211.703 ;
        RECT  23.604 4.297 23.724 211.703 ;
        RECT  19.284 4.297 19.404 211.703 ;
        RECT  14.964 4.297 15.084 211.703 ;
        RECT  10.644 4.297 10.764 211.703 ;
        RECT  6.324 4.297 6.444 211.703 ;
    END
  END VSS
  PIN VDD
    DIRECTION INOUT ;
    USE POWER ;
    PORT
      LAYER M5 ;
        RECT  209.556 4.311 209.676 211.689 ;
        RECT  205.236 4.311 205.356 211.689 ;
        RECT  200.916 4.311 201.036 211.689 ;
        RECT  196.596 4.311 196.716 211.689 ;
        RECT  192.276 4.311 192.396 211.689 ;
        RECT  187.956 4.311 188.076 211.689 ;
        RECT  183.636 4.311 183.756 211.689 ;
        RECT  179.316 4.311 179.436 211.689 ;
        RECT  174.996 4.311 175.116 211.689 ;
        RECT  170.676 4.311 170.796 211.689 ;
        RECT  166.356 4.311 166.476 211.689 ;
        RECT  162.036 4.311 162.156 211.689 ;
        RECT  157.716 4.311 157.836 211.689 ;
        RECT  153.396 4.311 153.516 211.689 ;
        RECT  149.076 4.311 149.196 211.689 ;
        RECT  144.756 4.311 144.876 211.689 ;
        RECT  140.436 4.311 140.556 211.689 ;
        RECT  136.116 4.311 136.236 211.689 ;
        RECT  131.796 4.311 131.916 211.689 ;
        RECT  127.476 4.311 127.596 211.689 ;
        RECT  123.156 4.311 123.276 211.689 ;
        RECT  118.836 4.311 118.956 211.689 ;
        RECT  114.516 4.311 114.636 211.689 ;
        RECT  110.196 4.311 110.316 211.689 ;
        RECT  105.876 4.311 105.996 211.689 ;
        RECT  101.556 4.311 101.676 211.689 ;
        RECT  97.236 4.311 97.356 211.689 ;
        RECT  92.916 4.311 93.036 211.689 ;
        RECT  88.596 4.311 88.716 211.689 ;
        RECT  84.276 4.311 84.396 211.689 ;
        RECT  79.956 4.311 80.076 211.689 ;
        RECT  75.636 4.311 75.756 211.689 ;
        RECT  71.316 4.311 71.436 211.689 ;
        RECT  66.996 4.311 67.116 211.689 ;
        RECT  62.676 4.311 62.796 211.689 ;
        RECT  58.356 4.311 58.476 211.689 ;
        RECT  54.036 4.311 54.156 211.689 ;
        RECT  49.716 4.311 49.836 211.689 ;
        RECT  45.396 4.311 45.516 211.689 ;
        RECT  41.076 4.311 41.196 211.689 ;
        RECT  36.756 4.311 36.876 211.689 ;
        RECT  32.436 4.311 32.556 211.689 ;
        RECT  28.116 4.311 28.236 211.689 ;
        RECT  23.796 4.311 23.916 211.689 ;
        RECT  19.476 4.311 19.596 211.689 ;
        RECT  15.156 4.311 15.276 211.689 ;
        RECT  10.836 4.311 10.956 211.689 ;
        RECT  6.516 4.311 6.636 211.689 ;
    END
  END VDD
  OBS
    LAYER RVTN ;
     RECT  0 0 216 216 ;
    LAYER RVTP ;
     RECT  0 0 216 216 ;
    LAYER M1 ;
     RECT  0 0 216 216 ;
    LAYER M2 ;
     RECT  0 0 216 216 ;
    LAYER M3 ;
     RECT  0 0 216 216 ;
    LAYER M4 ;
     RECT  0 0 216 216 ;
    LAYER M5 ;
     RECT  0 0 216 216 ;
    LAYER M6 ;
     RECT  0 0 216 216 ;
    LAYER M7 ;
     RECT  0 0 216 216 ;
  END
END kv3_head_eighth_e2
END LIBRARY
